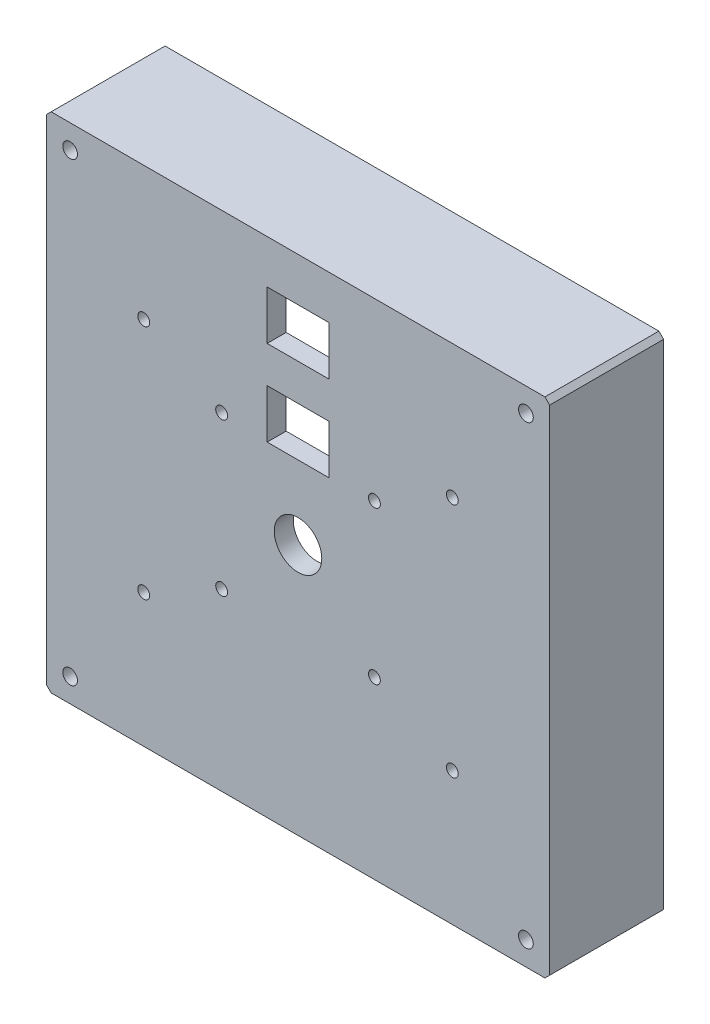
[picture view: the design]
ISO-10303-21;
HEADER;
FILE_DESCRIPTION(('STEP AP214'),'2;1');
FILE_NAME('part.step','',(''),(''),'','','');
FILE_SCHEMA(('AUTOMOTIVE_DESIGN { 1 0 10303 214 1 1 1 1 }'));
ENDSEC;
DATA;
#1=APPLICATION_CONTEXT('core data for automotive mechanical design processes');
#2=APPLICATION_PROTOCOL_DEFINITION('international standard','automotive_design',2000,#1);
#3=PRODUCT_CONTEXT('',#1,'mechanical');
#4=PRODUCT('Part','Part','',(#3));
#5=PRODUCT_RELATED_PRODUCT_CATEGORY('part','',(#4));
#6=PRODUCT_DEFINITION_FORMATION('','',#4);
#7=PRODUCT_DEFINITION_CONTEXT('part definition',#1,'design');
#8=PRODUCT_DEFINITION('design','',#6,#7);
#9=PRODUCT_DEFINITION_SHAPE('','',#8);
#10=(LENGTH_UNIT() NAMED_UNIT(*) SI_UNIT(.MILLI.,.METRE.));
#11=(NAMED_UNIT(*) PLANE_ANGLE_UNIT() SI_UNIT($,.RADIAN.));
#12=(NAMED_UNIT(*) SI_UNIT($,.STERADIAN.) SOLID_ANGLE_UNIT());
#13=UNCERTAINTY_MEASURE_WITH_UNIT(LENGTH_MEASURE(1.E-05),#10,'distance_accuracy_value','');
#14=(GEOMETRIC_REPRESENTATION_CONTEXT(3) GLOBAL_UNCERTAINTY_ASSIGNED_CONTEXT((#13)) GLOBAL_UNIT_ASSIGNED_CONTEXT((#10,
#11,#12)) REPRESENTATION_CONTEXT('',''));
#15=CARTESIAN_POINT('',(0.,0.,0.));
#16=DIRECTION('',(0.,0.,1.));
#17=DIRECTION('',(1.,0.,0.));
#18=AXIS2_PLACEMENT_3D('',#15,#16,#17);
#19=CARTESIAN_POINT('',(-53.,53.,-4.));
#20=DIRECTION('',(-1.,0.,0.));
#21=DIRECTION('',(0.,-1.,0.));
#22=AXIS2_PLACEMENT_3D('',#19,#20,#21);
#23=PLANE('',#22);
#24=DIRECTION('',(0.,-1.,0.));
#25=VECTOR('',#24,1.);
#26=CARTESIAN_POINT('',(-53.,53.,0.));
#27=LINE('',#26,#25);
#28=CARTESIAN_POINT('',(-53.,52.,0.));
#29=VERTEX_POINT('',#28);
#30=CARTESIAN_POINT('',(-53.,-52.,0.));
#31=VERTEX_POINT('',#30);
#32=EDGE_CURVE('E1000',#29,#31,#27,.T.);
#33=ORIENTED_EDGE('',*,*,#32,.F.);
#34=DIRECTION('',(0.,0.,-1.));
#35=VECTOR('',#34,1.);
#36=CARTESIAN_POINT('',(-53.,52.,-4.));
#37=LINE('',#36,#35);
#38=CARTESIAN_POINT('',(-53.,52.,-24.));
#39=VERTEX_POINT('',#38);
#40=EDGE_CURVE('E474',#29,#39,#37,.T.);
#41=ORIENTED_EDGE('',*,*,#40,.T.);
#42=DIRECTION('',(0.,1.,0.));
#43=VECTOR('',#42,1.);
#44=CARTESIAN_POINT('',(-53.,53.,-24.));
#45=LINE('',#44,#43);
#46=CARTESIAN_POINT('',(-53.,-52.,-24.));
#47=VERTEX_POINT('',#46);
#48=EDGE_CURVE('E994',#47,#39,#45,.T.);
#49=ORIENTED_EDGE('',*,*,#48,.F.);
#50=DIRECTION('',(0.,0.,1.));
#51=VECTOR('',#50,1.);
#52=CARTESIAN_POINT('',(-53.,-52.,-4.));
#53=LINE('',#52,#51);
#54=EDGE_CURVE('E471',#47,#31,#53,.T.);
#55=ORIENTED_EDGE('',*,*,#54,.T.);
#56=EDGE_LOOP('',(#33,#41,#49,#55));
#57=FACE_BOUND('',#56,.T.);
#58=ADVANCED_FACE('F33',(#57),#23,.T.);
#59=CARTESIAN_POINT('',(-53.,53.,-4.));
#60=DIRECTION('',(0.,1.,0.));
#61=DIRECTION('',(-1.,0.,0.));
#62=AXIS2_PLACEMENT_3D('',#59,#60,#61);
#63=PLANE('',#62);
#64=DIRECTION('',(-1.,0.,0.));
#65=VECTOR('',#64,1.);
#66=CARTESIAN_POINT('',(-53.,53.,0.));
#67=LINE('',#66,#65);
#68=CARTESIAN_POINT('',(52.,53.,0.));
#69=VERTEX_POINT('',#68);
#70=CARTESIAN_POINT('',(-52.,53.,0.));
#71=VERTEX_POINT('',#70);
#72=EDGE_CURVE('E1009',#69,#71,#67,.T.);
#73=ORIENTED_EDGE('',*,*,#72,.F.);
#74=DIRECTION('',(0.,0.,-1.));
#75=VECTOR('',#74,1.);
#76=CARTESIAN_POINT('',(52.,53.,-4.));
#77=LINE('',#76,#75);
#78=CARTESIAN_POINT('',(52.,53.,-24.));
#79=VERTEX_POINT('',#78);
#80=EDGE_CURVE('E461',#69,#79,#77,.T.);
#81=ORIENTED_EDGE('',*,*,#80,.T.);
#82=DIRECTION('',(1.,0.,0.));
#83=VECTOR('',#82,1.);
#84=CARTESIAN_POINT('',(53.,53.,-24.));
#85=LINE('',#84,#83);
#86=CARTESIAN_POINT('',(-52.,53.,-24.));
#87=VERTEX_POINT('',#86);
#88=EDGE_CURVE('E997',#87,#79,#85,.T.);
#89=ORIENTED_EDGE('',*,*,#88,.F.);
#90=DIRECTION('',(0.,0.,1.));
#91=VECTOR('',#90,1.);
#92=CARTESIAN_POINT('',(-52.,53.,-4.));
#93=LINE('',#92,#91);
#94=EDGE_CURVE('E458',#87,#71,#93,.T.);
#95=ORIENTED_EDGE('',*,*,#94,.T.);
#96=EDGE_LOOP('',(#73,#81,#89,#95));
#97=FACE_BOUND('',#96,.T.);
#98=ADVANCED_FACE('F1122',(#97),#63,.T.);
#99=CARTESIAN_POINT('',(53.,53.,-4.));
#100=DIRECTION('',(1.,0.,0.));
#101=DIRECTION('',(0.,1.,0.));
#102=AXIS2_PLACEMENT_3D('',#99,#100,#101);
#103=PLANE('',#102);
#104=DIRECTION('',(0.,-1.,0.));
#105=VECTOR('',#104,1.);
#106=CARTESIAN_POINT('',(53.,53.,-24.));
#107=LINE('',#106,#105);
#108=CARTESIAN_POINT('',(53.,52.,-24.));
#109=VERTEX_POINT('',#108);
#110=CARTESIAN_POINT('',(53.,-52.,-24.));
#111=VERTEX_POINT('',#110);
#112=EDGE_CURVE('E988',#109,#111,#107,.T.);
#113=ORIENTED_EDGE('',*,*,#112,.F.);
#114=DIRECTION('',(0.,0.,1.));
#115=VECTOR('',#114,1.);
#116=CARTESIAN_POINT('',(53.,52.,-4.));
#117=LINE('',#116,#115);
#118=CARTESIAN_POINT('',(53.,52.,0.));
#119=VERTEX_POINT('',#118);
#120=EDGE_CURVE('E443',#109,#119,#117,.T.);
#121=ORIENTED_EDGE('',*,*,#120,.T.);
#122=DIRECTION('',(0.,1.,0.));
#123=VECTOR('',#122,1.);
#124=CARTESIAN_POINT('',(53.,53.,0.));
#125=LINE('',#124,#123);
#126=CARTESIAN_POINT('',(53.,-52.,0.));
#127=VERTEX_POINT('',#126);
#128=EDGE_CURVE('E1006',#127,#119,#125,.T.);
#129=ORIENTED_EDGE('',*,*,#128,.F.);
#130=DIRECTION('',(0.,0.,-1.));
#131=VECTOR('',#130,1.);
#132=CARTESIAN_POINT('',(53.,-52.,-4.));
#133=LINE('',#132,#131);
#134=EDGE_CURVE('E441',#127,#111,#133,.T.);
#135=ORIENTED_EDGE('',*,*,#134,.T.);
#136=EDGE_LOOP('',(#113,#121,#129,#135));
#137=FACE_BOUND('',#136,.T.);
#138=ADVANCED_FACE('F1096',(#137),#103,.T.);
#139=CARTESIAN_POINT('',(-53.,-53.,-4.));
#140=DIRECTION('',(0.,-1.,0.));
#141=DIRECTION('',(1.,0.,0.));
#142=AXIS2_PLACEMENT_3D('',#139,#140,#141);
#143=PLANE('',#142);
#144=DIRECTION('',(0.,0.,1.));
#145=VECTOR('',#144,1.);
#146=CARTESIAN_POINT('',(-7.49999999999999,-53.,-6.83));
#147=LINE('',#146,#145);
#148=CARTESIAN_POINT('',(-7.5,-53.,-15.83));
#149=VERTEX_POINT('',#148);
#150=CARTESIAN_POINT('',(-7.49999999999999,-53.,-5.83));
#151=VERTEX_POINT('',#150);
#152=EDGE_CURVE('E484',#149,#151,#147,.T.);
#153=ORIENTED_EDGE('',*,*,#152,.T.);
#154=DIRECTION('',(1.,0.,0.));
#155=VECTOR('',#154,1.);
#156=CARTESIAN_POINT('',(6.5,-53.,-5.83));
#157=LINE('',#156,#155);
#158=CARTESIAN_POINT('',(7.5,-53.,-5.83));
#159=VERTEX_POINT('',#158);
#160=EDGE_CURVE('E490',#151,#159,#157,.T.);
#161=ORIENTED_EDGE('',*,*,#160,.T.);
#162=DIRECTION('',(0.,0.,-1.));
#163=VECTOR('',#162,1.);
#164=CARTESIAN_POINT('',(7.5,-53.,-14.83));
#165=LINE('',#164,#163);
#166=CARTESIAN_POINT('',(7.5,-53.,-15.83));
#167=VERTEX_POINT('',#166);
#168=EDGE_CURVE('E488',#159,#167,#165,.T.);
#169=ORIENTED_EDGE('',*,*,#168,.T.);
#170=DIRECTION('',(-1.,0.,0.));
#171=VECTOR('',#170,1.);
#172=CARTESIAN_POINT('',(-6.49999999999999,-53.,-15.83));
#173=LINE('',#172,#171);
#174=EDGE_CURVE('E486',#167,#149,#173,.T.);
#175=ORIENTED_EDGE('',*,*,#174,.T.);
#176=EDGE_LOOP('',(#153,#161,#169,#175));
#177=FACE_BOUND('',#176,.T.);
#178=DIRECTION('',(1.,0.,0.));
#179=VECTOR('',#178,1.);
#180=CARTESIAN_POINT('',(-53.,-53.,0.));
#181=LINE('',#180,#179);
#182=CARTESIAN_POINT('',(-52.,-53.,0.));
#183=VERTEX_POINT('',#182);
#184=CARTESIAN_POINT('',(52.,-53.,0.));
#185=VERTEX_POINT('',#184);
#186=EDGE_CURVE('E1003',#183,#185,#181,.T.);
#187=ORIENTED_EDGE('',*,*,#186,.F.);
#188=DIRECTION('',(0.,0.,-1.));
#189=VECTOR('',#188,1.);
#190=CARTESIAN_POINT('',(-52.,-53.,-4.));
#191=LINE('',#190,#189);
#192=CARTESIAN_POINT('',(-52.,-53.,-24.));
#193=VERTEX_POINT('',#192);
#194=EDGE_CURVE('E479',#183,#193,#191,.T.);
#195=ORIENTED_EDGE('',*,*,#194,.T.);
#196=DIRECTION('',(-1.,0.,0.));
#197=VECTOR('',#196,1.);
#198=CARTESIAN_POINT('',(53.,-53.,-24.));
#199=LINE('',#198,#197);
#200=CARTESIAN_POINT('',(52.,-53.,-24.));
#201=VERTEX_POINT('',#200);
#202=EDGE_CURVE('E991',#201,#193,#199,.T.);
#203=ORIENTED_EDGE('',*,*,#202,.F.);
#204=DIRECTION('',(0.,0.,1.));
#205=VECTOR('',#204,1.);
#206=CARTESIAN_POINT('',(52.,-53.,-4.));
#207=LINE('',#206,#205);
#208=EDGE_CURVE('E476',#201,#185,#207,.T.);
#209=ORIENTED_EDGE('',*,*,#208,.T.);
#210=EDGE_LOOP('',(#187,#195,#203,#209));
#211=FACE_BOUND('',#210,.T.);
#212=ADVANCED_FACE('F1092',(#177,#211),#143,.T.);
#213=CARTESIAN_POINT('',(0.,0.,0.));
#214=DIRECTION('',(0.,0.,1.));
#215=DIRECTION('',(1.,0.,0.));
#216=AXIS2_PLACEMENT_3D('',#213,#214,#215);
#217=PLANE('',#216);
#218=DIRECTION('',(0.,-1.,0.));
#219=VECTOR('',#218,1.);
#220=CARTESIAN_POINT('',(-6.5,43.8,0.));
#221=LINE('',#220,#219);
#222=CARTESIAN_POINT('',(-6.5,43.8,0.));
#223=VERTEX_POINT('',#222);
#224=CARTESIAN_POINT('',(-6.5,33.5,0.));
#225=VERTEX_POINT('',#224);
#226=EDGE_CURVE('E848',#223,#225,#221,.T.);
#227=ORIENTED_EDGE('',*,*,#226,.F.);
#228=DIRECTION('',(-1.,0.,0.));
#229=VECTOR('',#228,1.);
#230=CARTESIAN_POINT('',(-6.5,43.8,0.));
#231=LINE('',#230,#229);
#232=CARTESIAN_POINT('',(6.5,43.8,0.));
#233=VERTEX_POINT('',#232);
#234=EDGE_CURVE('E857',#233,#223,#231,.T.);
#235=ORIENTED_EDGE('',*,*,#234,.F.);
#236=DIRECTION('',(0.,1.,0.));
#237=VECTOR('',#236,1.);
#238=CARTESIAN_POINT('',(6.5,43.8,0.));
#239=LINE('',#238,#237);
#240=CARTESIAN_POINT('',(6.5,33.5,0.));
#241=VERTEX_POINT('',#240);
#242=EDGE_CURVE('E854',#241,#233,#239,.T.);
#243=ORIENTED_EDGE('',*,*,#242,.F.);
#244=DIRECTION('',(1.,0.,0.));
#245=VECTOR('',#244,1.);
#246=CARTESIAN_POINT('',(-6.5,33.5,0.));
#247=LINE('',#246,#245);
#248=EDGE_CURVE('E850',#225,#241,#247,.T.);
#249=ORIENTED_EDGE('',*,*,#248,.F.);
#250=EDGE_LOOP('',(#227,#235,#243,#249));
#251=FACE_BOUND('',#250,.T.);
#252=CARTESIAN_POINT('',(0.,0.,0.));
#253=DIRECTION('',(0.,0.,1.));
#254=DIRECTION('',(1.,0.,0.));
#255=AXIS2_PLACEMENT_3D('',#252,#253,#254);
#256=CIRCLE('',#255,5.);
#257=CARTESIAN_POINT('',(5.,0.,0.));
#258=VERTEX_POINT('',#257);
#259=EDGE_CURVE('E845',#258,#258,#256,.T.);
#260=ORIENTED_EDGE('',*,*,#259,.F.);
#261=EDGE_LOOP('',(#260));
#262=FACE_BOUND('',#261,.T.);
#263=CARTESIAN_POINT('',(-16.086679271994,16.086679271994,0.));
#264=DIRECTION('',(0.,0.,1.));
#265=DIRECTION('',(1.,0.,0.));
#266=AXIS2_PLACEMENT_3D('',#263,#264,#265);
#267=CIRCLE('',#266,1.25);
#268=CARTESIAN_POINT('',(-14.836679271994,16.086679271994,0.));
#269=VERTEX_POINT('',#268);
#270=EDGE_CURVE('E870',#269,#269,#267,.T.);
#271=ORIENTED_EDGE('',*,*,#270,.F.);
#272=EDGE_LOOP('',(#271));
#273=FACE_BOUND('',#272,.T.);
#274=DIRECTION('',(0.,-1.,0.));
#275=VECTOR('',#274,1.);
#276=CARTESIAN_POINT('',(-6.49999999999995,25.8,0.));
#277=LINE('',#276,#275);
#278=CARTESIAN_POINT('',(-6.49999999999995,25.8,0.));
#279=VERTEX_POINT('',#278);
#280=CARTESIAN_POINT('',(-6.49999999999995,15.5,0.));
#281=VERTEX_POINT('',#280);
#282=EDGE_CURVE('E888',#279,#281,#277,.T.);
#283=ORIENTED_EDGE('',*,*,#282,.F.);
#284=DIRECTION('',(-1.,0.,0.));
#285=VECTOR('',#284,1.);
#286=CARTESIAN_POINT('',(-6.49999999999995,25.8,0.));
#287=LINE('',#286,#285);
#288=CARTESIAN_POINT('',(6.49999999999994,25.8,0.));
#289=VERTEX_POINT('',#288);
#290=EDGE_CURVE('E897',#289,#279,#287,.T.);
#291=ORIENTED_EDGE('',*,*,#290,.F.);
#292=DIRECTION('',(0.,1.,0.));
#293=VECTOR('',#292,1.);
#294=CARTESIAN_POINT('',(6.49999999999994,25.8,0.));
#295=LINE('',#294,#293);
#296=CARTESIAN_POINT('',(6.49999999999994,15.5,0.));
#297=VERTEX_POINT('',#296);
#298=EDGE_CURVE('E894',#297,#289,#295,.T.);
#299=ORIENTED_EDGE('',*,*,#298,.F.);
#300=DIRECTION('',(1.,0.,0.));
#301=VECTOR('',#300,1.);
#302=CARTESIAN_POINT('',(-6.49999999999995,15.5,0.));
#303=LINE('',#302,#301);
#304=EDGE_CURVE('E890',#281,#297,#303,.T.);
#305=ORIENTED_EDGE('',*,*,#304,.F.);
#306=EDGE_LOOP('',(#283,#291,#299,#305));
#307=FACE_BOUND('',#306,.T.);
#308=CARTESIAN_POINT('',(32.5,24.9,0.));
#309=DIRECTION('',(0.,0.,1.));
#310=DIRECTION('',(1.,0.,0.));
#311=AXIS2_PLACEMENT_3D('',#308,#309,#310);
#312=CIRCLE('',#311,1.25);
#313=CARTESIAN_POINT('',(33.75,24.9,0.));
#314=VERTEX_POINT('',#313);
#315=EDGE_CURVE('E891',#314,#314,#312,.T.);
#316=ORIENTED_EDGE('',*,*,#315,.F.);
#317=EDGE_LOOP('',(#316));
#318=FACE_BOUND('',#317,.T.);
#319=CARTESIAN_POINT('',(-32.5,24.9,0.));
#320=DIRECTION('',(0.,0.,1.));
#321=DIRECTION('',(1.,0.,0.));
#322=AXIS2_PLACEMENT_3D('',#319,#320,#321);
#323=CIRCLE('',#322,1.25);
#324=CARTESIAN_POINT('',(-31.25,24.9,0.));
#325=VERTEX_POINT('',#324);
#326=EDGE_CURVE('E910',#325,#325,#323,.T.);
#327=ORIENTED_EDGE('',*,*,#326,.F.);
#328=EDGE_LOOP('',(#327));
#329=FACE_BOUND('',#328,.T.);
#330=CARTESIAN_POINT('',(-32.5,-24.9,0.));
#331=DIRECTION('',(0.,0.,1.));
#332=DIRECTION('',(1.,0.,0.));
#333=AXIS2_PLACEMENT_3D('',#330,#331,#332);
#334=CIRCLE('',#333,1.25);
#335=CARTESIAN_POINT('',(-31.25,-24.9,0.));
#336=VERTEX_POINT('',#335);
#337=EDGE_CURVE('E885',#336,#336,#334,.T.);
#338=ORIENTED_EDGE('',*,*,#337,.F.);
#339=EDGE_LOOP('',(#338));
#340=FACE_BOUND('',#339,.T.);
#341=CARTESIAN_POINT('',(16.086679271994,16.086679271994,0.));
#342=DIRECTION('',(0.,0.,1.));
#343=DIRECTION('',(1.,0.,0.));
#344=AXIS2_PLACEMENT_3D('',#341,#342,#343);
#345=CIRCLE('',#344,1.25);
#346=CARTESIAN_POINT('',(17.336679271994,16.086679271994,0.));
#347=VERTEX_POINT('',#346);
#348=EDGE_CURVE('E873',#347,#347,#345,.T.);
#349=ORIENTED_EDGE('',*,*,#348,.F.);
#350=EDGE_LOOP('',(#349));
#351=FACE_BOUND('',#350,.T.);
#352=CARTESIAN_POINT('',(-16.086679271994,-16.086679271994,0.));
#353=DIRECTION('',(0.,0.,1.));
#354=DIRECTION('',(1.,0.,0.));
#355=AXIS2_PLACEMENT_3D('',#352,#353,#354);
#356=CIRCLE('',#355,1.25);
#357=CARTESIAN_POINT('',(-14.836679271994,-16.086679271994,0.));
#358=VERTEX_POINT('',#357);
#359=EDGE_CURVE('E876',#358,#358,#356,.T.);
#360=ORIENTED_EDGE('',*,*,#359,.F.);
#361=EDGE_LOOP('',(#360));
#362=FACE_BOUND('',#361,.T.);
#363=CARTESIAN_POINT('',(16.086679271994,-16.086679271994,0.));
#364=DIRECTION('',(0.,0.,1.));
#365=DIRECTION('',(1.,0.,0.));
#366=AXIS2_PLACEMENT_3D('',#363,#364,#365);
#367=CIRCLE('',#366,1.25);
#368=CARTESIAN_POINT('',(17.336679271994,-16.086679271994,0.));
#369=VERTEX_POINT('',#368);
#370=EDGE_CURVE('E879',#369,#369,#367,.T.);
#371=ORIENTED_EDGE('',*,*,#370,.F.);
#372=EDGE_LOOP('',(#371));
#373=FACE_BOUND('',#372,.T.);
#374=CARTESIAN_POINT('',(32.5,-24.9,0.));
#375=DIRECTION('',(0.,0.,1.));
#376=DIRECTION('',(1.,0.,0.));
#377=AXIS2_PLACEMENT_3D('',#374,#375,#376);
#378=CIRCLE('',#377,1.25);
#379=CARTESIAN_POINT('',(33.75,-24.9,0.));
#380=VERTEX_POINT('',#379);
#381=EDGE_CURVE('E882',#380,#380,#378,.T.);
#382=ORIENTED_EDGE('',*,*,#381,.F.);
#383=EDGE_LOOP('',(#382));
#384=FACE_BOUND('',#383,.T.);
#385=CARTESIAN_POINT('',(48.,48.,0.));
#386=DIRECTION('',(0.,0.,1.));
#387=DIRECTION('',(1.,0.,0.));
#388=AXIS2_PLACEMENT_3D('',#385,#386,#387);
#389=CIRCLE('',#388,1.55);
#390=CARTESIAN_POINT('',(49.55,48.,0.));
#391=VERTEX_POINT('',#390);
#392=EDGE_CURVE('E920',#391,#391,#389,.T.);
#393=ORIENTED_EDGE('',*,*,#392,.F.);
#394=EDGE_LOOP('',(#393));
#395=FACE_BOUND('',#394,.T.);
#396=CARTESIAN_POINT('',(-48.,-48.,0.));
#397=DIRECTION('',(0.,0.,1.));
#398=DIRECTION('',(1.,0.,0.));
#399=AXIS2_PLACEMENT_3D('',#396,#397,#398);
#400=CIRCLE('',#399,1.55);
#401=CARTESIAN_POINT('',(-46.45,-48.,0.));
#402=VERTEX_POINT('',#401);
#403=EDGE_CURVE('E918',#402,#402,#400,.T.);
#404=ORIENTED_EDGE('',*,*,#403,.F.);
#405=EDGE_LOOP('',(#404));
#406=FACE_BOUND('',#405,.T.);
#407=CARTESIAN_POINT('',(48.,-48.,0.));
#408=DIRECTION('',(0.,0.,1.));
#409=DIRECTION('',(1.,0.,0.));
#410=AXIS2_PLACEMENT_3D('',#407,#408,#409);
#411=CIRCLE('',#410,1.55);
#412=CARTESIAN_POINT('',(49.55,-48.,0.));
#413=VERTEX_POINT('',#412);
#414=EDGE_CURVE('E915',#413,#413,#411,.T.);
#415=ORIENTED_EDGE('',*,*,#414,.F.);
#416=EDGE_LOOP('',(#415));
#417=FACE_BOUND('',#416,.T.);
#418=CARTESIAN_POINT('',(-48.,48.,0.));
#419=DIRECTION('',(0.,0.,1.));
#420=DIRECTION('',(1.,0.,0.));
#421=AXIS2_PLACEMENT_3D('',#418,#419,#420);
#422=CIRCLE('',#421,1.55);
#423=CARTESIAN_POINT('',(-46.45,48.,0.));
#424=VERTEX_POINT('',#423);
#425=EDGE_CURVE('E923',#424,#424,#422,.T.);
#426=ORIENTED_EDGE('',*,*,#425,.F.);
#427=EDGE_LOOP('',(#426));
#428=FACE_BOUND('',#427,.T.);
#429=ORIENTED_EDGE('',*,*,#128,.T.);
#430=DIRECTION('',(0.707106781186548,-0.707106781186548,0.));
#431=VECTOR('',#430,1.);
#432=CARTESIAN_POINT('',(52.5,52.5,0.));
#433=LINE('',#432,#431);
#434=EDGE_CURVE('E456',#119,#69,#433,.F.);
#435=ORIENTED_EDGE('',*,*,#434,.T.);
#436=ORIENTED_EDGE('',*,*,#72,.T.);
#437=DIRECTION('',(0.707106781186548,0.707106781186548,0.));
#438=VECTOR('',#437,1.);
#439=CARTESIAN_POINT('',(-52.5,52.5,0.));
#440=LINE('',#439,#438);
#441=EDGE_CURVE('E454',#71,#29,#440,.F.);
#442=ORIENTED_EDGE('',*,*,#441,.T.);
#443=ORIENTED_EDGE('',*,*,#32,.T.);
#444=DIRECTION('',(-0.707106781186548,0.707106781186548,0.));
#445=VECTOR('',#444,1.);
#446=CARTESIAN_POINT('',(-52.5,-52.5,0.));
#447=LINE('',#446,#445);
#448=EDGE_CURVE('E452',#31,#183,#447,.F.);
#449=ORIENTED_EDGE('',*,*,#448,.T.);
#450=ORIENTED_EDGE('',*,*,#186,.T.);
#451=DIRECTION('',(-0.70710678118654,-0.707106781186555,0.));
#452=VECTOR('',#451,1.);
#453=CARTESIAN_POINT('',(52.5000000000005,-52.4999999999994,0.));
#454=LINE('',#453,#452);
#455=EDGE_CURVE('E450',#185,#127,#454,.F.);
#456=ORIENTED_EDGE('',*,*,#455,.T.);
#457=EDGE_LOOP('',(#429,#435,#436,#442,#443,#449,#450,#456));
#458=FACE_BOUND('',#457,.T.);
#459=ADVANCED_FACE('F1095',(#251,#262,#273,#307,#318,#329,#340,#351,#362,#373,#384,#395,#406,
#417,#428,#458),#217,.T.);
#460=CARTESIAN_POINT('',(0.,0.,-24.));
#461=DIRECTION('',(0.,0.,-1.));
#462=DIRECTION('',(-1.,0.,0.));
#463=AXIS2_PLACEMENT_3D('',#460,#461,#462);
#464=PLANE('',#463);
#465=CARTESIAN_POINT('',(48.,48.,-24.));
#466=DIRECTION('',(0.,0.,-1.));
#467=DIRECTION('',(-1.,0.,0.));
#468=AXIS2_PLACEMENT_3D('',#465,#466,#467);
#469=CIRCLE('',#468,1.55);
#470=CARTESIAN_POINT('',(46.45,48.,-24.));
#471=VERTEX_POINT('',#470);
#472=EDGE_CURVE('E952',#471,#471,#469,.T.);
#473=ORIENTED_EDGE('',*,*,#472,.F.);
#474=EDGE_LOOP('',(#473));
#475=FACE_BOUND('',#474,.T.);
#476=CARTESIAN_POINT('',(-48.,-48.,-24.));
#477=DIRECTION('',(0.,0.,-1.));
#478=DIRECTION('',(-1.,0.,0.));
#479=AXIS2_PLACEMENT_3D('',#476,#477,#478);
#480=CIRCLE('',#479,1.55);
#481=CARTESIAN_POINT('',(-49.55,-48.,-24.));
#482=VERTEX_POINT('',#481);
#483=EDGE_CURVE('E1018',#482,#482,#480,.T.);
#484=ORIENTED_EDGE('',*,*,#483,.F.);
#485=EDGE_LOOP('',(#484));
#486=FACE_BOUND('',#485,.T.);
#487=CARTESIAN_POINT('',(48.,-48.,-24.));
#488=DIRECTION('',(0.,0.,-1.));
#489=DIRECTION('',(-1.,0.,0.));
#490=AXIS2_PLACEMENT_3D('',#487,#488,#489);
#491=CIRCLE('',#490,1.55);
#492=CARTESIAN_POINT('',(46.45,-48.,-24.));
#493=VERTEX_POINT('',#492);
#494=EDGE_CURVE('E1015',#493,#493,#491,.T.);
#495=ORIENTED_EDGE('',*,*,#494,.F.);
#496=EDGE_LOOP('',(#495));
#497=FACE_BOUND('',#496,.T.);
#498=CARTESIAN_POINT('',(-48.,48.,-24.));
#499=DIRECTION('',(0.,0.,-1.));
#500=DIRECTION('',(-1.,0.,0.));
#501=AXIS2_PLACEMENT_3D('',#498,#499,#500);
#502=CIRCLE('',#501,1.55);
#503=CARTESIAN_POINT('',(-49.55,48.,-24.));
#504=VERTEX_POINT('',#503);
#505=EDGE_CURVE('E928',#504,#504,#502,.T.);
#506=ORIENTED_EDGE('',*,*,#505,.F.);
#507=EDGE_LOOP('',(#506));
#508=FACE_BOUND('',#507,.T.);
#509=ORIENTED_EDGE('',*,*,#88,.T.);
#510=DIRECTION('',(-0.707106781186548,0.707106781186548,0.));
#511=VECTOR('',#510,1.);
#512=CARTESIAN_POINT('',(52.5,52.5,-24.));
#513=LINE('',#512,#511);
#514=EDGE_CURVE('E469',#79,#109,#513,.F.);
#515=ORIENTED_EDGE('',*,*,#514,.T.);
#516=ORIENTED_EDGE('',*,*,#112,.T.);
#517=DIRECTION('',(0.70710678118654,0.707106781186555,0.));
#518=VECTOR('',#517,1.);
#519=CARTESIAN_POINT('',(52.5000000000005,-52.4999999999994,-24.));
#520=LINE('',#519,#518);
#521=EDGE_CURVE('E463',#111,#201,#520,.F.);
#522=ORIENTED_EDGE('',*,*,#521,.T.);
#523=ORIENTED_EDGE('',*,*,#202,.T.);
#524=DIRECTION('',(0.707106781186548,-0.707106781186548,0.));
#525=VECTOR('',#524,1.);
#526=CARTESIAN_POINT('',(-52.5,-52.5,-24.));
#527=LINE('',#526,#525);
#528=EDGE_CURVE('E465',#193,#47,#527,.F.);
#529=ORIENTED_EDGE('',*,*,#528,.T.);
#530=ORIENTED_EDGE('',*,*,#48,.T.);
#531=DIRECTION('',(-0.707106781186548,-0.707106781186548,0.));
#532=VECTOR('',#531,1.);
#533=CARTESIAN_POINT('',(-52.5,52.5,-24.));
#534=LINE('',#533,#532);
#535=EDGE_CURVE('E467',#39,#87,#534,.F.);
#536=ORIENTED_EDGE('',*,*,#535,.T.);
#537=EDGE_LOOP('',(#509,#515,#516,#522,#523,#529,#530,#536));
#538=FACE_BOUND('',#537,.T.);
#539=DIRECTION('',(-1.,0.,0.));
#540=VECTOR('',#539,1.);
#541=CARTESIAN_POINT('',(41.,-48.,-24.));
#542=LINE('',#541,#540);
#543=CARTESIAN_POINT('',(41.,-48.,-24.));
#544=VERTEX_POINT('',#543);
#545=CARTESIAN_POINT('',(-41.,-48.,-24.));
#546=VERTEX_POINT('',#545);
#547=EDGE_CURVE('E931',#544,#546,#542,.T.);
#548=ORIENTED_EDGE('',*,*,#547,.F.);
#549=DIRECTION('',(-0.707106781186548,-0.707106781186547,0.));
#550=VECTOR('',#549,1.);
#551=CARTESIAN_POINT('',(48.,-41.,-24.));
#552=LINE('',#551,#550);
#553=CARTESIAN_POINT('',(48.,-41.,-24.));
#554=VERTEX_POINT('',#553);
#555=EDGE_CURVE('E929',#554,#544,#552,.T.);
#556=ORIENTED_EDGE('',*,*,#555,.F.);
#557=DIRECTION('',(0.,-1.,0.));
#558=VECTOR('',#557,1.);
#559=CARTESIAN_POINT('',(48.,41.,-24.));
#560=LINE('',#559,#558);
#561=CARTESIAN_POINT('',(48.,41.,-24.));
#562=VERTEX_POINT('',#561);
#563=EDGE_CURVE('E945',#562,#554,#560,.T.);
#564=ORIENTED_EDGE('',*,*,#563,.F.);
#565=DIRECTION('',(0.707106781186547,-0.707106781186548,0.));
#566=VECTOR('',#565,1.);
#567=CARTESIAN_POINT('',(41.,48.,-24.));
#568=LINE('',#567,#566);
#569=CARTESIAN_POINT('',(41.,48.,-24.));
#570=VERTEX_POINT('',#569);
#571=EDGE_CURVE('E942',#570,#562,#568,.T.);
#572=ORIENTED_EDGE('',*,*,#571,.F.);
#573=DIRECTION('',(1.,0.,0.));
#574=VECTOR('',#573,1.);
#575=CARTESIAN_POINT('',(-41.,48.,-24.));
#576=LINE('',#575,#574);
#577=CARTESIAN_POINT('',(-41.,48.,-24.));
#578=VERTEX_POINT('',#577);
#579=EDGE_CURVE('E940',#578,#570,#576,.T.);
#580=ORIENTED_EDGE('',*,*,#579,.F.);
#581=DIRECTION('',(0.707106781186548,0.707106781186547,0.));
#582=VECTOR('',#581,1.);
#583=CARTESIAN_POINT('',(-48.,41.,-24.));
#584=LINE('',#583,#582);
#585=CARTESIAN_POINT('',(-48.,41.,-24.));
#586=VERTEX_POINT('',#585);
#587=EDGE_CURVE('E938',#586,#578,#584,.T.);
#588=ORIENTED_EDGE('',*,*,#587,.F.);
#589=DIRECTION('',(0.,1.,0.));
#590=VECTOR('',#589,1.);
#591=CARTESIAN_POINT('',(-48.,-41.,-24.));
#592=LINE('',#591,#590);
#593=CARTESIAN_POINT('',(-48.,-41.,-24.));
#594=VERTEX_POINT('',#593);
#595=EDGE_CURVE('E936',#594,#586,#592,.T.);
#596=ORIENTED_EDGE('',*,*,#595,.F.);
#597=DIRECTION('',(-0.707106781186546,0.707106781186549,0.));
#598=VECTOR('',#597,1.);
#599=CARTESIAN_POINT('',(-41.,-48.,-24.));
#600=LINE('',#599,#598);
#601=EDGE_CURVE('E934',#546,#594,#600,.T.);
#602=ORIENTED_EDGE('',*,*,#601,.F.);
#603=EDGE_LOOP('',(#548,#556,#564,#572,#580,#588,#596,#602));
#604=FACE_BOUND('',#603,.T.);
#605=ADVANCED_FACE('F1109',(#475,#486,#497,#508,#538,#604),#464,.T.);
#606=CARTESIAN_POINT('',(48.,-41.,-24.));
#607=DIRECTION('',(-0.707106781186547,0.707106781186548,0.));
#608=DIRECTION('',(-0.707106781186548,-0.707106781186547,0.));
#609=AXIS2_PLACEMENT_3D('',#606,#607,#608);
#610=PLANE('',#609);
#611=DIRECTION('',(-0.707106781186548,-0.707106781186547,0.));
#612=VECTOR('',#611,1.);
#613=CARTESIAN_POINT('',(48.,-41.,-4.));
#614=LINE('',#613,#612);
#615=CARTESIAN_POINT('',(48.,-41.,-4.));
#616=VERTEX_POINT('',#615);
#617=CARTESIAN_POINT('',(41.,-48.,-4.));
#618=VERTEX_POINT('',#617);
#619=EDGE_CURVE('E948',#616,#618,#614,.T.);
#620=ORIENTED_EDGE('',*,*,#619,.F.);
#621=DIRECTION('',(0.,0.,1.));
#622=VECTOR('',#621,1.);
#623=CARTESIAN_POINT('',(48.,-41.,-24.));
#624=LINE('',#623,#622);
#625=EDGE_CURVE('E947',#554,#616,#624,.T.);
#626=ORIENTED_EDGE('',*,*,#625,.F.);
#627=ORIENTED_EDGE('',*,*,#555,.T.);
#628=DIRECTION('',(0.,0.,1.));
#629=VECTOR('',#628,1.);
#630=CARTESIAN_POINT('',(41.,-48.,-24.));
#631=LINE('',#630,#629);
#632=EDGE_CURVE('E985',#544,#618,#631,.T.);
#633=ORIENTED_EDGE('',*,*,#632,.T.);
#634=EDGE_LOOP('',(#620,#626,#627,#633));
#635=FACE_BOUND('',#634,.T.);
#636=ADVANCED_FACE('F1140',(#635),#610,.T.);
#637=CARTESIAN_POINT('',(41.,-48.,-24.));
#638=DIRECTION('',(0.,1.,0.));
#639=DIRECTION('',(0.,0.,1.));
#640=AXIS2_PLACEMENT_3D('',#637,#638,#639);
#641=PLANE('',#640);
#642=DIRECTION('',(0.,0.,1.));
#643=VECTOR('',#642,1.);
#644=CARTESIAN_POINT('',(-6.49999999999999,-48.,-24.));
#645=LINE('',#644,#643);
#646=CARTESIAN_POINT('',(-6.49999999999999,-48.,-14.83));
#647=VERTEX_POINT('',#646);
#648=CARTESIAN_POINT('',(-6.49999999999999,-48.,-6.83));
#649=VERTEX_POINT('',#648);
#650=EDGE_CURVE('E433',#647,#649,#645,.T.);
#651=ORIENTED_EDGE('',*,*,#650,.F.);
#652=DIRECTION('',(-1.,0.,0.));
#653=VECTOR('',#652,1.);
#654=CARTESIAN_POINT('',(41.,-48.,-14.83));
#655=LINE('',#654,#653);
#656=CARTESIAN_POINT('',(6.50000000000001,-48.,-14.83));
#657=VERTEX_POINT('',#656);
#658=EDGE_CURVE('E421',#657,#647,#655,.T.);
#659=ORIENTED_EDGE('',*,*,#658,.F.);
#660=DIRECTION('',(0.,0.,-1.));
#661=VECTOR('',#660,1.);
#662=CARTESIAN_POINT('',(6.50000000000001,-48.,-24.));
#663=LINE('',#662,#661);
#664=CARTESIAN_POINT('',(6.5,-48.,-6.83));
#665=VERTEX_POINT('',#664);
#666=EDGE_CURVE('E429',#665,#657,#663,.T.);
#667=ORIENTED_EDGE('',*,*,#666,.F.);
#668=DIRECTION('',(1.,0.,0.));
#669=VECTOR('',#668,1.);
#670=CARTESIAN_POINT('',(41.,-48.,-6.82999999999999));
#671=LINE('',#670,#669);
#672=EDGE_CURVE('E440',#649,#665,#671,.T.);
#673=ORIENTED_EDGE('',*,*,#672,.F.);
#674=EDGE_LOOP('',(#651,#659,#667,#673));
#675=FACE_BOUND('',#674,.T.);
#676=DIRECTION('',(-1.,0.,0.));
#677=VECTOR('',#676,1.);
#678=CARTESIAN_POINT('',(41.,-48.,-4.));
#679=LINE('',#678,#677);
#680=CARTESIAN_POINT('',(-41.,-48.,-4.));
#681=VERTEX_POINT('',#680);
#682=EDGE_CURVE('E951',#618,#681,#679,.T.);
#683=ORIENTED_EDGE('',*,*,#682,.F.);
#684=ORIENTED_EDGE('',*,*,#632,.F.);
#685=ORIENTED_EDGE('',*,*,#547,.T.);
#686=DIRECTION('',(0.,0.,1.));
#687=VECTOR('',#686,1.);
#688=CARTESIAN_POINT('',(-41.,-48.,-24.));
#689=LINE('',#688,#687);
#690=EDGE_CURVE('E983',#546,#681,#689,.T.);
#691=ORIENTED_EDGE('',*,*,#690,.T.);
#692=EDGE_LOOP('',(#683,#684,#685,#691));
#693=FACE_BOUND('',#692,.T.);
#694=ADVANCED_FACE('F438',(#675,#693),#641,.T.);
#695=CARTESIAN_POINT('',(-41.,-48.,-24.));
#696=DIRECTION('',(0.707106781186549,0.707106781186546,0.));
#697=DIRECTION('',(-0.707106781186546,0.707106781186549,0.));
#698=AXIS2_PLACEMENT_3D('',#695,#696,#697);
#699=PLANE('',#698);
#700=DIRECTION('',(-0.707106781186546,0.707106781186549,0.));
#701=VECTOR('',#700,1.);
#702=CARTESIAN_POINT('',(-41.,-48.,-4.));
#703=LINE('',#702,#701);
#704=CARTESIAN_POINT('',(-48.,-41.,-4.));
#705=VERTEX_POINT('',#704);
#706=EDGE_CURVE('E955',#681,#705,#703,.T.);
#707=ORIENTED_EDGE('',*,*,#706,.F.);
#708=ORIENTED_EDGE('',*,*,#690,.F.);
#709=ORIENTED_EDGE('',*,*,#601,.T.);
#710=DIRECTION('',(0.,0.,1.));
#711=VECTOR('',#710,1.);
#712=CARTESIAN_POINT('',(-48.,-41.,-24.));
#713=LINE('',#712,#711);
#714=EDGE_CURVE('E981',#594,#705,#713,.T.);
#715=ORIENTED_EDGE('',*,*,#714,.T.);
#716=EDGE_LOOP('',(#707,#708,#709,#715));
#717=FACE_BOUND('',#716,.T.);
#718=ADVANCED_FACE('F1779',(#717),#699,.T.);
#719=CARTESIAN_POINT('',(-48.,-41.,-24.));
#720=DIRECTION('',(1.,0.,0.));
#721=DIRECTION('',(0.,0.,-1.));
#722=AXIS2_PLACEMENT_3D('',#719,#720,#721);
#723=PLANE('',#722);
#724=CARTESIAN_POINT('',(-48.,-23.,-12.));
#725=DIRECTION('',(1.,0.,0.));
#726=DIRECTION('',(0.,0.,-1.));
#727=AXIS2_PLACEMENT_3D('',#724,#725,#726);
#728=CIRCLE('',#727,1.6);
#729=CARTESIAN_POINT('',(-48.,-21.4,-12.));
#730=VERTEX_POINT('',#729);
#731=EDGE_CURVE('E499',#730,#730,#728,.F.);
#732=ORIENTED_EDGE('',*,*,#731,.T.);
#733=EDGE_LOOP('',(#732));
#734=FACE_BOUND('',#733,.T.);
#735=CARTESIAN_POINT('',(-48.,23.,-12.));
#736=DIRECTION('',(1.,0.,0.));
#737=DIRECTION('',(0.,0.,-1.));
#738=AXIS2_PLACEMENT_3D('',#735,#736,#737);
#739=CIRCLE('',#738,1.6);
#740=CARTESIAN_POINT('',(-48.,24.6,-12.));
#741=VERTEX_POINT('',#740);
#742=EDGE_CURVE('E507',#741,#741,#739,.F.);
#743=ORIENTED_EDGE('',*,*,#742,.T.);
#744=EDGE_LOOP('',(#743));
#745=FACE_BOUND('',#744,.T.);
#746=DIRECTION('',(0.,1.,0.));
#747=VECTOR('',#746,1.);
#748=CARTESIAN_POINT('',(-48.,-41.,-4.));
#749=LINE('',#748,#747);
#750=CARTESIAN_POINT('',(-48.,41.,-4.));
#751=VERTEX_POINT('',#750);
#752=EDGE_CURVE('E958',#705,#751,#749,.T.);
#753=ORIENTED_EDGE('',*,*,#752,.F.);
#754=ORIENTED_EDGE('',*,*,#714,.F.);
#755=ORIENTED_EDGE('',*,*,#595,.T.);
#756=DIRECTION('',(0.,0.,1.));
#757=VECTOR('',#756,1.);
#758=CARTESIAN_POINT('',(-48.,41.,-24.));
#759=LINE('',#758,#757);
#760=EDGE_CURVE('E979',#586,#751,#759,.T.);
#761=ORIENTED_EDGE('',*,*,#760,.T.);
#762=EDGE_LOOP('',(#753,#754,#755,#761));
#763=FACE_BOUND('',#762,.T.);
#764=ADVANCED_FACE('F1771',(#734,#745,#763),#723,.T.);
#765=CARTESIAN_POINT('',(-48.,41.,-24.));
#766=DIRECTION('',(0.707106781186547,-0.707106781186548,0.));
#767=DIRECTION('',(0.707106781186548,0.707106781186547,0.));
#768=AXIS2_PLACEMENT_3D('',#765,#766,#767);
#769=PLANE('',#768);
#770=DIRECTION('',(0.707106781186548,0.707106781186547,0.));
#771=VECTOR('',#770,1.);
#772=CARTESIAN_POINT('',(-48.,41.,-4.));
#773=LINE('',#772,#771);
#774=CARTESIAN_POINT('',(-41.,48.,-4.));
#775=VERTEX_POINT('',#774);
#776=EDGE_CURVE('E961',#751,#775,#773,.T.);
#777=ORIENTED_EDGE('',*,*,#776,.F.);
#778=ORIENTED_EDGE('',*,*,#760,.F.);
#779=ORIENTED_EDGE('',*,*,#587,.T.);
#780=DIRECTION('',(0.,0.,1.));
#781=VECTOR('',#780,1.);
#782=CARTESIAN_POINT('',(-41.,48.,-24.));
#783=LINE('',#782,#781);
#784=EDGE_CURVE('E977',#578,#775,#783,.T.);
#785=ORIENTED_EDGE('',*,*,#784,.T.);
#786=EDGE_LOOP('',(#777,#778,#779,#785));
#787=FACE_BOUND('',#786,.T.);
#788=ADVANCED_FACE('F1763',(#787),#769,.T.);
#789=CARTESIAN_POINT('',(-41.,48.,-24.));
#790=DIRECTION('',(0.,-1.,0.));
#791=DIRECTION('',(1.,0.,0.));
#792=AXIS2_PLACEMENT_3D('',#789,#790,#791);
#793=PLANE('',#792);
#794=DIRECTION('',(1.,0.,0.));
#795=VECTOR('',#794,1.);
#796=CARTESIAN_POINT('',(-41.,48.,-4.));
#797=LINE('',#796,#795);
#798=CARTESIAN_POINT('',(41.,48.,-4.));
#799=VERTEX_POINT('',#798);
#800=EDGE_CURVE('E964',#775,#799,#797,.T.);
#801=ORIENTED_EDGE('',*,*,#800,.F.);
#802=ORIENTED_EDGE('',*,*,#784,.F.);
#803=ORIENTED_EDGE('',*,*,#579,.T.);
#804=DIRECTION('',(0.,0.,1.));
#805=VECTOR('',#804,1.);
#806=CARTESIAN_POINT('',(41.,48.,-24.));
#807=LINE('',#806,#805);
#808=EDGE_CURVE('E975',#570,#799,#807,.T.);
#809=ORIENTED_EDGE('',*,*,#808,.T.);
#810=EDGE_LOOP('',(#801,#802,#803,#809));
#811=FACE_BOUND('',#810,.T.);
#812=ADVANCED_FACE('F1755',(#811),#793,.T.);
#813=CARTESIAN_POINT('',(41.,48.,-24.));
#814=DIRECTION('',(-0.707106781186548,-0.707106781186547,0.));
#815=DIRECTION('',(0.707106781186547,-0.707106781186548,0.));
#816=AXIS2_PLACEMENT_3D('',#813,#814,#815);
#817=PLANE('',#816);
#818=DIRECTION('',(0.707106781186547,-0.707106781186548,0.));
#819=VECTOR('',#818,1.);
#820=CARTESIAN_POINT('',(41.,48.,-4.));
#821=LINE('',#820,#819);
#822=CARTESIAN_POINT('',(48.,41.,-4.));
#823=VERTEX_POINT('',#822);
#824=EDGE_CURVE('E967',#799,#823,#821,.T.);
#825=ORIENTED_EDGE('',*,*,#824,.F.);
#826=ORIENTED_EDGE('',*,*,#808,.F.);
#827=ORIENTED_EDGE('',*,*,#571,.T.);
#828=DIRECTION('',(0.,0.,1.));
#829=VECTOR('',#828,1.);
#830=CARTESIAN_POINT('',(48.,41.,-24.));
#831=LINE('',#830,#829);
#832=EDGE_CURVE('E973',#562,#823,#831,.T.);
#833=ORIENTED_EDGE('',*,*,#832,.T.);
#834=EDGE_LOOP('',(#825,#826,#827,#833));
#835=FACE_BOUND('',#834,.T.);
#836=ADVANCED_FACE('F1746',(#835),#817,.T.);
#837=CARTESIAN_POINT('',(48.,41.,-24.));
#838=DIRECTION('',(-1.,0.,0.));
#839=DIRECTION('',(0.,-1.,0.));
#840=AXIS2_PLACEMENT_3D('',#837,#838,#839);
#841=PLANE('',#840);
#842=CARTESIAN_POINT('',(48.,-23.,-12.));
#843=DIRECTION('',(-1.,0.,0.));
#844=DIRECTION('',(0.,-1.,0.));
#845=AXIS2_PLACEMENT_3D('',#842,#843,#844);
#846=CIRCLE('',#845,1.6);
#847=CARTESIAN_POINT('',(48.,-21.4,-12.));
#848=VERTEX_POINT('',#847);
#849=EDGE_CURVE('E37',#848,#848,#846,.F.);
#850=ORIENTED_EDGE('',*,*,#849,.T.);
#851=EDGE_LOOP('',(#850));
#852=FACE_BOUND('',#851,.T.);
#853=CARTESIAN_POINT('',(48.,23.,-12.));
#854=DIRECTION('',(-1.,0.,0.));
#855=DIRECTION('',(0.,-1.,0.));
#856=AXIS2_PLACEMENT_3D('',#853,#854,#855);
#857=CIRCLE('',#856,1.6);
#858=CARTESIAN_POINT('',(48.,24.6,-12.));
#859=VERTEX_POINT('',#858);
#860=EDGE_CURVE('E505',#859,#859,#857,.F.);
#861=ORIENTED_EDGE('',*,*,#860,.T.);
#862=EDGE_LOOP('',(#861));
#863=FACE_BOUND('',#862,.T.);
#864=DIRECTION('',(0.,-1.,0.));
#865=VECTOR('',#864,1.);
#866=CARTESIAN_POINT('',(48.,41.,-4.));
#867=LINE('',#866,#865);
#868=EDGE_CURVE('E932',#823,#616,#867,.T.);
#869=ORIENTED_EDGE('',*,*,#868,.F.);
#870=ORIENTED_EDGE('',*,*,#832,.F.);
#871=ORIENTED_EDGE('',*,*,#563,.T.);
#872=ORIENTED_EDGE('',*,*,#625,.T.);
#873=EDGE_LOOP('',(#869,#870,#871,#872));
#874=FACE_BOUND('',#873,.T.);
#875=ADVANCED_FACE('F1739',(#852,#863,#874),#841,.T.);
#876=CARTESIAN_POINT('',(0.,0.,-4.));
#877=DIRECTION('',(0.,0.,1.));
#878=DIRECTION('',(1.,0.,0.));
#879=AXIS2_PLACEMENT_3D('',#876,#877,#878);
#880=PLANE('',#879);
#881=CARTESIAN_POINT('',(-34.5,-41.,-4.));
#882=DIRECTION('',(0.,0.,1.));
#883=DIRECTION('',(-1.,0.,0.));
#884=AXIS2_PLACEMENT_3D('',#881,#882,#883);
#885=CIRCLE('',#884,4.5);
#886=CARTESIAN_POINT('',(-39.,-41.,-4.));
#887=VERTEX_POINT('',#886);
#888=EDGE_CURVE('E587',#887,#887,#885,.T.);
#889=ORIENTED_EDGE('',*,*,#888,.T.);
#890=EDGE_LOOP('',(#889));
#891=FACE_BOUND('',#890,.T.);
#892=CARTESIAN_POINT('',(34.4999999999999,-41.,-4.));
#893=DIRECTION('',(0.,0.,1.));
#894=DIRECTION('',(1.,0.,0.));
#895=AXIS2_PLACEMENT_3D('',#892,#893,#894);
#896=CIRCLE('',#895,4.5);
#897=CARTESIAN_POINT('',(38.9999999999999,-41.,-4.));
#898=VERTEX_POINT('',#897);
#899=EDGE_CURVE('E665',#898,#898,#896,.T.);
#900=ORIENTED_EDGE('',*,*,#899,.T.);
#901=EDGE_LOOP('',(#900));
#902=FACE_BOUND('',#901,.T.);
#903=CARTESIAN_POINT('',(34.5,41.,-4.));
#904=DIRECTION('',(0.,0.,1.));
#905=DIRECTION('',(-1.,0.,0.));
#906=AXIS2_PLACEMENT_3D('',#903,#904,#905);
#907=CIRCLE('',#906,4.5);
#908=CARTESIAN_POINT('',(29.9999999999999,41.,-4.));
#909=VERTEX_POINT('',#908);
#910=EDGE_CURVE('E743',#909,#909,#907,.T.);
#911=ORIENTED_EDGE('',*,*,#910,.T.);
#912=EDGE_LOOP('',(#911));
#913=FACE_BOUND('',#912,.T.);
#914=CARTESIAN_POINT('',(-34.5,41.,-4.));
#915=DIRECTION('',(0.,0.,1.));
#916=DIRECTION('',(1.,0.,0.));
#917=AXIS2_PLACEMENT_3D('',#914,#915,#916);
#918=CIRCLE('',#917,4.5);
#919=CARTESIAN_POINT('',(-30.,41.,-4.));
#920=VERTEX_POINT('',#919);
#921=EDGE_CURVE('E821',#920,#920,#918,.T.);
#922=ORIENTED_EDGE('',*,*,#921,.T.);
#923=EDGE_LOOP('',(#922));
#924=FACE_BOUND('',#923,.T.);
#925=DIRECTION('',(-1.,0.,0.));
#926=VECTOR('',#925,1.);
#927=CARTESIAN_POINT('',(0.,43.8,-4.));
#928=LINE('',#927,#926);
#929=CARTESIAN_POINT('',(6.5,43.8,-4.));
#930=VERTEX_POINT('',#929);
#931=CARTESIAN_POINT('',(-6.5,43.8,-4.));
#932=VERTEX_POINT('',#931);
#933=EDGE_CURVE('E1065',#930,#932,#928,.T.);
#934=ORIENTED_EDGE('',*,*,#933,.T.);
#935=DIRECTION('',(0.,-1.,0.));
#936=VECTOR('',#935,1.);
#937=CARTESIAN_POINT('',(-6.5,0.,-4.));
#938=LINE('',#937,#936);
#939=CARTESIAN_POINT('',(-6.5,33.5,-4.));
#940=VERTEX_POINT('',#939);
#941=EDGE_CURVE('E430',#932,#940,#938,.T.);
#942=ORIENTED_EDGE('',*,*,#941,.T.);
#943=DIRECTION('',(1.,0.,0.));
#944=VECTOR('',#943,1.);
#945=CARTESIAN_POINT('',(0.,33.5,-4.));
#946=LINE('',#945,#944);
#947=CARTESIAN_POINT('',(6.5,33.5,-4.));
#948=VERTEX_POINT('',#947);
#949=EDGE_CURVE('E1055',#940,#948,#946,.T.);
#950=ORIENTED_EDGE('',*,*,#949,.T.);
#951=DIRECTION('',(0.,1.,0.));
#952=VECTOR('',#951,1.);
#953=CARTESIAN_POINT('',(6.50000000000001,0.,-4.));
#954=LINE('',#953,#952);
#955=EDGE_CURVE('E1062',#948,#930,#954,.T.);
#956=ORIENTED_EDGE('',*,*,#955,.T.);
#957=EDGE_LOOP('',(#934,#942,#950,#956));
#958=FACE_BOUND('',#957,.T.);
#959=CARTESIAN_POINT('',(0.,0.,-4.));
#960=DIRECTION('',(0.,0.,1.));
#961=DIRECTION('',(1.,0.,0.));
#962=AXIS2_PLACEMENT_3D('',#959,#960,#961);
#963=CIRCLE('',#962,5.);
#964=CARTESIAN_POINT('',(5.,0.,-4.));
#965=VERTEX_POINT('',#964);
#966=EDGE_CURVE('E919',#965,#965,#963,.T.);
#967=ORIENTED_EDGE('',*,*,#966,.T.);
#968=EDGE_LOOP('',(#967));
#969=FACE_BOUND('',#968,.T.);
#970=CARTESIAN_POINT('',(-16.086679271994,16.086679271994,-4.));
#971=DIRECTION('',(0.,0.,1.));
#972=DIRECTION('',(1.,0.,0.));
#973=AXIS2_PLACEMENT_3D('',#970,#971,#972);
#974=CIRCLE('',#973,1.25);
#975=CARTESIAN_POINT('',(-14.836679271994,16.086679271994,-4.));
#976=VERTEX_POINT('',#975);
#977=EDGE_CURVE('E1043',#976,#976,#974,.T.);
#978=ORIENTED_EDGE('',*,*,#977,.T.);
#979=EDGE_LOOP('',(#978));
#980=FACE_BOUND('',#979,.T.);
#981=DIRECTION('',(-1.,0.,0.));
#982=VECTOR('',#981,1.);
#983=CARTESIAN_POINT('',(0.,25.8,-4.));
#984=LINE('',#983,#982);
#985=CARTESIAN_POINT('',(6.49999999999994,25.8,-4.));
#986=VERTEX_POINT('',#985);
#987=CARTESIAN_POINT('',(-6.49999999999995,25.8,-4.));
#988=VERTEX_POINT('',#987);
#989=EDGE_CURVE('E1049',#986,#988,#984,.T.);
#990=ORIENTED_EDGE('',*,*,#989,.T.);
#991=DIRECTION('',(0.,-1.,0.));
#992=VECTOR('',#991,1.);
#993=CARTESIAN_POINT('',(-6.49999999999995,0.,-4.));
#994=LINE('',#993,#992);
#995=CARTESIAN_POINT('',(-6.49999999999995,15.5,-4.));
#996=VERTEX_POINT('',#995);
#997=EDGE_CURVE('E1052',#988,#996,#994,.T.);
#998=ORIENTED_EDGE('',*,*,#997,.T.);
#999=DIRECTION('',(1.,0.,0.));
#1000=VECTOR('',#999,1.);
#1001=CARTESIAN_POINT('',(0.,15.5,-4.));
#1002=LINE('',#1001,#1000);
#1003=CARTESIAN_POINT('',(6.49999999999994,15.5,-4.));
#1004=VERTEX_POINT('',#1003);
#1005=EDGE_CURVE('E1012',#996,#1004,#1002,.T.);
#1006=ORIENTED_EDGE('',*,*,#1005,.T.);
#1007=DIRECTION('',(0.,1.,0.));
#1008=VECTOR('',#1007,1.);
#1009=CARTESIAN_POINT('',(6.49999999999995,0.,-4.));
#1010=LINE('',#1009,#1008);
#1011=EDGE_CURVE('E1046',#1004,#986,#1010,.T.);
#1012=ORIENTED_EDGE('',*,*,#1011,.T.);
#1013=EDGE_LOOP('',(#990,#998,#1006,#1012));
#1014=FACE_BOUND('',#1013,.T.);
#1015=CARTESIAN_POINT('',(32.5,24.9,-4.));
#1016=DIRECTION('',(0.,0.,1.));
#1017=DIRECTION('',(1.,0.,0.));
#1018=AXIS2_PLACEMENT_3D('',#1015,#1016,#1017);
#1019=CIRCLE('',#1018,1.25);
#1020=CARTESIAN_POINT('',(33.75,24.9,-4.));
#1021=VERTEX_POINT('',#1020);
#1022=EDGE_CURVE('E1040',#1021,#1021,#1019,.T.);
#1023=ORIENTED_EDGE('',*,*,#1022,.T.);
#1024=EDGE_LOOP('',(#1023));
#1025=FACE_BOUND('',#1024,.T.);
#1026=CARTESIAN_POINT('',(-32.5,24.9,-4.));
#1027=DIRECTION('',(0.,0.,1.));
#1028=DIRECTION('',(1.,0.,0.));
#1029=AXIS2_PLACEMENT_3D('',#1026,#1027,#1028);
#1030=CIRCLE('',#1029,1.25);
#1031=CARTESIAN_POINT('',(-31.25,24.9,-4.));
#1032=VERTEX_POINT('',#1031);
#1033=EDGE_CURVE('E1037',#1032,#1032,#1030,.T.);
#1034=ORIENTED_EDGE('',*,*,#1033,.T.);
#1035=EDGE_LOOP('',(#1034));
#1036=FACE_BOUND('',#1035,.T.);
#1037=CARTESIAN_POINT('',(-32.5,-24.9,-4.));
#1038=DIRECTION('',(0.,0.,1.));
#1039=DIRECTION('',(1.,0.,0.));
#1040=AXIS2_PLACEMENT_3D('',#1037,#1038,#1039);
#1041=CIRCLE('',#1040,1.25);
#1042=CARTESIAN_POINT('',(-31.25,-24.9,-4.));
#1043=VERTEX_POINT('',#1042);
#1044=EDGE_CURVE('E1034',#1043,#1043,#1041,.T.);
#1045=ORIENTED_EDGE('',*,*,#1044,.T.);
#1046=EDGE_LOOP('',(#1045));
#1047=FACE_BOUND('',#1046,.T.);
#1048=CARTESIAN_POINT('',(16.086679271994,16.086679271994,-4.));
#1049=DIRECTION('',(0.,0.,1.));
#1050=DIRECTION('',(1.,0.,0.));
#1051=AXIS2_PLACEMENT_3D('',#1048,#1049,#1050);
#1052=CIRCLE('',#1051,1.25);
#1053=CARTESIAN_POINT('',(17.336679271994,16.086679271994,-4.));
#1054=VERTEX_POINT('',#1053);
#1055=EDGE_CURVE('E1031',#1054,#1054,#1052,.T.);
#1056=ORIENTED_EDGE('',*,*,#1055,.T.);
#1057=EDGE_LOOP('',(#1056));
#1058=FACE_BOUND('',#1057,.T.);
#1059=CARTESIAN_POINT('',(-16.086679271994,-16.086679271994,-4.));
#1060=DIRECTION('',(0.,0.,1.));
#1061=DIRECTION('',(1.,0.,0.));
#1062=AXIS2_PLACEMENT_3D('',#1059,#1060,#1061);
#1063=CIRCLE('',#1062,1.25);
#1064=CARTESIAN_POINT('',(-14.836679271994,-16.086679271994,-4.));
#1065=VERTEX_POINT('',#1064);
#1066=EDGE_CURVE('E1028',#1065,#1065,#1063,.T.);
#1067=ORIENTED_EDGE('',*,*,#1066,.T.);
#1068=EDGE_LOOP('',(#1067));
#1069=FACE_BOUND('',#1068,.T.);
#1070=CARTESIAN_POINT('',(16.086679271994,-16.086679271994,-4.));
#1071=DIRECTION('',(0.,0.,1.));
#1072=DIRECTION('',(1.,0.,0.));
#1073=AXIS2_PLACEMENT_3D('',#1070,#1071,#1072);
#1074=CIRCLE('',#1073,1.25);
#1075=CARTESIAN_POINT('',(17.336679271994,-16.086679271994,-4.));
#1076=VERTEX_POINT('',#1075);
#1077=EDGE_CURVE('E1025',#1076,#1076,#1074,.T.);
#1078=ORIENTED_EDGE('',*,*,#1077,.T.);
#1079=EDGE_LOOP('',(#1078));
#1080=FACE_BOUND('',#1079,.T.);
#1081=CARTESIAN_POINT('',(32.5,-24.9,-4.));
#1082=DIRECTION('',(0.,0.,1.));
#1083=DIRECTION('',(1.,0.,0.));
#1084=AXIS2_PLACEMENT_3D('',#1081,#1082,#1083);
#1085=CIRCLE('',#1084,1.25);
#1086=CARTESIAN_POINT('',(33.75,-24.9,-4.));
#1087=VERTEX_POINT('',#1086);
#1088=EDGE_CURVE('E863',#1087,#1087,#1085,.T.);
#1089=ORIENTED_EDGE('',*,*,#1088,.T.);
#1090=EDGE_LOOP('',(#1089));
#1091=FACE_BOUND('',#1090,.T.);
#1092=ORIENTED_EDGE('',*,*,#868,.T.);
#1093=ORIENTED_EDGE('',*,*,#619,.T.);
#1094=ORIENTED_EDGE('',*,*,#682,.T.);
#1095=ORIENTED_EDGE('',*,*,#706,.T.);
#1096=ORIENTED_EDGE('',*,*,#752,.T.);
#1097=ORIENTED_EDGE('',*,*,#776,.T.);
#1098=ORIENTED_EDGE('',*,*,#800,.T.);
#1099=ORIENTED_EDGE('',*,*,#824,.T.);
#1100=EDGE_LOOP('',(#1092,#1093,#1094,#1095,#1096,#1097,#1098,#1099));
#1101=FACE_BOUND('',#1100,.T.);
#1102=ADVANCED_FACE('F1224',(#891,#902,#913,#924,#958,#969,#980,#1014,#1025,#1036,#1047,#1058,
#1069,#1080,#1091,#1101),#880,.F.);
#1103=CARTESIAN_POINT('',(-48.,48.,-50.));
#1104=DIRECTION('',(0.,0.,1.));
#1105=DIRECTION('',(1.,0.,0.));
#1106=AXIS2_PLACEMENT_3D('',#1103,#1104,#1105);
#1107=CYLINDRICAL_SURFACE('',#1106,1.55);
#1108=ORIENTED_EDGE('',*,*,#505,.T.);
#1109=EDGE_LOOP('',(#1108));
#1110=FACE_BOUND('',#1109,.T.);
#1111=ORIENTED_EDGE('',*,*,#425,.T.);
#1112=EDGE_LOOP('',(#1111));
#1113=FACE_BOUND('',#1112,.T.);
#1114=ADVANCED_FACE('F1724',(#1110,#1113),#1107,.F.);
#1115=CARTESIAN_POINT('',(48.,-48.,-50.));
#1116=DIRECTION('',(0.,0.,1.));
#1117=DIRECTION('',(1.,0.,0.));
#1118=AXIS2_PLACEMENT_3D('',#1115,#1116,#1117);
#1119=CYLINDRICAL_SURFACE('',#1118,1.55);
#1120=ORIENTED_EDGE('',*,*,#494,.T.);
#1121=EDGE_LOOP('',(#1120));
#1122=FACE_BOUND('',#1121,.T.);
#1123=ORIENTED_EDGE('',*,*,#414,.T.);
#1124=EDGE_LOOP('',(#1123));
#1125=FACE_BOUND('',#1124,.T.);
#1126=ADVANCED_FACE('F1716',(#1122,#1125),#1119,.F.);
#1127=CARTESIAN_POINT('',(-48.,-48.,-50.));
#1128=DIRECTION('',(0.,0.,1.));
#1129=DIRECTION('',(1.,0.,0.));
#1130=AXIS2_PLACEMENT_3D('',#1127,#1128,#1129);
#1131=CYLINDRICAL_SURFACE('',#1130,1.55);
#1132=ORIENTED_EDGE('',*,*,#483,.T.);
#1133=EDGE_LOOP('',(#1132));
#1134=FACE_BOUND('',#1133,.T.);
#1135=ORIENTED_EDGE('',*,*,#403,.T.);
#1136=EDGE_LOOP('',(#1135));
#1137=FACE_BOUND('',#1136,.T.);
#1138=ADVANCED_FACE('F1708',(#1134,#1137),#1131,.F.);
#1139=CARTESIAN_POINT('',(48.,48.,-50.));
#1140=DIRECTION('',(0.,0.,1.));
#1141=DIRECTION('',(1.,0.,0.));
#1142=AXIS2_PLACEMENT_3D('',#1139,#1140,#1141);
#1143=CYLINDRICAL_SURFACE('',#1142,1.55);
#1144=ORIENTED_EDGE('',*,*,#472,.T.);
#1145=EDGE_LOOP('',(#1144));
#1146=FACE_BOUND('',#1145,.T.);
#1147=ORIENTED_EDGE('',*,*,#392,.T.);
#1148=EDGE_LOOP('',(#1147));
#1149=FACE_BOUND('',#1148,.T.);
#1150=ADVANCED_FACE('F1700',(#1146,#1149),#1143,.F.);
#1151=CARTESIAN_POINT('',(32.5,-24.9,-10.));
#1152=DIRECTION('',(0.,0.,1.));
#1153=DIRECTION('',(1.,0.,0.));
#1154=AXIS2_PLACEMENT_3D('',#1151,#1152,#1153);
#1155=CYLINDRICAL_SURFACE('',#1154,1.25);
#1156=ORIENTED_EDGE('',*,*,#381,.T.);
#1157=EDGE_LOOP('',(#1156));
#1158=FACE_BOUND('',#1157,.T.);
#1159=ORIENTED_EDGE('',*,*,#1088,.F.);
#1160=EDGE_LOOP('',(#1159));
#1161=FACE_BOUND('',#1160,.T.);
#1162=ADVANCED_FACE('F1692',(#1158,#1161),#1155,.F.);
#1163=CARTESIAN_POINT('',(16.086679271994,-16.086679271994,-10.));
#1164=DIRECTION('',(0.,0.,1.));
#1165=DIRECTION('',(1.,0.,0.));
#1166=AXIS2_PLACEMENT_3D('',#1163,#1164,#1165);
#1167=CYLINDRICAL_SURFACE('',#1166,1.25);
#1168=ORIENTED_EDGE('',*,*,#370,.T.);
#1169=EDGE_LOOP('',(#1168));
#1170=FACE_BOUND('',#1169,.T.);
#1171=ORIENTED_EDGE('',*,*,#1077,.F.);
#1172=EDGE_LOOP('',(#1171));
#1173=FACE_BOUND('',#1172,.T.);
#1174=ADVANCED_FACE('F1684',(#1170,#1173),#1167,.F.);
#1175=CARTESIAN_POINT('',(-16.086679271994,-16.086679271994,-10.));
#1176=DIRECTION('',(0.,0.,1.));
#1177=DIRECTION('',(1.,0.,0.));
#1178=AXIS2_PLACEMENT_3D('',#1175,#1176,#1177);
#1179=CYLINDRICAL_SURFACE('',#1178,1.25);
#1180=ORIENTED_EDGE('',*,*,#359,.T.);
#1181=EDGE_LOOP('',(#1180));
#1182=FACE_BOUND('',#1181,.T.);
#1183=ORIENTED_EDGE('',*,*,#1066,.F.);
#1184=EDGE_LOOP('',(#1183));
#1185=FACE_BOUND('',#1184,.T.);
#1186=ADVANCED_FACE('F1676',(#1182,#1185),#1179,.F.);
#1187=CARTESIAN_POINT('',(16.086679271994,16.086679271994,-10.));
#1188=DIRECTION('',(0.,0.,1.));
#1189=DIRECTION('',(1.,0.,0.));
#1190=AXIS2_PLACEMENT_3D('',#1187,#1188,#1189);
#1191=CYLINDRICAL_SURFACE('',#1190,1.25);
#1192=ORIENTED_EDGE('',*,*,#348,.T.);
#1193=EDGE_LOOP('',(#1192));
#1194=FACE_BOUND('',#1193,.T.);
#1195=ORIENTED_EDGE('',*,*,#1055,.F.);
#1196=EDGE_LOOP('',(#1195));
#1197=FACE_BOUND('',#1196,.T.);
#1198=ADVANCED_FACE('F1668',(#1194,#1197),#1191,.F.);
#1199=CARTESIAN_POINT('',(-32.5,-24.9,-10.));
#1200=DIRECTION('',(0.,0.,1.));
#1201=DIRECTION('',(1.,0.,0.));
#1202=AXIS2_PLACEMENT_3D('',#1199,#1200,#1201);
#1203=CYLINDRICAL_SURFACE('',#1202,1.25);
#1204=ORIENTED_EDGE('',*,*,#337,.T.);
#1205=EDGE_LOOP('',(#1204));
#1206=FACE_BOUND('',#1205,.T.);
#1207=ORIENTED_EDGE('',*,*,#1044,.F.);
#1208=EDGE_LOOP('',(#1207));
#1209=FACE_BOUND('',#1208,.T.);
#1210=ADVANCED_FACE('F1660',(#1206,#1209),#1203,.F.);
#1211=CARTESIAN_POINT('',(-32.5,24.9,-10.));
#1212=DIRECTION('',(0.,0.,1.));
#1213=DIRECTION('',(1.,0.,0.));
#1214=AXIS2_PLACEMENT_3D('',#1211,#1212,#1213);
#1215=CYLINDRICAL_SURFACE('',#1214,1.25);
#1216=ORIENTED_EDGE('',*,*,#326,.T.);
#1217=EDGE_LOOP('',(#1216));
#1218=FACE_BOUND('',#1217,.T.);
#1219=ORIENTED_EDGE('',*,*,#1033,.F.);
#1220=EDGE_LOOP('',(#1219));
#1221=FACE_BOUND('',#1220,.T.);
#1222=ADVANCED_FACE('F1652',(#1218,#1221),#1215,.F.);
#1223=CARTESIAN_POINT('',(32.5,24.9,-10.));
#1224=DIRECTION('',(0.,0.,1.));
#1225=DIRECTION('',(1.,0.,0.));
#1226=AXIS2_PLACEMENT_3D('',#1223,#1224,#1225);
#1227=CYLINDRICAL_SURFACE('',#1226,1.25);
#1228=ORIENTED_EDGE('',*,*,#315,.T.);
#1229=EDGE_LOOP('',(#1228));
#1230=FACE_BOUND('',#1229,.T.);
#1231=ORIENTED_EDGE('',*,*,#1022,.F.);
#1232=EDGE_LOOP('',(#1231));
#1233=FACE_BOUND('',#1232,.T.);
#1234=ADVANCED_FACE('F1644',(#1230,#1233),#1227,.F.);
#1235=CARTESIAN_POINT('',(-6.49999999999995,25.8,-10.));
#1236=DIRECTION('',(-1.,0.,0.));
#1237=DIRECTION('',(0.,-1.,0.));
#1238=AXIS2_PLACEMENT_3D('',#1235,#1236,#1237);
#1239=PLANE('',#1238);
#1240=DIRECTION('',(0.,0.,1.));
#1241=VECTOR('',#1240,1.);
#1242=CARTESIAN_POINT('',(-6.49999999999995,25.8,-10.));
#1243=LINE('',#1242,#1241);
#1244=EDGE_CURVE('E851',#988,#279,#1243,.T.);
#1245=ORIENTED_EDGE('',*,*,#1244,.T.);
#1246=ORIENTED_EDGE('',*,*,#282,.T.);
#1247=DIRECTION('',(0.,0.,1.));
#1248=VECTOR('',#1247,1.);
#1249=CARTESIAN_POINT('',(-6.49999999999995,15.5,-10.));
#1250=LINE('',#1249,#1248);
#1251=EDGE_CURVE('E900',#996,#281,#1250,.T.);
#1252=ORIENTED_EDGE('',*,*,#1251,.F.);
#1253=ORIENTED_EDGE('',*,*,#997,.F.);
#1254=EDGE_LOOP('',(#1245,#1246,#1252,#1253));
#1255=FACE_BOUND('',#1254,.T.);
#1256=ADVANCED_FACE('F1636',(#1255),#1239,.F.);
#1257=CARTESIAN_POINT('',(-6.49999999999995,25.8,-10.));
#1258=DIRECTION('',(0.,1.,0.));
#1259=DIRECTION('',(0.,0.,1.));
#1260=AXIS2_PLACEMENT_3D('',#1257,#1258,#1259);
#1261=PLANE('',#1260);
#1262=DIRECTION('',(0.,0.,1.));
#1263=VECTOR('',#1262,1.);
#1264=CARTESIAN_POINT('',(6.49999999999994,25.8,-10.));
#1265=LINE('',#1264,#1263);
#1266=EDGE_CURVE('E902',#986,#289,#1265,.T.);
#1267=ORIENTED_EDGE('',*,*,#1266,.T.);
#1268=ORIENTED_EDGE('',*,*,#290,.T.);
#1269=ORIENTED_EDGE('',*,*,#1244,.F.);
#1270=ORIENTED_EDGE('',*,*,#989,.F.);
#1271=EDGE_LOOP('',(#1267,#1268,#1269,#1270));
#1272=FACE_BOUND('',#1271,.T.);
#1273=ADVANCED_FACE('F1628',(#1272),#1261,.F.);
#1274=CARTESIAN_POINT('',(6.49999999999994,25.8,-10.));
#1275=DIRECTION('',(1.,0.,0.));
#1276=DIRECTION('',(0.,1.,0.));
#1277=AXIS2_PLACEMENT_3D('',#1274,#1275,#1276);
#1278=PLANE('',#1277);
#1279=DIRECTION('',(0.,0.,1.));
#1280=VECTOR('',#1279,1.);
#1281=CARTESIAN_POINT('',(6.49999999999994,15.5,-10.));
#1282=LINE('',#1281,#1280);
#1283=EDGE_CURVE('E904',#1004,#297,#1282,.T.);
#1284=ORIENTED_EDGE('',*,*,#1283,.T.);
#1285=ORIENTED_EDGE('',*,*,#298,.T.);
#1286=ORIENTED_EDGE('',*,*,#1266,.F.);
#1287=ORIENTED_EDGE('',*,*,#1011,.F.);
#1288=EDGE_LOOP('',(#1284,#1285,#1286,#1287));
#1289=FACE_BOUND('',#1288,.T.);
#1290=ADVANCED_FACE('F1620',(#1289),#1278,.F.);
#1291=CARTESIAN_POINT('',(-6.49999999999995,15.5,-10.));
#1292=DIRECTION('',(0.,-1.,0.));
#1293=DIRECTION('',(0.,0.,-1.));
#1294=AXIS2_PLACEMENT_3D('',#1291,#1292,#1293);
#1295=PLANE('',#1294);
#1296=ORIENTED_EDGE('',*,*,#1251,.T.);
#1297=ORIENTED_EDGE('',*,*,#304,.T.);
#1298=ORIENTED_EDGE('',*,*,#1283,.F.);
#1299=ORIENTED_EDGE('',*,*,#1005,.F.);
#1300=EDGE_LOOP('',(#1296,#1297,#1298,#1299));
#1301=FACE_BOUND('',#1300,.T.);
#1302=ADVANCED_FACE('F1612',(#1301),#1295,.F.);
#1303=CARTESIAN_POINT('',(-16.086679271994,16.086679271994,-10.));
#1304=DIRECTION('',(0.,0.,1.));
#1305=DIRECTION('',(1.,0.,0.));
#1306=AXIS2_PLACEMENT_3D('',#1303,#1304,#1305);
#1307=CYLINDRICAL_SURFACE('',#1306,1.25);
#1308=ORIENTED_EDGE('',*,*,#270,.T.);
#1309=EDGE_LOOP('',(#1308));
#1310=FACE_BOUND('',#1309,.T.);
#1311=ORIENTED_EDGE('',*,*,#977,.F.);
#1312=EDGE_LOOP('',(#1311));
#1313=FACE_BOUND('',#1312,.T.);
#1314=ADVANCED_FACE('F1604',(#1310,#1313),#1307,.F.);
#1315=CARTESIAN_POINT('',(0.,0.,-10.));
#1316=DIRECTION('',(0.,0.,1.));
#1317=DIRECTION('',(1.,0.,0.));
#1318=AXIS2_PLACEMENT_3D('',#1315,#1316,#1317);
#1319=CYLINDRICAL_SURFACE('',#1318,5.);
#1320=ORIENTED_EDGE('',*,*,#259,.T.);
#1321=EDGE_LOOP('',(#1320));
#1322=FACE_BOUND('',#1321,.T.);
#1323=ORIENTED_EDGE('',*,*,#966,.F.);
#1324=EDGE_LOOP('',(#1323));
#1325=FACE_BOUND('',#1324,.T.);
#1326=ADVANCED_FACE('F1596',(#1322,#1325),#1319,.F.);
#1327=CARTESIAN_POINT('',(-6.5,43.8,-10.));
#1328=DIRECTION('',(-1.,0.,0.));
#1329=DIRECTION('',(0.,-1.,0.));
#1330=AXIS2_PLACEMENT_3D('',#1327,#1328,#1329);
#1331=PLANE('',#1330);
#1332=DIRECTION('',(0.,0.,1.));
#1333=VECTOR('',#1332,1.);
#1334=CARTESIAN_POINT('',(-6.5,43.8,-10.));
#1335=LINE('',#1334,#1333);
#1336=EDGE_CURVE('E861',#932,#223,#1335,.T.);
#1337=ORIENTED_EDGE('',*,*,#1336,.T.);
#1338=ORIENTED_EDGE('',*,*,#226,.T.);
#1339=DIRECTION('',(0.,0.,1.));
#1340=VECTOR('',#1339,1.);
#1341=CARTESIAN_POINT('',(-6.5,33.5,-10.));
#1342=LINE('',#1341,#1340);
#1343=EDGE_CURVE('E860',#940,#225,#1342,.T.);
#1344=ORIENTED_EDGE('',*,*,#1343,.F.);
#1345=ORIENTED_EDGE('',*,*,#941,.F.);
#1346=EDGE_LOOP('',(#1337,#1338,#1344,#1345));
#1347=FACE_BOUND('',#1346,.T.);
#1348=ADVANCED_FACE('F1588',(#1347),#1331,.F.);
#1349=CARTESIAN_POINT('',(-6.5,43.8,-10.));
#1350=DIRECTION('',(0.,1.,0.));
#1351=DIRECTION('',(0.,0.,1.));
#1352=AXIS2_PLACEMENT_3D('',#1349,#1350,#1351);
#1353=PLANE('',#1352);
#1354=DIRECTION('',(0.,0.,1.));
#1355=VECTOR('',#1354,1.);
#1356=CARTESIAN_POINT('',(6.5,43.8,-10.));
#1357=LINE('',#1356,#1355);
#1358=EDGE_CURVE('E864',#930,#233,#1357,.T.);
#1359=ORIENTED_EDGE('',*,*,#1358,.T.);
#1360=ORIENTED_EDGE('',*,*,#234,.T.);
#1361=ORIENTED_EDGE('',*,*,#1336,.F.);
#1362=ORIENTED_EDGE('',*,*,#933,.F.);
#1363=EDGE_LOOP('',(#1359,#1360,#1361,#1362));
#1364=FACE_BOUND('',#1363,.T.);
#1365=ADVANCED_FACE('F1580',(#1364),#1353,.F.);
#1366=CARTESIAN_POINT('',(6.5,43.8,-10.));
#1367=DIRECTION('',(1.,0.,0.));
#1368=DIRECTION('',(0.,1.,0.));
#1369=AXIS2_PLACEMENT_3D('',#1366,#1367,#1368);
#1370=PLANE('',#1369);
#1371=DIRECTION('',(0.,0.,1.));
#1372=VECTOR('',#1371,1.);
#1373=CARTESIAN_POINT('',(6.5,33.5,-10.));
#1374=LINE('',#1373,#1372);
#1375=EDGE_CURVE('E866',#948,#241,#1374,.T.);
#1376=ORIENTED_EDGE('',*,*,#1375,.T.);
#1377=ORIENTED_EDGE('',*,*,#242,.T.);
#1378=ORIENTED_EDGE('',*,*,#1358,.F.);
#1379=ORIENTED_EDGE('',*,*,#955,.F.);
#1380=EDGE_LOOP('',(#1376,#1377,#1378,#1379));
#1381=FACE_BOUND('',#1380,.T.);
#1382=ADVANCED_FACE('F1572',(#1381),#1370,.F.);
#1383=CARTESIAN_POINT('',(-6.5,33.5,-10.));
#1384=DIRECTION('',(0.,-1.,0.));
#1385=DIRECTION('',(0.,0.,-1.));
#1386=AXIS2_PLACEMENT_3D('',#1383,#1384,#1385);
#1387=PLANE('',#1386);
#1388=ORIENTED_EDGE('',*,*,#1343,.T.);
#1389=ORIENTED_EDGE('',*,*,#248,.T.);
#1390=ORIENTED_EDGE('',*,*,#1375,.F.);
#1391=ORIENTED_EDGE('',*,*,#949,.F.);
#1392=EDGE_LOOP('',(#1388,#1389,#1390,#1391));
#1393=FACE_BOUND('',#1392,.T.);
#1394=ADVANCED_FACE('F1563',(#1393),#1387,.F.);
#1395=CARTESIAN_POINT('',(-34.5,41.,-8.));
#1396=DIRECTION('',(0.,0.,1.));
#1397=DIRECTION('',(1.,0.,0.));
#1398=AXIS2_PLACEMENT_3D('',#1395,#1396,#1397);
#1399=CYLINDRICAL_SURFACE('',#1398,4.5);
#1400=CARTESIAN_POINT('',(-34.5,41.,-8.));
#1401=DIRECTION('',(0.,0.,1.));
#1402=DIRECTION('',(1.,0.,0.));
#1403=AXIS2_PLACEMENT_3D('',#1400,#1401,#1402);
#1404=CIRCLE('',#1403,4.5);
#1405=CARTESIAN_POINT('',(-30.,41.,-8.));
#1406=VERTEX_POINT('',#1405);
#1407=EDGE_CURVE('E842',#1406,#1406,#1404,.T.);
#1408=ORIENTED_EDGE('',*,*,#1407,.T.);
#1409=EDGE_LOOP('',(#1408));
#1410=FACE_BOUND('',#1409,.T.);
#1411=ORIENTED_EDGE('',*,*,#921,.F.);
#1412=EDGE_LOOP('',(#1411));
#1413=FACE_BOUND('',#1412,.T.);
#1414=ADVANCED_FACE('F1555',(#1410,#1413),#1399,.T.);
#1415=CARTESIAN_POINT('',(-34.5,41.,-8.));
#1416=DIRECTION('',(0.,0.,1.));
#1417=DIRECTION('',(1.,0.,0.));
#1418=AXIS2_PLACEMENT_3D('',#1415,#1416,#1417);
#1419=PLANE('',#1418);
#1420=DIRECTION('',(0.,-1.,0.));
#1421=VECTOR('',#1420,1.);
#1422=CARTESIAN_POINT('',(-37.4,42.201219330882,-8.));
#1423=LINE('',#1422,#1421);
#1424=CARTESIAN_POINT('',(-37.4,42.201219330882,-8.));
#1425=VERTEX_POINT('',#1424);
#1426=CARTESIAN_POINT('',(-37.4,39.798780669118,-8.));
#1427=VERTEX_POINT('',#1426);
#1428=EDGE_CURVE('E792',#1425,#1427,#1423,.T.);
#1429=ORIENTED_EDGE('',*,*,#1428,.T.);
#1430=DIRECTION('',(0.707106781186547,-0.707106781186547,0.));
#1431=VECTOR('',#1430,1.);
#1432=CARTESIAN_POINT('',(-37.4,39.798780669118,-8.));
#1433=LINE('',#1432,#1431);
#1434=CARTESIAN_POINT('',(-35.701219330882,38.1,-8.));
#1435=VERTEX_POINT('',#1434);
#1436=EDGE_CURVE('E770',#1427,#1435,#1433,.T.);
#1437=ORIENTED_EDGE('',*,*,#1436,.T.);
#1438=DIRECTION('',(1.,0.,0.));
#1439=VECTOR('',#1438,1.);
#1440=CARTESIAN_POINT('',(-35.701219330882,38.1,-8.));
#1441=LINE('',#1440,#1439);
#1442=CARTESIAN_POINT('',(-33.298780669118,38.1,-8.));
#1443=VERTEX_POINT('',#1442);
#1444=EDGE_CURVE('E773',#1435,#1443,#1441,.T.);
#1445=ORIENTED_EDGE('',*,*,#1444,.T.);
#1446=DIRECTION('',(0.707106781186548,0.707106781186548,0.));
#1447=VECTOR('',#1446,1.);
#1448=CARTESIAN_POINT('',(-33.298780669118,38.1,-8.));
#1449=LINE('',#1448,#1447);
#1450=CARTESIAN_POINT('',(-31.6,39.798780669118,-8.));
#1451=VERTEX_POINT('',#1450);
#1452=EDGE_CURVE('E777',#1443,#1451,#1449,.T.);
#1453=ORIENTED_EDGE('',*,*,#1452,.T.);
#1454=DIRECTION('',(0.,1.,0.));
#1455=VECTOR('',#1454,1.);
#1456=CARTESIAN_POINT('',(-31.6,39.798780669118,-8.));
#1457=LINE('',#1456,#1455);
#1458=CARTESIAN_POINT('',(-31.6,42.201219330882,-8.));
#1459=VERTEX_POINT('',#1458);
#1460=EDGE_CURVE('E780',#1451,#1459,#1457,.T.);
#1461=ORIENTED_EDGE('',*,*,#1460,.T.);
#1462=DIRECTION('',(-0.707106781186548,0.707106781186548,0.));
#1463=VECTOR('',#1462,1.);
#1464=CARTESIAN_POINT('',(-31.6,42.201219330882,-8.));
#1465=LINE('',#1464,#1463);
#1466=CARTESIAN_POINT('',(-33.298780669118,43.9,-8.));
#1467=VERTEX_POINT('',#1466);
#1468=EDGE_CURVE('E783',#1459,#1467,#1465,.T.);
#1469=ORIENTED_EDGE('',*,*,#1468,.T.);
#1470=DIRECTION('',(-1.,0.,0.));
#1471=VECTOR('',#1470,1.);
#1472=CARTESIAN_POINT('',(-33.298780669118,43.9,-8.));
#1473=LINE('',#1472,#1471);
#1474=CARTESIAN_POINT('',(-35.701219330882,43.9,-8.));
#1475=VERTEX_POINT('',#1474);
#1476=EDGE_CURVE('E786',#1467,#1475,#1473,.T.);
#1477=ORIENTED_EDGE('',*,*,#1476,.T.);
#1478=DIRECTION('',(-0.707106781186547,-0.707106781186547,0.));
#1479=VECTOR('',#1478,1.);
#1480=CARTESIAN_POINT('',(-35.701219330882,43.9,-8.));
#1481=LINE('',#1480,#1479);
#1482=EDGE_CURVE('E789',#1475,#1425,#1481,.T.);
#1483=ORIENTED_EDGE('',*,*,#1482,.T.);
#1484=EDGE_LOOP('',(#1429,#1437,#1445,#1453,#1461,#1469,#1477,#1483));
#1485=FACE_BOUND('',#1484,.T.);
#1486=ORIENTED_EDGE('',*,*,#1407,.F.);
#1487=EDGE_LOOP('',(#1486));
#1488=FACE_BOUND('',#1487,.T.);
#1489=ADVANCED_FACE('F1547',(#1485,#1488),#1419,.F.);
#1490=CARTESIAN_POINT('',(-37.4,39.798780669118,-8.));
#1491=DIRECTION('',(-0.707106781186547,-0.707106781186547,0.));
#1492=DIRECTION('',(0.707106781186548,-0.707106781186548,0.));
#1493=AXIS2_PLACEMENT_3D('',#1490,#1491,#1492);
#1494=PLANE('',#1493);
#1495=DIRECTION('',(0.707106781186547,-0.707106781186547,0.));
#1496=VECTOR('',#1495,1.);
#1497=CARTESIAN_POINT('',(-37.4,39.798780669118,-4.));
#1498=LINE('',#1497,#1496);
#1499=CARTESIAN_POINT('',(-37.4,39.798780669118,-4.));
#1500=VERTEX_POINT('',#1499);
#1501=CARTESIAN_POINT('',(-35.701219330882,38.1,-4.));
#1502=VERTEX_POINT('',#1501);
#1503=EDGE_CURVE('E767',#1500,#1502,#1498,.T.);
#1504=ORIENTED_EDGE('',*,*,#1503,.T.);
#1505=DIRECTION('',(0.,0.,1.));
#1506=VECTOR('',#1505,1.);
#1507=CARTESIAN_POINT('',(-35.701219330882,38.1,-8.));
#1508=LINE('',#1507,#1506);
#1509=EDGE_CURVE('E795',#1435,#1502,#1508,.T.);
#1510=ORIENTED_EDGE('',*,*,#1509,.F.);
#1511=ORIENTED_EDGE('',*,*,#1436,.F.);
#1512=DIRECTION('',(0.,0.,1.));
#1513=VECTOR('',#1512,1.);
#1514=CARTESIAN_POINT('',(-37.4,39.798780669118,-8.));
#1515=LINE('',#1514,#1513);
#1516=EDGE_CURVE('E818',#1427,#1500,#1515,.T.);
#1517=ORIENTED_EDGE('',*,*,#1516,.T.);
#1518=EDGE_LOOP('',(#1504,#1510,#1511,#1517));
#1519=FACE_BOUND('',#1518,.T.);
#1520=ADVANCED_FACE('F1539',(#1519),#1494,.F.);
#1521=CARTESIAN_POINT('',(-37.4,42.201219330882,-8.));
#1522=DIRECTION('',(-1.,0.,0.));
#1523=DIRECTION('',(0.,0.,1.));
#1524=AXIS2_PLACEMENT_3D('',#1521,#1522,#1523);
#1525=PLANE('',#1524);
#1526=DIRECTION('',(0.,-1.,0.));
#1527=VECTOR('',#1526,1.);
#1528=CARTESIAN_POINT('',(-37.4,42.201219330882,-4.));
#1529=LINE('',#1528,#1527);
#1530=CARTESIAN_POINT('',(-37.4,42.201219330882,-4.));
#1531=VERTEX_POINT('',#1530);
#1532=EDGE_CURVE('E774',#1531,#1500,#1529,.T.);
#1533=ORIENTED_EDGE('',*,*,#1532,.T.);
#1534=ORIENTED_EDGE('',*,*,#1516,.F.);
#1535=ORIENTED_EDGE('',*,*,#1428,.F.);
#1536=DIRECTION('',(0.,0.,1.));
#1537=VECTOR('',#1536,1.);
#1538=CARTESIAN_POINT('',(-37.4,42.201219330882,-8.));
#1539=LINE('',#1538,#1537);
#1540=EDGE_CURVE('E822',#1425,#1531,#1539,.T.);
#1541=ORIENTED_EDGE('',*,*,#1540,.T.);
#1542=EDGE_LOOP('',(#1533,#1534,#1535,#1541));
#1543=FACE_BOUND('',#1542,.T.);
#1544=ADVANCED_FACE('F1531',(#1543),#1525,.F.);
#1545=CARTESIAN_POINT('',(-35.701219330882,43.9,-8.));
#1546=DIRECTION('',(-0.707106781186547,0.707106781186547,0.));
#1547=DIRECTION('',(-0.707106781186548,-0.707106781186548,0.));
#1548=AXIS2_PLACEMENT_3D('',#1545,#1546,#1547);
#1549=PLANE('',#1548);
#1550=DIRECTION('',(-0.707106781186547,-0.707106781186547,0.));
#1551=VECTOR('',#1550,1.);
#1552=CARTESIAN_POINT('',(-35.701219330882,43.9,-4.));
#1553=LINE('',#1552,#1551);
#1554=CARTESIAN_POINT('',(-35.701219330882,43.9,-4.));
#1555=VERTEX_POINT('',#1554);
#1556=EDGE_CURVE('E813',#1555,#1531,#1553,.T.);
#1557=ORIENTED_EDGE('',*,*,#1556,.T.);
#1558=ORIENTED_EDGE('',*,*,#1540,.F.);
#1559=ORIENTED_EDGE('',*,*,#1482,.F.);
#1560=DIRECTION('',(0.,0.,1.));
#1561=VECTOR('',#1560,1.);
#1562=CARTESIAN_POINT('',(-35.701219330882,43.9,-8.));
#1563=LINE('',#1562,#1561);
#1564=EDGE_CURVE('E825',#1475,#1555,#1563,.T.);
#1565=ORIENTED_EDGE('',*,*,#1564,.T.);
#1566=EDGE_LOOP('',(#1557,#1558,#1559,#1565));
#1567=FACE_BOUND('',#1566,.T.);
#1568=ADVANCED_FACE('F1523',(#1567),#1549,.F.);
#1569=CARTESIAN_POINT('',(-33.298780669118,43.9,-8.));
#1570=DIRECTION('',(0.,1.,0.));
#1571=DIRECTION('',(0.,0.,1.));
#1572=AXIS2_PLACEMENT_3D('',#1569,#1570,#1571);
#1573=PLANE('',#1572);
#1574=DIRECTION('',(-1.,0.,0.));
#1575=VECTOR('',#1574,1.);
#1576=CARTESIAN_POINT('',(-33.298780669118,43.9,-4.));
#1577=LINE('',#1576,#1575);
#1578=CARTESIAN_POINT('',(-33.298780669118,43.9,-4.));
#1579=VERTEX_POINT('',#1578);
#1580=EDGE_CURVE('E810',#1579,#1555,#1577,.T.);
#1581=ORIENTED_EDGE('',*,*,#1580,.T.);
#1582=ORIENTED_EDGE('',*,*,#1564,.F.);
#1583=ORIENTED_EDGE('',*,*,#1476,.F.);
#1584=DIRECTION('',(0.,0.,1.));
#1585=VECTOR('',#1584,1.);
#1586=CARTESIAN_POINT('',(-33.298780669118,43.9,-8.));
#1587=LINE('',#1586,#1585);
#1588=EDGE_CURVE('E828',#1467,#1579,#1587,.T.);
#1589=ORIENTED_EDGE('',*,*,#1588,.T.);
#1590=EDGE_LOOP('',(#1581,#1582,#1583,#1589));
#1591=FACE_BOUND('',#1590,.T.);
#1592=ADVANCED_FACE('F1515',(#1591),#1573,.F.);
#1593=CARTESIAN_POINT('',(-31.6,42.201219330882,-8.));
#1594=DIRECTION('',(0.707106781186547,0.707106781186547,0.));
#1595=DIRECTION('',(-0.707106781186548,0.707106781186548,0.));
#1596=AXIS2_PLACEMENT_3D('',#1593,#1594,#1595);
#1597=PLANE('',#1596);
#1598=DIRECTION('',(-0.707106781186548,0.707106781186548,0.));
#1599=VECTOR('',#1598,1.);
#1600=CARTESIAN_POINT('',(-31.6,42.201219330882,-4.));
#1601=LINE('',#1600,#1599);
#1602=CARTESIAN_POINT('',(-31.6,42.201219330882,-4.));
#1603=VERTEX_POINT('',#1602);
#1604=EDGE_CURVE('E807',#1603,#1579,#1601,.T.);
#1605=ORIENTED_EDGE('',*,*,#1604,.T.);
#1606=ORIENTED_EDGE('',*,*,#1588,.F.);
#1607=ORIENTED_EDGE('',*,*,#1468,.F.);
#1608=DIRECTION('',(0.,0.,1.));
#1609=VECTOR('',#1608,1.);
#1610=CARTESIAN_POINT('',(-31.6,42.201219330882,-8.));
#1611=LINE('',#1610,#1609);
#1612=EDGE_CURVE('E831',#1459,#1603,#1611,.T.);
#1613=ORIENTED_EDGE('',*,*,#1612,.T.);
#1614=EDGE_LOOP('',(#1605,#1606,#1607,#1613));
#1615=FACE_BOUND('',#1614,.T.);
#1616=ADVANCED_FACE('F1507',(#1615),#1597,.F.);
#1617=CARTESIAN_POINT('',(-31.6,39.798780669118,-8.));
#1618=DIRECTION('',(1.,0.,0.));
#1619=DIRECTION('',(0.,0.,-1.));
#1620=AXIS2_PLACEMENT_3D('',#1617,#1618,#1619);
#1621=PLANE('',#1620);
#1622=DIRECTION('',(0.,1.,0.));
#1623=VECTOR('',#1622,1.);
#1624=CARTESIAN_POINT('',(-31.6,39.798780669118,-4.));
#1625=LINE('',#1624,#1623);
#1626=CARTESIAN_POINT('',(-31.6,39.798780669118,-4.));
#1627=VERTEX_POINT('',#1626);
#1628=EDGE_CURVE('E804',#1627,#1603,#1625,.T.);
#1629=ORIENTED_EDGE('',*,*,#1628,.T.);
#1630=ORIENTED_EDGE('',*,*,#1612,.F.);
#1631=ORIENTED_EDGE('',*,*,#1460,.F.);
#1632=DIRECTION('',(0.,0.,1.));
#1633=VECTOR('',#1632,1.);
#1634=CARTESIAN_POINT('',(-31.6,39.798780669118,-8.));
#1635=LINE('',#1634,#1633);
#1636=EDGE_CURVE('E834',#1451,#1627,#1635,.T.);
#1637=ORIENTED_EDGE('',*,*,#1636,.T.);
#1638=EDGE_LOOP('',(#1629,#1630,#1631,#1637));
#1639=FACE_BOUND('',#1638,.T.);
#1640=ADVANCED_FACE('F1499',(#1639),#1621,.F.);
#1641=CARTESIAN_POINT('',(-33.298780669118,38.1,-8.));
#1642=DIRECTION('',(0.707106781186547,-0.707106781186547,0.));
#1643=DIRECTION('',(0.707106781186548,0.707106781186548,0.));
#1644=AXIS2_PLACEMENT_3D('',#1641,#1642,#1643);
#1645=PLANE('',#1644);
#1646=DIRECTION('',(0.707106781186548,0.707106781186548,0.));
#1647=VECTOR('',#1646,1.);
#1648=CARTESIAN_POINT('',(-33.298780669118,38.1,-4.));
#1649=LINE('',#1648,#1647);
#1650=CARTESIAN_POINT('',(-33.298780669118,38.1,-4.));
#1651=VERTEX_POINT('',#1650);
#1652=EDGE_CURVE('E801',#1651,#1627,#1649,.T.);
#1653=ORIENTED_EDGE('',*,*,#1652,.T.);
#1654=ORIENTED_EDGE('',*,*,#1636,.F.);
#1655=ORIENTED_EDGE('',*,*,#1452,.F.);
#1656=DIRECTION('',(0.,0.,1.));
#1657=VECTOR('',#1656,1.);
#1658=CARTESIAN_POINT('',(-33.298780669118,38.1,-8.));
#1659=LINE('',#1658,#1657);
#1660=EDGE_CURVE('E837',#1443,#1651,#1659,.T.);
#1661=ORIENTED_EDGE('',*,*,#1660,.T.);
#1662=EDGE_LOOP('',(#1653,#1654,#1655,#1661));
#1663=FACE_BOUND('',#1662,.T.);
#1664=ADVANCED_FACE('F1491',(#1663),#1645,.F.);
#1665=CARTESIAN_POINT('',(-35.701219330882,38.1,-8.));
#1666=DIRECTION('',(0.,-1.,0.));
#1667=DIRECTION('',(0.,0.,-1.));
#1668=AXIS2_PLACEMENT_3D('',#1665,#1666,#1667);
#1669=PLANE('',#1668);
#1670=DIRECTION('',(1.,0.,0.));
#1671=VECTOR('',#1670,1.);
#1672=CARTESIAN_POINT('',(-35.701219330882,38.1,-4.));
#1673=LINE('',#1672,#1671);
#1674=EDGE_CURVE('E798',#1502,#1651,#1673,.T.);
#1675=ORIENTED_EDGE('',*,*,#1674,.T.);
#1676=ORIENTED_EDGE('',*,*,#1660,.F.);
#1677=ORIENTED_EDGE('',*,*,#1444,.F.);
#1678=ORIENTED_EDGE('',*,*,#1509,.T.);
#1679=EDGE_LOOP('',(#1675,#1676,#1677,#1678));
#1680=FACE_BOUND('',#1679,.T.);
#1681=ADVANCED_FACE('F1484',(#1680),#1669,.F.);
#1682=ORIENTED_EDGE('',*,*,#1503,.F.);
#1683=ORIENTED_EDGE('',*,*,#1532,.F.);
#1684=ORIENTED_EDGE('',*,*,#1556,.F.);
#1685=ORIENTED_EDGE('',*,*,#1580,.F.);
#1686=ORIENTED_EDGE('',*,*,#1604,.F.);
#1687=ORIENTED_EDGE('',*,*,#1628,.F.);
#1688=ORIENTED_EDGE('',*,*,#1652,.F.);
#1689=ORIENTED_EDGE('',*,*,#1674,.F.);
#1690=EDGE_LOOP('',(#1682,#1683,#1684,#1685,#1686,#1687,#1688,#1689));
#1691=FACE_BOUND('',#1690,.T.);
#1692=ADVANCED_FACE('F1399',(#1691),#880,.F.);
#1693=CARTESIAN_POINT('',(34.5,41.,-8.));
#1694=DIRECTION('',(0.,0.,1.));
#1695=DIRECTION('',(1.,0.,0.));
#1696=AXIS2_PLACEMENT_3D('',#1693,#1694,#1695);
#1697=CYLINDRICAL_SURFACE('',#1696,4.5);
#1698=CARTESIAN_POINT('',(34.5,41.,-8.));
#1699=DIRECTION('',(0.,0.,1.));
#1700=DIRECTION('',(-1.,0.,0.));
#1701=AXIS2_PLACEMENT_3D('',#1698,#1699,#1700);
#1702=CIRCLE('',#1701,4.5);
#1703=CARTESIAN_POINT('',(29.9999999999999,41.,-8.));
#1704=VERTEX_POINT('',#1703);
#1705=EDGE_CURVE('E764',#1704,#1704,#1702,.T.);
#1706=ORIENTED_EDGE('',*,*,#1705,.T.);
#1707=EDGE_LOOP('',(#1706));
#1708=FACE_BOUND('',#1707,.T.);
#1709=ORIENTED_EDGE('',*,*,#910,.F.);
#1710=EDGE_LOOP('',(#1709));
#1711=FACE_BOUND('',#1710,.T.);
#1712=ADVANCED_FACE('F1469',(#1708,#1711),#1697,.T.);
#1713=CARTESIAN_POINT('',(34.5,41.,-8.));
#1714=DIRECTION('',(0.,0.,-1.));
#1715=DIRECTION('',(-1.,0.,0.));
#1716=AXIS2_PLACEMENT_3D('',#1713,#1714,#1715);
#1717=PLANE('',#1716);
#1718=DIRECTION('',(0.,1.,0.));
#1719=VECTOR('',#1718,1.);
#1720=CARTESIAN_POINT('',(37.3999999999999,42.201219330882,-8.));
#1721=LINE('',#1720,#1719);
#1722=CARTESIAN_POINT('',(37.3999999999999,39.798780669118,-8.));
#1723=VERTEX_POINT('',#1722);
#1724=CARTESIAN_POINT('',(37.3999999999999,42.201219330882,-8.));
#1725=VERTEX_POINT('',#1724);
#1726=EDGE_CURVE('E692',#1723,#1725,#1721,.T.);
#1727=ORIENTED_EDGE('',*,*,#1726,.T.);
#1728=DIRECTION('',(-0.707106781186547,0.707106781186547,0.));
#1729=VECTOR('',#1728,1.);
#1730=CARTESIAN_POINT('',(35.7012193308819,43.9,-8.));
#1731=LINE('',#1730,#1729);
#1732=CARTESIAN_POINT('',(35.7012193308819,43.9,-8.));
#1733=VERTEX_POINT('',#1732);
#1734=EDGE_CURVE('E695',#1725,#1733,#1731,.T.);
#1735=ORIENTED_EDGE('',*,*,#1734,.T.);
#1736=DIRECTION('',(-1.,0.,0.));
#1737=VECTOR('',#1736,1.);
#1738=CARTESIAN_POINT('',(33.298780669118,43.9,-8.));
#1739=LINE('',#1738,#1737);
#1740=CARTESIAN_POINT('',(33.298780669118,43.9,-8.));
#1741=VERTEX_POINT('',#1740);
#1742=EDGE_CURVE('E699',#1733,#1741,#1739,.T.);
#1743=ORIENTED_EDGE('',*,*,#1742,.T.);
#1744=DIRECTION('',(-0.707106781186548,-0.707106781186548,0.));
#1745=VECTOR('',#1744,1.);
#1746=CARTESIAN_POINT('',(31.5999999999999,42.201219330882,-8.));
#1747=LINE('',#1746,#1745);
#1748=CARTESIAN_POINT('',(31.5999999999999,42.201219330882,-8.));
#1749=VERTEX_POINT('',#1748);
#1750=EDGE_CURVE('E702',#1741,#1749,#1747,.T.);
#1751=ORIENTED_EDGE('',*,*,#1750,.T.);
#1752=DIRECTION('',(0.,-1.,0.));
#1753=VECTOR('',#1752,1.);
#1754=CARTESIAN_POINT('',(31.5999999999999,39.798780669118,-8.));
#1755=LINE('',#1754,#1753);
#1756=CARTESIAN_POINT('',(31.5999999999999,39.798780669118,-8.));
#1757=VERTEX_POINT('',#1756);
#1758=EDGE_CURVE('E705',#1749,#1757,#1755,.T.);
#1759=ORIENTED_EDGE('',*,*,#1758,.T.);
#1760=DIRECTION('',(0.707106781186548,-0.707106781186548,0.));
#1761=VECTOR('',#1760,1.);
#1762=CARTESIAN_POINT('',(33.298780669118,38.1,-8.));
#1763=LINE('',#1762,#1761);
#1764=CARTESIAN_POINT('',(33.298780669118,38.1,-8.));
#1765=VERTEX_POINT('',#1764);
#1766=EDGE_CURVE('E708',#1757,#1765,#1763,.T.);
#1767=ORIENTED_EDGE('',*,*,#1766,.T.);
#1768=DIRECTION('',(1.,0.,0.));
#1769=VECTOR('',#1768,1.);
#1770=CARTESIAN_POINT('',(35.7012193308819,38.1,-8.));
#1771=LINE('',#1770,#1769);
#1772=CARTESIAN_POINT('',(35.7012193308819,38.1,-8.));
#1773=VERTEX_POINT('',#1772);
#1774=EDGE_CURVE('E711',#1765,#1773,#1771,.T.);
#1775=ORIENTED_EDGE('',*,*,#1774,.T.);
#1776=DIRECTION('',(0.707106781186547,0.707106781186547,0.));
#1777=VECTOR('',#1776,1.);
#1778=CARTESIAN_POINT('',(37.3999999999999,39.798780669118,-8.));
#1779=LINE('',#1778,#1777);
#1780=EDGE_CURVE('E714',#1773,#1723,#1779,.T.);
#1781=ORIENTED_EDGE('',*,*,#1780,.T.);
#1782=EDGE_LOOP('',(#1727,#1735,#1743,#1751,#1759,#1767,#1775,#1781));
#1783=FACE_BOUND('',#1782,.T.);
#1784=ORIENTED_EDGE('',*,*,#1705,.F.);
#1785=EDGE_LOOP('',(#1784));
#1786=FACE_BOUND('',#1785,.T.);
#1787=ADVANCED_FACE('F1461',(#1783,#1786),#1717,.T.);
#1788=CARTESIAN_POINT('',(37.3999999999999,42.201219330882,-8.));
#1789=DIRECTION('',(1.,0.,0.));
#1790=DIRECTION('',(0.,0.,-1.));
#1791=AXIS2_PLACEMENT_3D('',#1788,#1789,#1790);
#1792=PLANE('',#1791);
#1793=DIRECTION('',(0.,1.,0.));
#1794=VECTOR('',#1793,1.);
#1795=CARTESIAN_POINT('',(37.3999999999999,42.201219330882,-4.));
#1796=LINE('',#1795,#1794);
#1797=CARTESIAN_POINT('',(37.4,39.798780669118,-4.));
#1798=VERTEX_POINT('',#1797);
#1799=CARTESIAN_POINT('',(37.3999999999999,42.201219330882,-4.));
#1800=VERTEX_POINT('',#1799);
#1801=EDGE_CURVE('E689',#1798,#1800,#1796,.T.);
#1802=ORIENTED_EDGE('',*,*,#1801,.T.);
#1803=DIRECTION('',(0.,0.,1.));
#1804=VECTOR('',#1803,1.);
#1805=CARTESIAN_POINT('',(37.3999999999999,42.201219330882,-8.));
#1806=LINE('',#1805,#1804);
#1807=EDGE_CURVE('E717',#1725,#1800,#1806,.T.);
#1808=ORIENTED_EDGE('',*,*,#1807,.F.);
#1809=ORIENTED_EDGE('',*,*,#1726,.F.);
#1810=DIRECTION('',(0.,0.,1.));
#1811=VECTOR('',#1810,1.);
#1812=CARTESIAN_POINT('',(37.3999999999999,39.798780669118,-8.));
#1813=LINE('',#1812,#1811);
#1814=EDGE_CURVE('E740',#1723,#1798,#1813,.T.);
#1815=ORIENTED_EDGE('',*,*,#1814,.T.);
#1816=EDGE_LOOP('',(#1802,#1808,#1809,#1815));
#1817=FACE_BOUND('',#1816,.T.);
#1818=ADVANCED_FACE('F1453',(#1817),#1792,.F.);
#1819=CARTESIAN_POINT('',(37.3999999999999,39.798780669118,-8.));
#1820=DIRECTION('',(0.707106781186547,-0.707106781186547,0.));
#1821=DIRECTION('',(0.707106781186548,0.707106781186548,0.));
#1822=AXIS2_PLACEMENT_3D('',#1819,#1820,#1821);
#1823=PLANE('',#1822);
#1824=DIRECTION('',(0.707106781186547,0.707106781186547,0.));
#1825=VECTOR('',#1824,1.);
#1826=CARTESIAN_POINT('',(37.3999999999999,39.798780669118,-4.));
#1827=LINE('',#1826,#1825);
#1828=CARTESIAN_POINT('',(35.7012193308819,38.1,-4.));
#1829=VERTEX_POINT('',#1828);
#1830=EDGE_CURVE('E696',#1829,#1798,#1827,.T.);
#1831=ORIENTED_EDGE('',*,*,#1830,.T.);
#1832=ORIENTED_EDGE('',*,*,#1814,.F.);
#1833=ORIENTED_EDGE('',*,*,#1780,.F.);
#1834=DIRECTION('',(0.,0.,1.));
#1835=VECTOR('',#1834,1.);
#1836=CARTESIAN_POINT('',(35.7012193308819,38.1,-8.));
#1837=LINE('',#1836,#1835);
#1838=EDGE_CURVE('E744',#1773,#1829,#1837,.T.);
#1839=ORIENTED_EDGE('',*,*,#1838,.T.);
#1840=EDGE_LOOP('',(#1831,#1832,#1833,#1839));
#1841=FACE_BOUND('',#1840,.T.);
#1842=ADVANCED_FACE('F1445',(#1841),#1823,.F.);
#1843=CARTESIAN_POINT('',(35.7012193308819,38.1,-8.));
#1844=DIRECTION('',(0.,-1.,0.));
#1845=DIRECTION('',(0.,0.,-1.));
#1846=AXIS2_PLACEMENT_3D('',#1843,#1844,#1845);
#1847=PLANE('',#1846);
#1848=DIRECTION('',(1.,0.,0.));
#1849=VECTOR('',#1848,1.);
#1850=CARTESIAN_POINT('',(35.7012193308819,38.1,-4.));
#1851=LINE('',#1850,#1849);
#1852=CARTESIAN_POINT('',(33.298780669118,38.1,-4.));
#1853=VERTEX_POINT('',#1852);
#1854=EDGE_CURVE('E735',#1853,#1829,#1851,.T.);
#1855=ORIENTED_EDGE('',*,*,#1854,.T.);
#1856=ORIENTED_EDGE('',*,*,#1838,.F.);
#1857=ORIENTED_EDGE('',*,*,#1774,.F.);
#1858=DIRECTION('',(0.,0.,1.));
#1859=VECTOR('',#1858,1.);
#1860=CARTESIAN_POINT('',(33.298780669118,38.1,-8.));
#1861=LINE('',#1860,#1859);
#1862=EDGE_CURVE('E747',#1765,#1853,#1861,.T.);
#1863=ORIENTED_EDGE('',*,*,#1862,.T.);
#1864=EDGE_LOOP('',(#1855,#1856,#1857,#1863));
#1865=FACE_BOUND('',#1864,.T.);
#1866=ADVANCED_FACE('F1437',(#1865),#1847,.F.);
#1867=CARTESIAN_POINT('',(33.298780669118,38.1,-8.));
#1868=DIRECTION('',(-0.707106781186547,-0.707106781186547,0.));
#1869=DIRECTION('',(0.707106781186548,-0.707106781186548,0.));
#1870=AXIS2_PLACEMENT_3D('',#1867,#1868,#1869);
#1871=PLANE('',#1870);
#1872=DIRECTION('',(0.707106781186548,-0.707106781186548,0.));
#1873=VECTOR('',#1872,1.);
#1874=CARTESIAN_POINT('',(33.298780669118,38.1,-4.));
#1875=LINE('',#1874,#1873);
#1876=CARTESIAN_POINT('',(31.5999999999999,39.798780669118,-4.));
#1877=VERTEX_POINT('',#1876);
#1878=EDGE_CURVE('E732',#1877,#1853,#1875,.T.);
#1879=ORIENTED_EDGE('',*,*,#1878,.T.);
#1880=ORIENTED_EDGE('',*,*,#1862,.F.);
#1881=ORIENTED_EDGE('',*,*,#1766,.F.);
#1882=DIRECTION('',(0.,0.,1.));
#1883=VECTOR('',#1882,1.);
#1884=CARTESIAN_POINT('',(31.5999999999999,39.798780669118,-8.));
#1885=LINE('',#1884,#1883);
#1886=EDGE_CURVE('E750',#1757,#1877,#1885,.T.);
#1887=ORIENTED_EDGE('',*,*,#1886,.T.);
#1888=EDGE_LOOP('',(#1879,#1880,#1881,#1887));
#1889=FACE_BOUND('',#1888,.T.);
#1890=ADVANCED_FACE('F1429',(#1889),#1871,.F.);
#1891=CARTESIAN_POINT('',(31.5999999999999,39.798780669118,-8.));
#1892=DIRECTION('',(-1.,0.,0.));
#1893=DIRECTION('',(0.,0.,1.));
#1894=AXIS2_PLACEMENT_3D('',#1891,#1892,#1893);
#1895=PLANE('',#1894);
#1896=DIRECTION('',(0.,-1.,0.));
#1897=VECTOR('',#1896,1.);
#1898=CARTESIAN_POINT('',(31.5999999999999,39.798780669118,-4.));
#1899=LINE('',#1898,#1897);
#1900=CARTESIAN_POINT('',(31.5999999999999,42.201219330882,-4.));
#1901=VERTEX_POINT('',#1900);
#1902=EDGE_CURVE('E729',#1901,#1877,#1899,.T.);
#1903=ORIENTED_EDGE('',*,*,#1902,.T.);
#1904=ORIENTED_EDGE('',*,*,#1886,.F.);
#1905=ORIENTED_EDGE('',*,*,#1758,.F.);
#1906=DIRECTION('',(0.,0.,1.));
#1907=VECTOR('',#1906,1.);
#1908=CARTESIAN_POINT('',(31.5999999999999,42.201219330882,-8.));
#1909=LINE('',#1908,#1907);
#1910=EDGE_CURVE('E753',#1749,#1901,#1909,.T.);
#1911=ORIENTED_EDGE('',*,*,#1910,.T.);
#1912=EDGE_LOOP('',(#1903,#1904,#1905,#1911));
#1913=FACE_BOUND('',#1912,.T.);
#1914=ADVANCED_FACE('F1421',(#1913),#1895,.F.);
#1915=CARTESIAN_POINT('',(31.5999999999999,42.201219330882,-8.));
#1916=DIRECTION('',(-0.707106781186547,0.707106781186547,0.));
#1917=DIRECTION('',(-0.707106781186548,-0.707106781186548,0.));
#1918=AXIS2_PLACEMENT_3D('',#1915,#1916,#1917);
#1919=PLANE('',#1918);
#1920=DIRECTION('',(-0.707106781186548,-0.707106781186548,0.));
#1921=VECTOR('',#1920,1.);
#1922=CARTESIAN_POINT('',(31.5999999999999,42.201219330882,-4.));
#1923=LINE('',#1922,#1921);
#1924=CARTESIAN_POINT('',(33.298780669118,43.9,-4.));
#1925=VERTEX_POINT('',#1924);
#1926=EDGE_CURVE('E726',#1925,#1901,#1923,.T.);
#1927=ORIENTED_EDGE('',*,*,#1926,.T.);
#1928=ORIENTED_EDGE('',*,*,#1910,.F.);
#1929=ORIENTED_EDGE('',*,*,#1750,.F.);
#1930=DIRECTION('',(0.,0.,1.));
#1931=VECTOR('',#1930,1.);
#1932=CARTESIAN_POINT('',(33.298780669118,43.9,-8.));
#1933=LINE('',#1932,#1931);
#1934=EDGE_CURVE('E756',#1741,#1925,#1933,.T.);
#1935=ORIENTED_EDGE('',*,*,#1934,.T.);
#1936=EDGE_LOOP('',(#1927,#1928,#1929,#1935));
#1937=FACE_BOUND('',#1936,.T.);
#1938=ADVANCED_FACE('F1413',(#1937),#1919,.F.);
#1939=CARTESIAN_POINT('',(33.298780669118,43.9,-8.));
#1940=DIRECTION('',(0.,1.,0.));
#1941=DIRECTION('',(0.,0.,1.));
#1942=AXIS2_PLACEMENT_3D('',#1939,#1940,#1941);
#1943=PLANE('',#1942);
#1944=DIRECTION('',(-1.,0.,0.));
#1945=VECTOR('',#1944,1.);
#1946=CARTESIAN_POINT('',(33.298780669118,43.9,-4.));
#1947=LINE('',#1946,#1945);
#1948=CARTESIAN_POINT('',(35.7012193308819,43.9,-4.));
#1949=VERTEX_POINT('',#1948);
#1950=EDGE_CURVE('E723',#1949,#1925,#1947,.T.);
#1951=ORIENTED_EDGE('',*,*,#1950,.T.);
#1952=ORIENTED_EDGE('',*,*,#1934,.F.);
#1953=ORIENTED_EDGE('',*,*,#1742,.F.);
#1954=DIRECTION('',(0.,0.,1.));
#1955=VECTOR('',#1954,1.);
#1956=CARTESIAN_POINT('',(35.7012193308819,43.9,-8.));
#1957=LINE('',#1956,#1955);
#1958=EDGE_CURVE('E759',#1733,#1949,#1957,.T.);
#1959=ORIENTED_EDGE('',*,*,#1958,.T.);
#1960=EDGE_LOOP('',(#1951,#1952,#1953,#1959));
#1961=FACE_BOUND('',#1960,.T.);
#1962=ADVANCED_FACE('F1405',(#1961),#1943,.F.);
#1963=CARTESIAN_POINT('',(35.7012193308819,43.9,-8.));
#1964=DIRECTION('',(0.707106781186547,0.707106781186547,0.));
#1965=DIRECTION('',(-0.707106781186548,0.707106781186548,0.));
#1966=AXIS2_PLACEMENT_3D('',#1963,#1964,#1965);
#1967=PLANE('',#1966);
#1968=DIRECTION('',(-0.707106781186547,0.707106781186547,0.));
#1969=VECTOR('',#1968,1.);
#1970=CARTESIAN_POINT('',(35.7012193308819,43.9,-4.));
#1971=LINE('',#1970,#1969);
#1972=EDGE_CURVE('E720',#1800,#1949,#1971,.T.);
#1973=ORIENTED_EDGE('',*,*,#1972,.T.);
#1974=ORIENTED_EDGE('',*,*,#1958,.F.);
#1975=ORIENTED_EDGE('',*,*,#1734,.F.);
#1976=ORIENTED_EDGE('',*,*,#1807,.T.);
#1977=EDGE_LOOP('',(#1973,#1974,#1975,#1976));
#1978=FACE_BOUND('',#1977,.T.);
#1979=ADVANCED_FACE('F1397',(#1978),#1967,.F.);
#1980=ORIENTED_EDGE('',*,*,#1801,.F.);
#1981=ORIENTED_EDGE('',*,*,#1830,.F.);
#1982=ORIENTED_EDGE('',*,*,#1854,.F.);
#1983=ORIENTED_EDGE('',*,*,#1878,.F.);
#1984=ORIENTED_EDGE('',*,*,#1902,.F.);
#1985=ORIENTED_EDGE('',*,*,#1926,.F.);
#1986=ORIENTED_EDGE('',*,*,#1950,.F.);
#1987=ORIENTED_EDGE('',*,*,#1972,.F.);
#1988=EDGE_LOOP('',(#1980,#1981,#1982,#1983,#1984,#1985,#1986,#1987));
#1989=FACE_BOUND('',#1988,.T.);
#1990=ADVANCED_FACE('F1312',(#1989),#880,.F.);
#1991=CARTESIAN_POINT('',(34.4999999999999,-41.,-8.));
#1992=DIRECTION('',(0.,0.,1.));
#1993=DIRECTION('',(1.,0.,0.));
#1994=AXIS2_PLACEMENT_3D('',#1991,#1992,#1993);
#1995=CYLINDRICAL_SURFACE('',#1994,4.5);
#1996=CARTESIAN_POINT('',(34.4999999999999,-41.,-8.));
#1997=DIRECTION('',(0.,0.,1.));
#1998=DIRECTION('',(1.,0.,0.));
#1999=AXIS2_PLACEMENT_3D('',#1996,#1997,#1998);
#2000=CIRCLE('',#1999,4.5);
#2001=CARTESIAN_POINT('',(38.9999999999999,-41.,-8.));
#2002=VERTEX_POINT('',#2001);
#2003=EDGE_CURVE('E686',#2002,#2002,#2000,.T.);
#2004=ORIENTED_EDGE('',*,*,#2003,.T.);
#2005=EDGE_LOOP('',(#2004));
#2006=FACE_BOUND('',#2005,.T.);
#2007=ORIENTED_EDGE('',*,*,#899,.F.);
#2008=EDGE_LOOP('',(#2007));
#2009=FACE_BOUND('',#2008,.T.);
#2010=ADVANCED_FACE('F1382',(#2006,#2009),#1995,.T.);
#2011=CARTESIAN_POINT('',(34.4999999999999,-41.,-8.));
#2012=DIRECTION('',(0.,0.,1.));
#2013=DIRECTION('',(1.,0.,0.));
#2014=AXIS2_PLACEMENT_3D('',#2011,#2012,#2013);
#2015=PLANE('',#2014);
#2016=DIRECTION('',(0.,1.,0.));
#2017=VECTOR('',#2016,1.);
#2018=CARTESIAN_POINT('',(37.3999999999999,-42.201219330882,-8.));
#2019=LINE('',#2018,#2017);
#2020=CARTESIAN_POINT('',(37.3999999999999,-42.201219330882,-8.));
#2021=VERTEX_POINT('',#2020);
#2022=CARTESIAN_POINT('',(37.3999999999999,-39.798780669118,-8.));
#2023=VERTEX_POINT('',#2022);
#2024=EDGE_CURVE('E636',#2021,#2023,#2019,.T.);
#2025=ORIENTED_EDGE('',*,*,#2024,.T.);
#2026=DIRECTION('',(-0.707106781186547,0.707106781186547,0.));
#2027=VECTOR('',#2026,1.);
#2028=CARTESIAN_POINT('',(37.3999999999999,-39.798780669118,-8.));
#2029=LINE('',#2028,#2027);
#2030=CARTESIAN_POINT('',(35.7012193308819,-38.1,-8.));
#2031=VERTEX_POINT('',#2030);
#2032=EDGE_CURVE('E614',#2023,#2031,#2029,.T.);
#2033=ORIENTED_EDGE('',*,*,#2032,.T.);
#2034=DIRECTION('',(-1.,0.,0.));
#2035=VECTOR('',#2034,1.);
#2036=CARTESIAN_POINT('',(35.7012193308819,-38.1,-8.));
#2037=LINE('',#2036,#2035);
#2038=CARTESIAN_POINT('',(33.2987806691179,-38.1,-8.));
#2039=VERTEX_POINT('',#2038);
#2040=EDGE_CURVE('E617',#2031,#2039,#2037,.T.);
#2041=ORIENTED_EDGE('',*,*,#2040,.T.);
#2042=DIRECTION('',(-0.707106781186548,-0.707106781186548,0.));
#2043=VECTOR('',#2042,1.);
#2044=CARTESIAN_POINT('',(33.2987806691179,-38.1,-8.));
#2045=LINE('',#2044,#2043);
#2046=CARTESIAN_POINT('',(31.5999999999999,-39.798780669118,-8.));
#2047=VERTEX_POINT('',#2046);
#2048=EDGE_CURVE('E621',#2039,#2047,#2045,.T.);
#2049=ORIENTED_EDGE('',*,*,#2048,.T.);
#2050=DIRECTION('',(0.,-1.,0.));
#2051=VECTOR('',#2050,1.);
#2052=CARTESIAN_POINT('',(31.5999999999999,-39.798780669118,-8.));
#2053=LINE('',#2052,#2051);
#2054=CARTESIAN_POINT('',(31.5999999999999,-42.201219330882,-8.));
#2055=VERTEX_POINT('',#2054);
#2056=EDGE_CURVE('E624',#2047,#2055,#2053,.T.);
#2057=ORIENTED_EDGE('',*,*,#2056,.T.);
#2058=DIRECTION('',(0.707106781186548,-0.707106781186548,0.));
#2059=VECTOR('',#2058,1.);
#2060=CARTESIAN_POINT('',(31.5999999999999,-42.201219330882,-8.));
#2061=LINE('',#2060,#2059);
#2062=CARTESIAN_POINT('',(33.2987806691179,-43.9,-8.));
#2063=VERTEX_POINT('',#2062);
#2064=EDGE_CURVE('E627',#2055,#2063,#2061,.T.);
#2065=ORIENTED_EDGE('',*,*,#2064,.T.);
#2066=DIRECTION('',(1.,0.,0.));
#2067=VECTOR('',#2066,1.);
#2068=CARTESIAN_POINT('',(33.2987806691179,-43.9,-8.));
#2069=LINE('',#2068,#2067);
#2070=CARTESIAN_POINT('',(35.7012193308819,-43.9,-8.));
#2071=VERTEX_POINT('',#2070);
#2072=EDGE_CURVE('E630',#2063,#2071,#2069,.T.);
#2073=ORIENTED_EDGE('',*,*,#2072,.T.);
#2074=DIRECTION('',(0.707106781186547,0.707106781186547,0.));
#2075=VECTOR('',#2074,1.);
#2076=CARTESIAN_POINT('',(35.7012193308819,-43.9,-8.));
#2077=LINE('',#2076,#2075);
#2078=EDGE_CURVE('E633',#2071,#2021,#2077,.T.);
#2079=ORIENTED_EDGE('',*,*,#2078,.T.);
#2080=EDGE_LOOP('',(#2025,#2033,#2041,#2049,#2057,#2065,#2073,#2079));
#2081=FACE_BOUND('',#2080,.T.);
#2082=ORIENTED_EDGE('',*,*,#2003,.F.);
#2083=EDGE_LOOP('',(#2082));
#2084=FACE_BOUND('',#2083,.T.);
#2085=ADVANCED_FACE('F1374',(#2081,#2084),#2015,.F.);
#2086=CARTESIAN_POINT('',(37.3999999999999,-39.798780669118,-8.));
#2087=DIRECTION('',(0.707106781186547,0.707106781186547,0.));
#2088=DIRECTION('',(-0.707106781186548,0.707106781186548,0.));
#2089=AXIS2_PLACEMENT_3D('',#2086,#2087,#2088);
#2090=PLANE('',#2089);
#2091=DIRECTION('',(-0.707106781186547,0.707106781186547,0.));
#2092=VECTOR('',#2091,1.);
#2093=CARTESIAN_POINT('',(37.3999999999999,-39.798780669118,-4.));
#2094=LINE('',#2093,#2092);
#2095=CARTESIAN_POINT('',(37.3999999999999,-39.798780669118,-4.));
#2096=VERTEX_POINT('',#2095);
#2097=CARTESIAN_POINT('',(35.7012193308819,-38.1,-4.));
#2098=VERTEX_POINT('',#2097);
#2099=EDGE_CURVE('E611',#2096,#2098,#2094,.T.);
#2100=ORIENTED_EDGE('',*,*,#2099,.T.);
#2101=DIRECTION('',(0.,0.,1.));
#2102=VECTOR('',#2101,1.);
#2103=CARTESIAN_POINT('',(35.7012193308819,-38.1,-8.));
#2104=LINE('',#2103,#2102);
#2105=EDGE_CURVE('E639',#2031,#2098,#2104,.T.);
#2106=ORIENTED_EDGE('',*,*,#2105,.F.);
#2107=ORIENTED_EDGE('',*,*,#2032,.F.);
#2108=DIRECTION('',(0.,0.,1.));
#2109=VECTOR('',#2108,1.);
#2110=CARTESIAN_POINT('',(37.3999999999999,-39.798780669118,-8.));
#2111=LINE('',#2110,#2109);
#2112=EDGE_CURVE('E662',#2023,#2096,#2111,.T.);
#2113=ORIENTED_EDGE('',*,*,#2112,.T.);
#2114=EDGE_LOOP('',(#2100,#2106,#2107,#2113));
#2115=FACE_BOUND('',#2114,.T.);
#2116=ADVANCED_FACE('F1366',(#2115),#2090,.F.);
#2117=CARTESIAN_POINT('',(37.3999999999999,-42.201219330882,-8.));
#2118=DIRECTION('',(1.,0.,0.));
#2119=DIRECTION('',(0.,0.,-1.));
#2120=AXIS2_PLACEMENT_3D('',#2117,#2118,#2119);
#2121=PLANE('',#2120);
#2122=DIRECTION('',(0.,1.,0.));
#2123=VECTOR('',#2122,1.);
#2124=CARTESIAN_POINT('',(37.3999999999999,-42.201219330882,-4.));
#2125=LINE('',#2124,#2123);
#2126=CARTESIAN_POINT('',(37.3999999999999,-42.201219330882,-4.));
#2127=VERTEX_POINT('',#2126);
#2128=EDGE_CURVE('E618',#2127,#2096,#2125,.T.);
#2129=ORIENTED_EDGE('',*,*,#2128,.T.);
#2130=ORIENTED_EDGE('',*,*,#2112,.F.);
#2131=ORIENTED_EDGE('',*,*,#2024,.F.);
#2132=DIRECTION('',(0.,0.,1.));
#2133=VECTOR('',#2132,1.);
#2134=CARTESIAN_POINT('',(37.3999999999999,-42.201219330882,-8.));
#2135=LINE('',#2134,#2133);
#2136=EDGE_CURVE('E666',#2021,#2127,#2135,.T.);
#2137=ORIENTED_EDGE('',*,*,#2136,.T.);
#2138=EDGE_LOOP('',(#2129,#2130,#2131,#2137));
#2139=FACE_BOUND('',#2138,.T.);
#2140=ADVANCED_FACE('F1358',(#2139),#2121,.F.);
#2141=CARTESIAN_POINT('',(35.7012193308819,-43.9,-8.));
#2142=DIRECTION('',(0.707106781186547,-0.707106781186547,0.));
#2143=DIRECTION('',(0.707106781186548,0.707106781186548,0.));
#2144=AXIS2_PLACEMENT_3D('',#2141,#2142,#2143);
#2145=PLANE('',#2144);
#2146=DIRECTION('',(0.707106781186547,0.707106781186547,0.));
#2147=VECTOR('',#2146,1.);
#2148=CARTESIAN_POINT('',(35.7012193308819,-43.9,-4.));
#2149=LINE('',#2148,#2147);
#2150=CARTESIAN_POINT('',(35.7012193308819,-43.9,-4.));
#2151=VERTEX_POINT('',#2150);
#2152=EDGE_CURVE('E657',#2151,#2127,#2149,.T.);
#2153=ORIENTED_EDGE('',*,*,#2152,.T.);
#2154=ORIENTED_EDGE('',*,*,#2136,.F.);
#2155=ORIENTED_EDGE('',*,*,#2078,.F.);
#2156=DIRECTION('',(0.,0.,1.));
#2157=VECTOR('',#2156,1.);
#2158=CARTESIAN_POINT('',(35.7012193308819,-43.9,-8.));
#2159=LINE('',#2158,#2157);
#2160=EDGE_CURVE('E669',#2071,#2151,#2159,.T.);
#2161=ORIENTED_EDGE('',*,*,#2160,.T.);
#2162=EDGE_LOOP('',(#2153,#2154,#2155,#2161));
#2163=FACE_BOUND('',#2162,.T.);
#2164=ADVANCED_FACE('F1350',(#2163),#2145,.F.);
#2165=CARTESIAN_POINT('',(33.2987806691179,-43.9,-8.));
#2166=DIRECTION('',(0.,-1.,0.));
#2167=DIRECTION('',(0.,0.,-1.));
#2168=AXIS2_PLACEMENT_3D('',#2165,#2166,#2167);
#2169=PLANE('',#2168);
#2170=DIRECTION('',(1.,0.,0.));
#2171=VECTOR('',#2170,1.);
#2172=CARTESIAN_POINT('',(33.2987806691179,-43.9,-4.));
#2173=LINE('',#2172,#2171);
#2174=CARTESIAN_POINT('',(33.2987806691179,-43.9,-4.));
#2175=VERTEX_POINT('',#2174);
#2176=EDGE_CURVE('E654',#2175,#2151,#2173,.T.);
#2177=ORIENTED_EDGE('',*,*,#2176,.T.);
#2178=ORIENTED_EDGE('',*,*,#2160,.F.);
#2179=ORIENTED_EDGE('',*,*,#2072,.F.);
#2180=DIRECTION('',(0.,0.,1.));
#2181=VECTOR('',#2180,1.);
#2182=CARTESIAN_POINT('',(33.2987806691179,-43.9,-8.));
#2183=LINE('',#2182,#2181);
#2184=EDGE_CURVE('E672',#2063,#2175,#2183,.T.);
#2185=ORIENTED_EDGE('',*,*,#2184,.T.);
#2186=EDGE_LOOP('',(#2177,#2178,#2179,#2185));
#2187=FACE_BOUND('',#2186,.T.);
#2188=ADVANCED_FACE('F1342',(#2187),#2169,.F.);
#2189=CARTESIAN_POINT('',(31.5999999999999,-42.201219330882,-8.));
#2190=DIRECTION('',(-0.707106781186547,-0.707106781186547,0.));
#2191=DIRECTION('',(0.707106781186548,-0.707106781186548,0.));
#2192=AXIS2_PLACEMENT_3D('',#2189,#2190,#2191);
#2193=PLANE('',#2192);
#2194=DIRECTION('',(0.707106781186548,-0.707106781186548,0.));
#2195=VECTOR('',#2194,1.);
#2196=CARTESIAN_POINT('',(31.5999999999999,-42.201219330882,-4.));
#2197=LINE('',#2196,#2195);
#2198=CARTESIAN_POINT('',(31.5999999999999,-42.201219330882,-4.));
#2199=VERTEX_POINT('',#2198);
#2200=EDGE_CURVE('E651',#2199,#2175,#2197,.T.);
#2201=ORIENTED_EDGE('',*,*,#2200,.T.);
#2202=ORIENTED_EDGE('',*,*,#2184,.F.);
#2203=ORIENTED_EDGE('',*,*,#2064,.F.);
#2204=DIRECTION('',(0.,0.,1.));
#2205=VECTOR('',#2204,1.);
#2206=CARTESIAN_POINT('',(31.5999999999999,-42.201219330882,-8.));
#2207=LINE('',#2206,#2205);
#2208=EDGE_CURVE('E675',#2055,#2199,#2207,.T.);
#2209=ORIENTED_EDGE('',*,*,#2208,.T.);
#2210=EDGE_LOOP('',(#2201,#2202,#2203,#2209));
#2211=FACE_BOUND('',#2210,.T.);
#2212=ADVANCED_FACE('F1334',(#2211),#2193,.F.);
#2213=CARTESIAN_POINT('',(31.5999999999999,-39.798780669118,-8.));
#2214=DIRECTION('',(-1.,0.,0.));
#2215=DIRECTION('',(0.,0.,1.));
#2216=AXIS2_PLACEMENT_3D('',#2213,#2214,#2215);
#2217=PLANE('',#2216);
#2218=DIRECTION('',(0.,-1.,0.));
#2219=VECTOR('',#2218,1.);
#2220=CARTESIAN_POINT('',(31.5999999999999,-39.798780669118,-4.));
#2221=LINE('',#2220,#2219);
#2222=CARTESIAN_POINT('',(31.5999999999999,-39.798780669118,-4.));
#2223=VERTEX_POINT('',#2222);
#2224=EDGE_CURVE('E648',#2223,#2199,#2221,.T.);
#2225=ORIENTED_EDGE('',*,*,#2224,.T.);
#2226=ORIENTED_EDGE('',*,*,#2208,.F.);
#2227=ORIENTED_EDGE('',*,*,#2056,.F.);
#2228=DIRECTION('',(0.,0.,1.));
#2229=VECTOR('',#2228,1.);
#2230=CARTESIAN_POINT('',(31.5999999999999,-39.798780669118,-8.));
#2231=LINE('',#2230,#2229);
#2232=EDGE_CURVE('E678',#2047,#2223,#2231,.T.);
#2233=ORIENTED_EDGE('',*,*,#2232,.T.);
#2234=EDGE_LOOP('',(#2225,#2226,#2227,#2233));
#2235=FACE_BOUND('',#2234,.T.);
#2236=ADVANCED_FACE('F1326',(#2235),#2217,.F.);
#2237=CARTESIAN_POINT('',(33.2987806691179,-38.1,-8.));
#2238=DIRECTION('',(-0.707106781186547,0.707106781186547,0.));
#2239=DIRECTION('',(-0.707106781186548,-0.707106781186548,0.));
#2240=AXIS2_PLACEMENT_3D('',#2237,#2238,#2239);
#2241=PLANE('',#2240);
#2242=DIRECTION('',(-0.707106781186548,-0.707106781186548,0.));
#2243=VECTOR('',#2242,1.);
#2244=CARTESIAN_POINT('',(33.2987806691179,-38.1,-4.));
#2245=LINE('',#2244,#2243);
#2246=CARTESIAN_POINT('',(33.2987806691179,-38.1,-4.));
#2247=VERTEX_POINT('',#2246);
#2248=EDGE_CURVE('E645',#2247,#2223,#2245,.T.);
#2249=ORIENTED_EDGE('',*,*,#2248,.T.);
#2250=ORIENTED_EDGE('',*,*,#2232,.F.);
#2251=ORIENTED_EDGE('',*,*,#2048,.F.);
#2252=DIRECTION('',(0.,0.,1.));
#2253=VECTOR('',#2252,1.);
#2254=CARTESIAN_POINT('',(33.2987806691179,-38.1,-8.));
#2255=LINE('',#2254,#2253);
#2256=EDGE_CURVE('E681',#2039,#2247,#2255,.T.);
#2257=ORIENTED_EDGE('',*,*,#2256,.T.);
#2258=EDGE_LOOP('',(#2249,#2250,#2251,#2257));
#2259=FACE_BOUND('',#2258,.T.);
#2260=ADVANCED_FACE('F1318',(#2259),#2241,.F.);
#2261=CARTESIAN_POINT('',(35.7012193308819,-38.1,-8.));
#2262=DIRECTION('',(0.,1.,0.));
#2263=DIRECTION('',(0.,0.,1.));
#2264=AXIS2_PLACEMENT_3D('',#2261,#2262,#2263);
#2265=PLANE('',#2264);
#2266=DIRECTION('',(-1.,0.,0.));
#2267=VECTOR('',#2266,1.);
#2268=CARTESIAN_POINT('',(35.7012193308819,-38.1,-4.));
#2269=LINE('',#2268,#2267);
#2270=EDGE_CURVE('E642',#2098,#2247,#2269,.T.);
#2271=ORIENTED_EDGE('',*,*,#2270,.T.);
#2272=ORIENTED_EDGE('',*,*,#2256,.F.);
#2273=ORIENTED_EDGE('',*,*,#2040,.F.);
#2274=ORIENTED_EDGE('',*,*,#2105,.T.);
#2275=EDGE_LOOP('',(#2271,#2272,#2273,#2274));
#2276=FACE_BOUND('',#2275,.T.);
#2277=ADVANCED_FACE('F1310',(#2276),#2265,.F.);
#2278=ORIENTED_EDGE('',*,*,#2099,.F.);
#2279=ORIENTED_EDGE('',*,*,#2128,.F.);
#2280=ORIENTED_EDGE('',*,*,#2152,.F.);
#2281=ORIENTED_EDGE('',*,*,#2176,.F.);
#2282=ORIENTED_EDGE('',*,*,#2200,.F.);
#2283=ORIENTED_EDGE('',*,*,#2224,.F.);
#2284=ORIENTED_EDGE('',*,*,#2248,.F.);
#2285=ORIENTED_EDGE('',*,*,#2270,.F.);
#2286=EDGE_LOOP('',(#2278,#2279,#2280,#2281,#2282,#2283,#2284,#2285));
#2287=FACE_BOUND('',#2286,.T.);
#2288=ADVANCED_FACE('F1223',(#2287),#880,.F.);
#2289=CARTESIAN_POINT('',(-34.5,-41.,-8.));
#2290=DIRECTION('',(0.,0.,1.));
#2291=DIRECTION('',(1.,0.,0.));
#2292=AXIS2_PLACEMENT_3D('',#2289,#2290,#2291);
#2293=CYLINDRICAL_SURFACE('',#2292,4.5);
#2294=CARTESIAN_POINT('',(-34.5,-41.,-8.));
#2295=DIRECTION('',(0.,0.,1.));
#2296=DIRECTION('',(-1.,0.,0.));
#2297=AXIS2_PLACEMENT_3D('',#2294,#2295,#2296);
#2298=CIRCLE('',#2297,4.5);
#2299=CARTESIAN_POINT('',(-39.,-41.,-8.));
#2300=VERTEX_POINT('',#2299);
#2301=EDGE_CURVE('E608',#2300,#2300,#2298,.T.);
#2302=ORIENTED_EDGE('',*,*,#2301,.T.);
#2303=EDGE_LOOP('',(#2302));
#2304=FACE_BOUND('',#2303,.T.);
#2305=ORIENTED_EDGE('',*,*,#888,.F.);
#2306=EDGE_LOOP('',(#2305));
#2307=FACE_BOUND('',#2306,.T.);
#2308=ADVANCED_FACE('F1295',(#2304,#2307),#2293,.T.);
#2309=CARTESIAN_POINT('',(-34.5,-41.,-8.));
#2310=DIRECTION('',(0.,0.,-1.));
#2311=DIRECTION('',(-1.,0.,0.));
#2312=AXIS2_PLACEMENT_3D('',#2309,#2310,#2311);
#2313=PLANE('',#2312);
#2314=DIRECTION('',(0.,-1.,0.));
#2315=VECTOR('',#2314,1.);
#2316=CARTESIAN_POINT('',(-37.4,-42.201219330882,-8.));
#2317=LINE('',#2316,#2315);
#2318=CARTESIAN_POINT('',(-37.4,-39.798780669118,-8.));
#2319=VERTEX_POINT('',#2318);
#2320=CARTESIAN_POINT('',(-37.4,-42.201219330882,-8.));
#2321=VERTEX_POINT('',#2320);
#2322=EDGE_CURVE('E536',#2319,#2321,#2317,.T.);
#2323=ORIENTED_EDGE('',*,*,#2322,.T.);
#2324=DIRECTION('',(0.707106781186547,-0.707106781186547,0.));
#2325=VECTOR('',#2324,1.);
#2326=CARTESIAN_POINT('',(-35.701219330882,-43.9,-8.));
#2327=LINE('',#2326,#2325);
#2328=CARTESIAN_POINT('',(-35.701219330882,-43.9,-8.));
#2329=VERTEX_POINT('',#2328);
#2330=EDGE_CURVE('E539',#2321,#2329,#2327,.T.);
#2331=ORIENTED_EDGE('',*,*,#2330,.T.);
#2332=DIRECTION('',(1.,0.,0.));
#2333=VECTOR('',#2332,1.);
#2334=CARTESIAN_POINT('',(-33.298780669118,-43.9,-8.));
#2335=LINE('',#2334,#2333);
#2336=CARTESIAN_POINT('',(-33.298780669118,-43.9,-8.));
#2337=VERTEX_POINT('',#2336);
#2338=EDGE_CURVE('E543',#2329,#2337,#2335,.T.);
#2339=ORIENTED_EDGE('',*,*,#2338,.T.);
#2340=DIRECTION('',(0.707106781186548,0.707106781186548,0.));
#2341=VECTOR('',#2340,1.);
#2342=CARTESIAN_POINT('',(-31.6,-42.201219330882,-8.));
#2343=LINE('',#2342,#2341);
#2344=CARTESIAN_POINT('',(-31.6,-42.201219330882,-8.));
#2345=VERTEX_POINT('',#2344);
#2346=EDGE_CURVE('E546',#2337,#2345,#2343,.T.);
#2347=ORIENTED_EDGE('',*,*,#2346,.T.);
#2348=DIRECTION('',(0.,1.,0.));
#2349=VECTOR('',#2348,1.);
#2350=CARTESIAN_POINT('',(-31.6,-39.798780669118,-8.));
#2351=LINE('',#2350,#2349);
#2352=CARTESIAN_POINT('',(-31.6,-39.798780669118,-8.));
#2353=VERTEX_POINT('',#2352);
#2354=EDGE_CURVE('E549',#2345,#2353,#2351,.T.);
#2355=ORIENTED_EDGE('',*,*,#2354,.T.);
#2356=DIRECTION('',(-0.707106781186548,0.707106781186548,0.));
#2357=VECTOR('',#2356,1.);
#2358=CARTESIAN_POINT('',(-33.298780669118,-38.1,-8.));
#2359=LINE('',#2358,#2357);
#2360=CARTESIAN_POINT('',(-33.298780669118,-38.1,-8.));
#2361=VERTEX_POINT('',#2360);
#2362=EDGE_CURVE('E552',#2353,#2361,#2359,.T.);
#2363=ORIENTED_EDGE('',*,*,#2362,.T.);
#2364=DIRECTION('',(-1.,0.,0.));
#2365=VECTOR('',#2364,1.);
#2366=CARTESIAN_POINT('',(-35.701219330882,-38.1,-8.));
#2367=LINE('',#2366,#2365);
#2368=CARTESIAN_POINT('',(-35.701219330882,-38.1,-8.));
#2369=VERTEX_POINT('',#2368);
#2370=EDGE_CURVE('E555',#2361,#2369,#2367,.T.);
#2371=ORIENTED_EDGE('',*,*,#2370,.T.);
#2372=DIRECTION('',(-0.707106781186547,-0.707106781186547,0.));
#2373=VECTOR('',#2372,1.);
#2374=CARTESIAN_POINT('',(-37.4,-39.798780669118,-8.));
#2375=LINE('',#2374,#2373);
#2376=EDGE_CURVE('E558',#2369,#2319,#2375,.T.);
#2377=ORIENTED_EDGE('',*,*,#2376,.T.);
#2378=EDGE_LOOP('',(#2323,#2331,#2339,#2347,#2355,#2363,#2371,#2377));
#2379=FACE_BOUND('',#2378,.T.);
#2380=ORIENTED_EDGE('',*,*,#2301,.F.);
#2381=EDGE_LOOP('',(#2380));
#2382=FACE_BOUND('',#2381,.T.);
#2383=ADVANCED_FACE('F1287',(#2379,#2382),#2313,.T.);
#2384=CARTESIAN_POINT('',(-37.4,-42.201219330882,-8.));
#2385=DIRECTION('',(-1.,0.,0.));
#2386=DIRECTION('',(0.,0.,1.));
#2387=AXIS2_PLACEMENT_3D('',#2384,#2385,#2386);
#2388=PLANE('',#2387);
#2389=DIRECTION('',(0.,-1.,0.));
#2390=VECTOR('',#2389,1.);
#2391=CARTESIAN_POINT('',(-37.4,-42.201219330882,-4.));
#2392=LINE('',#2391,#2390);
#2393=CARTESIAN_POINT('',(-37.4,-39.798780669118,-4.));
#2394=VERTEX_POINT('',#2393);
#2395=CARTESIAN_POINT('',(-37.4,-42.201219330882,-4.));
#2396=VERTEX_POINT('',#2395);
#2397=EDGE_CURVE('E531',#2394,#2396,#2392,.T.);
#2398=ORIENTED_EDGE('',*,*,#2397,.T.);
#2399=DIRECTION('',(0.,0.,1.));
#2400=VECTOR('',#2399,1.);
#2401=CARTESIAN_POINT('',(-37.4,-42.201219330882,-8.));
#2402=LINE('',#2401,#2400);
#2403=EDGE_CURVE('E561',#2321,#2396,#2402,.T.);
#2404=ORIENTED_EDGE('',*,*,#2403,.F.);
#2405=ORIENTED_EDGE('',*,*,#2322,.F.);
#2406=DIRECTION('',(0.,0.,1.));
#2407=VECTOR('',#2406,1.);
#2408=CARTESIAN_POINT('',(-37.4,-39.798780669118,-8.));
#2409=LINE('',#2408,#2407);
#2410=EDGE_CURVE('E584',#2319,#2394,#2409,.T.);
#2411=ORIENTED_EDGE('',*,*,#2410,.T.);
#2412=EDGE_LOOP('',(#2398,#2404,#2405,#2411));
#2413=FACE_BOUND('',#2412,.T.);
#2414=ADVANCED_FACE('F1279',(#2413),#2388,.F.);
#2415=CARTESIAN_POINT('',(-37.4,-39.798780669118,-8.));
#2416=DIRECTION('',(-0.707106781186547,0.707106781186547,0.));
#2417=DIRECTION('',(-0.707106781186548,-0.707106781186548,0.));
#2418=AXIS2_PLACEMENT_3D('',#2415,#2416,#2417);
#2419=PLANE('',#2418);
#2420=DIRECTION('',(-0.707106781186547,-0.707106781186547,0.));
#2421=VECTOR('',#2420,1.);
#2422=CARTESIAN_POINT('',(-37.4,-39.798780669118,-4.));
#2423=LINE('',#2422,#2421);
#2424=CARTESIAN_POINT('',(-35.701219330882,-38.1,-4.));
#2425=VERTEX_POINT('',#2424);
#2426=EDGE_CURVE('E540',#2425,#2394,#2423,.T.);
#2427=ORIENTED_EDGE('',*,*,#2426,.T.);
#2428=ORIENTED_EDGE('',*,*,#2410,.F.);
#2429=ORIENTED_EDGE('',*,*,#2376,.F.);
#2430=DIRECTION('',(0.,0.,1.));
#2431=VECTOR('',#2430,1.);
#2432=CARTESIAN_POINT('',(-35.701219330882,-38.1,-8.));
#2433=LINE('',#2432,#2431);
#2434=EDGE_CURVE('E588',#2369,#2425,#2433,.T.);
#2435=ORIENTED_EDGE('',*,*,#2434,.T.);
#2436=EDGE_LOOP('',(#2427,#2428,#2429,#2435));
#2437=FACE_BOUND('',#2436,.T.);
#2438=ADVANCED_FACE('F1271',(#2437),#2419,.F.);
#2439=CARTESIAN_POINT('',(-35.701219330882,-38.1,-8.));
#2440=DIRECTION('',(0.,1.,0.));
#2441=DIRECTION('',(0.,0.,1.));
#2442=AXIS2_PLACEMENT_3D('',#2439,#2440,#2441);
#2443=PLANE('',#2442);
#2444=DIRECTION('',(-1.,0.,0.));
#2445=VECTOR('',#2444,1.);
#2446=CARTESIAN_POINT('',(-35.701219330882,-38.1,-4.));
#2447=LINE('',#2446,#2445);
#2448=CARTESIAN_POINT('',(-33.298780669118,-38.1,-4.));
#2449=VERTEX_POINT('',#2448);
#2450=EDGE_CURVE('E579',#2449,#2425,#2447,.T.);
#2451=ORIENTED_EDGE('',*,*,#2450,.T.);
#2452=ORIENTED_EDGE('',*,*,#2434,.F.);
#2453=ORIENTED_EDGE('',*,*,#2370,.F.);
#2454=DIRECTION('',(0.,0.,1.));
#2455=VECTOR('',#2454,1.);
#2456=CARTESIAN_POINT('',(-33.298780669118,-38.1,-8.));
#2457=LINE('',#2456,#2455);
#2458=EDGE_CURVE('E591',#2361,#2449,#2457,.T.);
#2459=ORIENTED_EDGE('',*,*,#2458,.T.);
#2460=EDGE_LOOP('',(#2451,#2452,#2453,#2459));
#2461=FACE_BOUND('',#2460,.T.);
#2462=ADVANCED_FACE('F1263',(#2461),#2443,.F.);
#2463=CARTESIAN_POINT('',(-33.298780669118,-38.1,-8.));
#2464=DIRECTION('',(0.707106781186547,0.707106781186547,0.));
#2465=DIRECTION('',(-0.707106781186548,0.707106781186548,0.));
#2466=AXIS2_PLACEMENT_3D('',#2463,#2464,#2465);
#2467=PLANE('',#2466);
#2468=DIRECTION('',(-0.707106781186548,0.707106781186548,0.));
#2469=VECTOR('',#2468,1.);
#2470=CARTESIAN_POINT('',(-33.298780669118,-38.1,-4.));
#2471=LINE('',#2470,#2469);
#2472=CARTESIAN_POINT('',(-31.6,-39.798780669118,-4.));
#2473=VERTEX_POINT('',#2472);
#2474=EDGE_CURVE('E576',#2473,#2449,#2471,.T.);
#2475=ORIENTED_EDGE('',*,*,#2474,.T.);
#2476=ORIENTED_EDGE('',*,*,#2458,.F.);
#2477=ORIENTED_EDGE('',*,*,#2362,.F.);
#2478=DIRECTION('',(0.,0.,1.));
#2479=VECTOR('',#2478,1.);
#2480=CARTESIAN_POINT('',(-31.6,-39.798780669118,-8.));
#2481=LINE('',#2480,#2479);
#2482=EDGE_CURVE('E594',#2353,#2473,#2481,.T.);
#2483=ORIENTED_EDGE('',*,*,#2482,.T.);
#2484=EDGE_LOOP('',(#2475,#2476,#2477,#2483));
#2485=FACE_BOUND('',#2484,.T.);
#2486=ADVANCED_FACE('F1255',(#2485),#2467,.F.);
#2487=CARTESIAN_POINT('',(-31.6,-39.798780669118,-8.));
#2488=DIRECTION('',(1.,0.,0.));
#2489=DIRECTION('',(0.,0.,-1.));
#2490=AXIS2_PLACEMENT_3D('',#2487,#2488,#2489);
#2491=PLANE('',#2490);
#2492=DIRECTION('',(0.,1.,0.));
#2493=VECTOR('',#2492,1.);
#2494=CARTESIAN_POINT('',(-31.6,-39.798780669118,-4.));
#2495=LINE('',#2494,#2493);
#2496=CARTESIAN_POINT('',(-31.6,-42.201219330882,-4.));
#2497=VERTEX_POINT('',#2496);
#2498=EDGE_CURVE('E573',#2497,#2473,#2495,.T.);
#2499=ORIENTED_EDGE('',*,*,#2498,.T.);
#2500=ORIENTED_EDGE('',*,*,#2482,.F.);
#2501=ORIENTED_EDGE('',*,*,#2354,.F.);
#2502=DIRECTION('',(0.,0.,1.));
#2503=VECTOR('',#2502,1.);
#2504=CARTESIAN_POINT('',(-31.6,-42.201219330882,-8.));
#2505=LINE('',#2504,#2503);
#2506=EDGE_CURVE('E597',#2345,#2497,#2505,.T.);
#2507=ORIENTED_EDGE('',*,*,#2506,.T.);
#2508=EDGE_LOOP('',(#2499,#2500,#2501,#2507));
#2509=FACE_BOUND('',#2508,.T.);
#2510=ADVANCED_FACE('F1247',(#2509),#2491,.F.);
#2511=CARTESIAN_POINT('',(-31.6,-42.201219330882,-8.));
#2512=DIRECTION('',(0.707106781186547,-0.707106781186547,0.));
#2513=DIRECTION('',(0.707106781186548,0.707106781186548,0.));
#2514=AXIS2_PLACEMENT_3D('',#2511,#2512,#2513);
#2515=PLANE('',#2514);
#2516=DIRECTION('',(0.707106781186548,0.707106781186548,0.));
#2517=VECTOR('',#2516,1.);
#2518=CARTESIAN_POINT('',(-31.6,-42.201219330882,-4.));
#2519=LINE('',#2518,#2517);
#2520=CARTESIAN_POINT('',(-33.298780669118,-43.9,-4.));
#2521=VERTEX_POINT('',#2520);
#2522=EDGE_CURVE('E570',#2521,#2497,#2519,.T.);
#2523=ORIENTED_EDGE('',*,*,#2522,.T.);
#2524=ORIENTED_EDGE('',*,*,#2506,.F.);
#2525=ORIENTED_EDGE('',*,*,#2346,.F.);
#2526=DIRECTION('',(0.,0.,1.));
#2527=VECTOR('',#2526,1.);
#2528=CARTESIAN_POINT('',(-33.298780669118,-43.9,-8.));
#2529=LINE('',#2528,#2527);
#2530=EDGE_CURVE('E600',#2337,#2521,#2529,.T.);
#2531=ORIENTED_EDGE('',*,*,#2530,.T.);
#2532=EDGE_LOOP('',(#2523,#2524,#2525,#2531));
#2533=FACE_BOUND('',#2532,.T.);
#2534=ADVANCED_FACE('F1239',(#2533),#2515,.F.);
#2535=CARTESIAN_POINT('',(-33.298780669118,-43.9,-8.));
#2536=DIRECTION('',(0.,-1.,0.));
#2537=DIRECTION('',(0.,0.,-1.));
#2538=AXIS2_PLACEMENT_3D('',#2535,#2536,#2537);
#2539=PLANE('',#2538);
#2540=DIRECTION('',(1.,0.,0.));
#2541=VECTOR('',#2540,1.);
#2542=CARTESIAN_POINT('',(-33.298780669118,-43.9,-4.));
#2543=LINE('',#2542,#2541);
#2544=CARTESIAN_POINT('',(-35.701219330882,-43.9,-4.));
#2545=VERTEX_POINT('',#2544);
#2546=EDGE_CURVE('E567',#2545,#2521,#2543,.T.);
#2547=ORIENTED_EDGE('',*,*,#2546,.T.);
#2548=ORIENTED_EDGE('',*,*,#2530,.F.);
#2549=ORIENTED_EDGE('',*,*,#2338,.F.);
#2550=DIRECTION('',(0.,0.,1.));
#2551=VECTOR('',#2550,1.);
#2552=CARTESIAN_POINT('',(-35.701219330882,-43.9,-8.));
#2553=LINE('',#2552,#2551);
#2554=EDGE_CURVE('E603',#2329,#2545,#2553,.T.);
#2555=ORIENTED_EDGE('',*,*,#2554,.T.);
#2556=EDGE_LOOP('',(#2547,#2548,#2549,#2555));
#2557=FACE_BOUND('',#2556,.T.);
#2558=ADVANCED_FACE('F1231',(#2557),#2539,.F.);
#2559=CARTESIAN_POINT('',(-35.701219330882,-43.9,-8.));
#2560=DIRECTION('',(-0.707106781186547,-0.707106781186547,0.));
#2561=DIRECTION('',(0.707106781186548,-0.707106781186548,0.));
#2562=AXIS2_PLACEMENT_3D('',#2559,#2560,#2561);
#2563=PLANE('',#2562);
#2564=DIRECTION('',(0.707106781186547,-0.707106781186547,0.));
#2565=VECTOR('',#2564,1.);
#2566=CARTESIAN_POINT('',(-35.701219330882,-43.9,-4.));
#2567=LINE('',#2566,#2565);
#2568=EDGE_CURVE('E564',#2396,#2545,#2567,.T.);
#2569=ORIENTED_EDGE('',*,*,#2568,.T.);
#2570=ORIENTED_EDGE('',*,*,#2554,.F.);
#2571=ORIENTED_EDGE('',*,*,#2330,.F.);
#2572=ORIENTED_EDGE('',*,*,#2403,.T.);
#2573=EDGE_LOOP('',(#2569,#2570,#2571,#2572));
#2574=FACE_BOUND('',#2573,.T.);
#2575=ADVANCED_FACE('F1221',(#2574),#2563,.F.);
#2576=ORIENTED_EDGE('',*,*,#2397,.F.);
#2577=ORIENTED_EDGE('',*,*,#2426,.F.);
#2578=ORIENTED_EDGE('',*,*,#2450,.F.);
#2579=ORIENTED_EDGE('',*,*,#2474,.F.);
#2580=ORIENTED_EDGE('',*,*,#2498,.F.);
#2581=ORIENTED_EDGE('',*,*,#2522,.F.);
#2582=ORIENTED_EDGE('',*,*,#2546,.F.);
#2583=ORIENTED_EDGE('',*,*,#2568,.F.);
#2584=EDGE_LOOP('',(#2576,#2577,#2578,#2579,#2580,#2581,#2582,#2583));
#2585=FACE_BOUND('',#2584,.T.);
#2586=ADVANCED_FACE('F1214',(#2585),#880,.F.);
#2587=CARTESIAN_POINT('',(-6.49999999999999,-43.,-6.83));
#2588=DIRECTION('',(-1.,0.,0.));
#2589=DIRECTION('',(0.,-1.,0.));
#2590=AXIS2_PLACEMENT_3D('',#2587,#2588,#2589);
#2591=PLANE('',#2590);
#2592=DIRECTION('',(0.,-1.,0.));
#2593=VECTOR('',#2592,1.);
#2594=CARTESIAN_POINT('',(-6.49999999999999,-43.,-6.83));
#2595=LINE('',#2594,#2593);
#2596=CARTESIAN_POINT('',(-6.49999999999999,-52.,-6.83));
#2597=VERTEX_POINT('',#2596);
#2598=EDGE_CURVE('E529',#649,#2597,#2595,.T.);
#2599=ORIENTED_EDGE('',*,*,#2598,.T.);
#2600=DIRECTION('',(0.,0.,-1.));
#2601=VECTOR('',#2600,1.);
#2602=CARTESIAN_POINT('',(-6.49999999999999,-52.,-14.83));
#2603=LINE('',#2602,#2601);
#2604=CARTESIAN_POINT('',(-6.49999999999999,-52.,-14.83));
#2605=VERTEX_POINT('',#2604);
#2606=EDGE_CURVE('E11',#2597,#2605,#2603,.T.);
#2607=ORIENTED_EDGE('',*,*,#2606,.T.);
#2608=DIRECTION('',(0.,-1.,0.));
#2609=VECTOR('',#2608,1.);
#2610=CARTESIAN_POINT('',(-6.5,-43.,-14.83));
#2611=LINE('',#2610,#2609);
#2612=EDGE_CURVE('E423',#647,#2605,#2611,.T.);
#2613=ORIENTED_EDGE('',*,*,#2612,.F.);
#2614=ORIENTED_EDGE('',*,*,#650,.T.);
#2615=EDGE_LOOP('',(#2599,#2607,#2613,#2614));
#2616=FACE_BOUND('',#2615,.T.);
#2617=ADVANCED_FACE('F432',(#2616),#2591,.F.);
#2618=CARTESIAN_POINT('',(-6.49999999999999,-43.,-6.83));
#2619=DIRECTION('',(0.,0.,1.));
#2620=DIRECTION('',(1.,0.,0.));
#2621=AXIS2_PLACEMENT_3D('',#2618,#2619,#2620);
#2622=PLANE('',#2621);
#2623=DIRECTION('',(0.,-1.,0.));
#2624=VECTOR('',#2623,1.);
#2625=CARTESIAN_POINT('',(6.5,-43.,-6.83));
#2626=LINE('',#2625,#2624);
#2627=CARTESIAN_POINT('',(6.5,-52.,-6.83));
#2628=VERTEX_POINT('',#2627);
#2629=EDGE_CURVE('E532',#665,#2628,#2626,.T.);
#2630=ORIENTED_EDGE('',*,*,#2629,.T.);
#2631=DIRECTION('',(-1.,0.,0.));
#2632=VECTOR('',#2631,1.);
#2633=CARTESIAN_POINT('',(-6.49999999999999,-52.,-6.83));
#2634=LINE('',#2633,#2632);
#2635=EDGE_CURVE('E481',#2628,#2597,#2634,.T.);
#2636=ORIENTED_EDGE('',*,*,#2635,.T.);
#2637=ORIENTED_EDGE('',*,*,#2598,.F.);
#2638=ORIENTED_EDGE('',*,*,#672,.T.);
#2639=EDGE_LOOP('',(#2630,#2636,#2637,#2638));
#2640=FACE_BOUND('',#2639,.T.);
#2641=ADVANCED_FACE('F1076',(#2640),#2622,.F.);
#2642=CARTESIAN_POINT('',(6.5,-43.,-6.83));
#2643=DIRECTION('',(1.,0.,0.));
#2644=DIRECTION('',(0.,0.,-1.));
#2645=AXIS2_PLACEMENT_3D('',#2642,#2643,#2644);
#2646=PLANE('',#2645);
#2647=DIRECTION('',(0.,-1.,0.));
#2648=VECTOR('',#2647,1.);
#2649=CARTESIAN_POINT('',(6.5,-43.,-14.83));
#2650=LINE('',#2649,#2648);
#2651=CARTESIAN_POINT('',(6.50000000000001,-52.,-14.83));
#2652=VERTEX_POINT('',#2651);
#2653=EDGE_CURVE('E424',#657,#2652,#2650,.T.);
#2654=ORIENTED_EDGE('',*,*,#2653,.T.);
#2655=DIRECTION('',(0.,0.,1.));
#2656=VECTOR('',#2655,1.);
#2657=CARTESIAN_POINT('',(6.5,-52.,-6.83));
#2658=LINE('',#2657,#2656);
#2659=EDGE_CURVE('E493',#2652,#2628,#2658,.T.);
#2660=ORIENTED_EDGE('',*,*,#2659,.T.);
#2661=ORIENTED_EDGE('',*,*,#2629,.F.);
#2662=ORIENTED_EDGE('',*,*,#666,.T.);
#2663=EDGE_LOOP('',(#2654,#2660,#2661,#2662));
#2664=FACE_BOUND('',#2663,.T.);
#2665=ADVANCED_FACE('F1071',(#2664),#2646,.F.);
#2666=CARTESIAN_POINT('',(-6.5,-43.,-14.83));
#2667=DIRECTION('',(0.,0.,-1.));
#2668=DIRECTION('',(-1.,0.,0.));
#2669=AXIS2_PLACEMENT_3D('',#2666,#2667,#2668);
#2670=PLANE('',#2669);
#2671=ORIENTED_EDGE('',*,*,#2612,.T.);
#2672=DIRECTION('',(1.,0.,0.));
#2673=VECTOR('',#2672,1.);
#2674=CARTESIAN_POINT('',(6.50000000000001,-52.,-14.83));
#2675=LINE('',#2674,#2673);
#2676=EDGE_CURVE('E42',#2605,#2652,#2675,.T.);
#2677=ORIENTED_EDGE('',*,*,#2676,.T.);
#2678=ORIENTED_EDGE('',*,*,#2653,.F.);
#2679=ORIENTED_EDGE('',*,*,#658,.T.);
#2680=EDGE_LOOP('',(#2671,#2677,#2678,#2679));
#2681=FACE_BOUND('',#2680,.T.);
#2682=ADVANCED_FACE('F422',(#2681),#2670,.F.);
#2683=CARTESIAN_POINT('',(53.,52.,-4.));
#2684=DIRECTION('',(-0.707106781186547,-0.707106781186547,0.));
#2685=DIRECTION('',(0.,0.,1.));
#2686=AXIS2_PLACEMENT_3D('',#2683,#2684,#2685);
#2687=PLANE('',#2686);
#2688=ORIENTED_EDGE('',*,*,#514,.F.);
#2689=ORIENTED_EDGE('',*,*,#80,.F.);
#2690=ORIENTED_EDGE('',*,*,#434,.F.);
#2691=ORIENTED_EDGE('',*,*,#120,.F.);
#2692=EDGE_LOOP('',(#2688,#2689,#2690,#2691));
#2693=FACE_BOUND('',#2692,.T.);
#2694=ADVANCED_FACE('F1125',(#2693),#2687,.F.);
#2695=CARTESIAN_POINT('',(-52.,53.,-4.));
#2696=DIRECTION('',(0.707106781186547,-0.707106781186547,0.));
#2697=DIRECTION('',(0.,0.,1.));
#2698=AXIS2_PLACEMENT_3D('',#2695,#2696,#2697);
#2699=PLANE('',#2698);
#2700=ORIENTED_EDGE('',*,*,#535,.F.);
#2701=ORIENTED_EDGE('',*,*,#40,.F.);
#2702=ORIENTED_EDGE('',*,*,#441,.F.);
#2703=ORIENTED_EDGE('',*,*,#94,.F.);
#2704=EDGE_LOOP('',(#2700,#2701,#2702,#2703));
#2705=FACE_BOUND('',#2704,.T.);
#2706=ADVANCED_FACE('F1116',(#2705),#2699,.F.);
#2707=CARTESIAN_POINT('',(-53.,-52.,-4.));
#2708=DIRECTION('',(0.707106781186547,0.707106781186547,0.));
#2709=DIRECTION('',(0.,0.,1.));
#2710=AXIS2_PLACEMENT_3D('',#2707,#2708,#2709);
#2711=PLANE('',#2710);
#2712=ORIENTED_EDGE('',*,*,#528,.F.);
#2713=ORIENTED_EDGE('',*,*,#194,.F.);
#2714=ORIENTED_EDGE('',*,*,#448,.F.);
#2715=ORIENTED_EDGE('',*,*,#54,.F.);
#2716=EDGE_LOOP('',(#2712,#2713,#2714,#2715));
#2717=FACE_BOUND('',#2716,.T.);
#2718=ADVANCED_FACE('F1105',(#2717),#2711,.F.);
#2719=CARTESIAN_POINT('',(52.,-53.,-4.));
#2720=DIRECTION('',(-0.707106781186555,0.70710678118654,0.));
#2721=DIRECTION('',(0.,0.,1.));
#2722=AXIS2_PLACEMENT_3D('',#2719,#2720,#2721);
#2723=PLANE('',#2722);
#2724=ORIENTED_EDGE('',*,*,#521,.F.);
#2725=ORIENTED_EDGE('',*,*,#134,.F.);
#2726=ORIENTED_EDGE('',*,*,#455,.F.);
#2727=ORIENTED_EDGE('',*,*,#208,.F.);
#2728=EDGE_LOOP('',(#2724,#2725,#2726,#2727));
#2729=FACE_BOUND('',#2728,.T.);
#2730=ADVANCED_FACE('F1133',(#2729),#2723,.F.);
#2731=CARTESIAN_POINT('',(-6.49999999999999,-52.,-14.83));
#2732=DIRECTION('',(0.,-0.707106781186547,0.707106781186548));
#2733=DIRECTION('',(-1.,0.,0.));
#2734=AXIS2_PLACEMENT_3D('',#2731,#2732,#2733);
#2735=PLANE('',#2734);
#2736=DIRECTION('',(0.577350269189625,0.577350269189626,0.577350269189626));
#2737=VECTOR('',#2736,1.);
#2738=CARTESIAN_POINT('',(-6.49999999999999,-52.,-14.83));
#2739=LINE('',#2738,#2737);
#2740=EDGE_CURVE('E501',#149,#2605,#2739,.T.);
#2741=ORIENTED_EDGE('',*,*,#2740,.F.);
#2742=ORIENTED_EDGE('',*,*,#174,.F.);
#2743=DIRECTION('',(-0.577350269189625,0.577350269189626,0.577350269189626));
#2744=VECTOR('',#2743,1.);
#2745=CARTESIAN_POINT('',(3.83333333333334,-49.3333333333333,-12.1633333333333));
#2746=LINE('',#2745,#2744);
#2747=EDGE_CURVE('E435',#2652,#167,#2746,.F.);
#2748=ORIENTED_EDGE('',*,*,#2747,.F.);
#2749=ORIENTED_EDGE('',*,*,#2676,.F.);
#2750=EDGE_LOOP('',(#2741,#2742,#2748,#2749));
#2751=FACE_BOUND('',#2750,.T.);
#2752=ADVANCED_FACE('F35',(#2751),#2735,.T.);
#2753=CARTESIAN_POINT('',(6.5,-52.,-6.83));
#2754=DIRECTION('',(-0.707106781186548,-0.707106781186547,0.));
#2755=DIRECTION('',(0.,0.,-1.));
#2756=AXIS2_PLACEMENT_3D('',#2753,#2754,#2755);
#2757=PLANE('',#2756);
#2758=ORIENTED_EDGE('',*,*,#2747,.T.);
#2759=ORIENTED_EDGE('',*,*,#168,.F.);
#2760=DIRECTION('',(-0.577350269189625,0.577350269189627,-0.577350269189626));
#2761=VECTOR('',#2760,1.);
#2762=CARTESIAN_POINT('',(2.16666666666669,-47.6666666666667,-11.1633333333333));
#2763=LINE('',#2762,#2761);
#2764=EDGE_CURVE('E498',#2628,#159,#2763,.F.);
#2765=ORIENTED_EDGE('',*,*,#2764,.F.);
#2766=ORIENTED_EDGE('',*,*,#2659,.F.);
#2767=EDGE_LOOP('',(#2758,#2759,#2765,#2766));
#2768=FACE_BOUND('',#2767,.T.);
#2769=ADVANCED_FACE('F1080',(#2768),#2757,.T.);
#2770=CARTESIAN_POINT('',(-6.49999999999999,-52.,-6.83));
#2771=DIRECTION('',(0.707106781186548,-0.707106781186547,0.));
#2772=DIRECTION('',(0.,0.,1.));
#2773=AXIS2_PLACEMENT_3D('',#2770,#2771,#2772);
#2774=PLANE('',#2773);
#2775=ORIENTED_EDGE('',*,*,#2740,.T.);
#2776=ORIENTED_EDGE('',*,*,#2606,.F.);
#2777=DIRECTION('',(-0.577350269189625,-0.577350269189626,0.577350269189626));
#2778=VECTOR('',#2777,1.);
#2779=CARTESIAN_POINT('',(-6.49999999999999,-52.,-6.83));
#2780=LINE('',#2779,#2778);
#2781=EDGE_CURVE('E496',#151,#2597,#2780,.F.);
#2782=ORIENTED_EDGE('',*,*,#2781,.F.);
#2783=ORIENTED_EDGE('',*,*,#152,.F.);
#2784=EDGE_LOOP('',(#2775,#2776,#2782,#2783));
#2785=FACE_BOUND('',#2784,.T.);
#2786=ADVANCED_FACE('F1087',(#2785),#2774,.T.);
#2787=CARTESIAN_POINT('',(-6.49999999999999,-52.,-6.83));
#2788=DIRECTION('',(0.,-0.707106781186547,-0.707106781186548));
#2789=DIRECTION('',(1.,0.,0.));
#2790=AXIS2_PLACEMENT_3D('',#2787,#2788,#2789);
#2791=PLANE('',#2790);
#2792=ORIENTED_EDGE('',*,*,#2764,.T.);
#2793=ORIENTED_EDGE('',*,*,#160,.F.);
#2794=ORIENTED_EDGE('',*,*,#2781,.T.);
#2795=ORIENTED_EDGE('',*,*,#2635,.F.);
#2796=EDGE_LOOP('',(#2792,#2793,#2794,#2795));
#2797=FACE_BOUND('',#2796,.T.);
#2798=ADVANCED_FACE('F1083',(#2797),#2791,.T.);
#2799=CARTESIAN_POINT('',(49.,23.,-12.));
#2800=DIRECTION('',(-1.,0.,0.));
#2801=DIRECTION('',(0.,-1.,0.));
#2802=AXIS2_PLACEMENT_3D('',#2799,#2800,#2801);
#2803=PLANE('',#2802);
#2804=CARTESIAN_POINT('',(49.,23.,-12.));
#2805=DIRECTION('',(-1.,0.,0.));
#2806=DIRECTION('',(0.,-1.,0.));
#2807=AXIS2_PLACEMENT_3D('',#2804,#2805,#2806);
#2808=CIRCLE('',#2807,1.6);
#2809=CARTESIAN_POINT('',(49.,24.6,-12.));
#2810=VERTEX_POINT('',#2809);
#2811=EDGE_CURVE('E522',#2810,#2810,#2808,.T.);
#2812=ORIENTED_EDGE('',*,*,#2811,.T.);
#2813=EDGE_LOOP('',(#2812));
#2814=FACE_BOUND('',#2813,.T.);
#2815=ADVANCED_FACE('F1164',(#2814),#2803,.T.);
#2816=CARTESIAN_POINT('',(-49.,23.,-12.));
#2817=DIRECTION('',(1.,0.,0.));
#2818=DIRECTION('',(0.,1.,0.));
#2819=AXIS2_PLACEMENT_3D('',#2816,#2817,#2818);
#2820=CYLINDRICAL_SURFACE('',#2819,1.6);
#2821=CARTESIAN_POINT('',(48.,24.6,-12.));
#2822=CARTESIAN_POINT('',(48.0104166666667,24.6,-12.));
#2823=CARTESIAN_POINT('',(48.0208333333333,24.6,-12.));
#2824=CARTESIAN_POINT('',(48.0416666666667,24.6,-12.));
#2825=CARTESIAN_POINT('',(48.0520833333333,24.6,-12.));
#2826=CARTESIAN_POINT('',(48.0729166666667,24.6,-12.));
#2827=CARTESIAN_POINT('',(48.0833333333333,24.6,-12.));
#2828=CARTESIAN_POINT('',(48.1041666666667,24.6,-12.));
#2829=CARTESIAN_POINT('',(48.1145833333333,24.6,-12.));
#2830=CARTESIAN_POINT('',(48.1354166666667,24.6,-12.));
#2831=CARTESIAN_POINT('',(48.1458333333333,24.6,-12.));
#2832=CARTESIAN_POINT('',(48.1666666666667,24.6,-12.));
#2833=CARTESIAN_POINT('',(48.1770833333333,24.6,-12.));
#2834=CARTESIAN_POINT('',(48.1979166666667,24.6,-12.));
#2835=CARTESIAN_POINT('',(48.2083333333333,24.6,-12.));
#2836=CARTESIAN_POINT('',(48.2291666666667,24.6,-12.));
#2837=CARTESIAN_POINT('',(48.2395833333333,24.6,-12.));
#2838=CARTESIAN_POINT('',(48.2604166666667,24.6,-12.));
#2839=CARTESIAN_POINT('',(48.2708333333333,24.6,-12.));
#2840=CARTESIAN_POINT('',(48.2916666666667,24.6,-12.));
#2841=CARTESIAN_POINT('',(48.3020833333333,24.6,-12.));
#2842=CARTESIAN_POINT('',(48.3229166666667,24.6,-12.));
#2843=CARTESIAN_POINT('',(48.3333333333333,24.6,-12.));
#2844=CARTESIAN_POINT('',(48.3541666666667,24.6,-12.));
#2845=CARTESIAN_POINT('',(48.3645833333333,24.6,-12.));
#2846=CARTESIAN_POINT('',(48.3854166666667,24.6,-12.));
#2847=CARTESIAN_POINT('',(48.3958333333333,24.6,-12.));
#2848=CARTESIAN_POINT('',(48.4166666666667,24.6,-12.));
#2849=CARTESIAN_POINT('',(48.4270833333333,24.6,-12.));
#2850=CARTESIAN_POINT('',(48.4479166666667,24.6,-12.));
#2851=CARTESIAN_POINT('',(48.4583333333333,24.6,-12.));
#2852=CARTESIAN_POINT('',(48.4791666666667,24.6,-12.));
#2853=CARTESIAN_POINT('',(48.4895833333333,24.6,-12.));
#2854=CARTESIAN_POINT('',(48.5104166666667,24.6,-12.));
#2855=CARTESIAN_POINT('',(48.5208333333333,24.6,-12.));
#2856=CARTESIAN_POINT('',(48.5416666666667,24.6,-12.));
#2857=CARTESIAN_POINT('',(48.5520833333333,24.6,-12.));
#2858=CARTESIAN_POINT('',(48.5729166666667,24.6,-12.));
#2859=CARTESIAN_POINT('',(48.5833333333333,24.6,-12.));
#2860=CARTESIAN_POINT('',(48.6041666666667,24.6,-12.));
#2861=CARTESIAN_POINT('',(48.6145833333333,24.6,-12.));
#2862=CARTESIAN_POINT('',(48.6354166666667,24.6,-12.));
#2863=CARTESIAN_POINT('',(48.6458333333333,24.6,-12.));
#2864=CARTESIAN_POINT('',(48.6666666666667,24.6,-12.));
#2865=CARTESIAN_POINT('',(48.6770833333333,24.6,-12.));
#2866=CARTESIAN_POINT('',(48.6979166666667,24.6,-12.));
#2867=CARTESIAN_POINT('',(48.7083333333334,24.6,-12.));
#2868=CARTESIAN_POINT('',(48.7291666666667,24.6,-12.));
#2869=CARTESIAN_POINT('',(48.7395833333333,24.6,-12.));
#2870=CARTESIAN_POINT('',(48.7604166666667,24.6,-12.));
#2871=CARTESIAN_POINT('',(48.7708333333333,24.6,-12.));
#2872=CARTESIAN_POINT('',(48.7916666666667,24.6,-12.));
#2873=CARTESIAN_POINT('',(48.8020833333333,24.6,-12.));
#2874=CARTESIAN_POINT('',(48.8229166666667,24.6,-12.));
#2875=CARTESIAN_POINT('',(48.8333333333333,24.6,-12.));
#2876=CARTESIAN_POINT('',(48.8541666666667,24.6,-12.));
#2877=CARTESIAN_POINT('',(48.8645833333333,24.6,-12.));
#2878=CARTESIAN_POINT('',(48.8854166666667,24.6,-12.));
#2879=CARTESIAN_POINT('',(48.8958333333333,24.6,-12.));
#2880=CARTESIAN_POINT('',(48.9166666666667,24.6,-12.));
#2881=CARTESIAN_POINT('',(48.9270833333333,24.6,-12.));
#2882=CARTESIAN_POINT('',(48.9479166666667,24.6,-12.));
#2883=CARTESIAN_POINT('',(48.9583333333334,24.6,-12.));
#2884=CARTESIAN_POINT('',(48.9791666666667,24.6,-12.));
#2885=CARTESIAN_POINT('',(48.9895833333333,24.6,-12.));
#2886=CARTESIAN_POINT('',(49.,24.6,-12.));
#2887=B_SPLINE_CURVE_WITH_KNOTS('',3,(#2821,#2822,#2823,#2824,#2825,#2826,#2827,#2828,#2829,
#2830,#2831,#2832,#2833,#2834,#2835,#2836,#2837,#2838,#2839,#2840,#2841,#2842,#2843,#2844,#2845,
#2846,#2847,#2848,#2849,#2850,#2851,#2852,#2853,#2854,#2855,#2856,#2857,#2858,#2859,#2860,#2861,
#2862,#2863,#2864,#2865,#2866,#2867,#2868,#2869,#2870,#2871,#2872,#2873,#2874,#2875,#2876,#2877,
#2878,#2879,#2880,#2881,#2882,#2883,#2884,#2885,#2886),.UNSPECIFIED.,.F.,.F.,(4,2,2,2,2,2,2,2,2,
2,2,2,2,2,2,2,2,2,2,2,2,2,2,2,2,2,2,2,2,2,2,2,4),(0.,0.0312499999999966,0.0624999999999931,
0.0937500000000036,0.125,0.156249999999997,0.187500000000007,0.218750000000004,0.25,
0.281249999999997,0.312499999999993,0.343750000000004,0.375,0.406249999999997,0.437500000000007,
0.468750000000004,0.5,0.531249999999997,0.562499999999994,0.593750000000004,0.625000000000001,
0.656249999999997,0.687500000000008,0.718750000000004,0.750000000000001,0.781249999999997,
0.812499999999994,0.843750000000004,0.875000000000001,0.906249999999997,0.937500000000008,
0.968750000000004,1.),.UNSPECIFIED.);
#2888=EDGE_CURVE('BSEAM2029',#859,#2810,#2887,.T.);
#2889=ORIENTED_EDGE('',*,*,#860,.F.);
#2890=ORIENTED_EDGE('',*,*,#2811,.F.);
#2891=ORIENTED_EDGE('',*,*,#2888,.T.);
#2892=ORIENTED_EDGE('',*,*,#2888,.F.);
#2893=EDGE_LOOP('',(#2889,#2891,#2890,#2892));
#2894=FACE_BOUND('',#2893,.T.);
#2895=ADVANCED_FACE('F2029',(#2894),#2820,.F.);
#2896=CARTESIAN_POINT('',(49.,-23.,-12.));
#2897=DIRECTION('',(-1.,0.,0.));
#2898=DIRECTION('',(0.,-1.,0.));
#2899=AXIS2_PLACEMENT_3D('',#2896,#2897,#2898);
#2900=PLANE('',#2899);
#2901=CARTESIAN_POINT('',(49.,-23.,-12.));
#2902=DIRECTION('',(-1.,0.,0.));
#2903=DIRECTION('',(0.,-1.,0.));
#2904=AXIS2_PLACEMENT_3D('',#2901,#2902,#2903);
#2905=CIRCLE('',#2904,1.6);
#2906=CARTESIAN_POINT('',(49.,-21.4,-12.));
#2907=VERTEX_POINT('',#2906);
#2908=EDGE_CURVE('E514',#2907,#2907,#2905,.T.);
#2909=ORIENTED_EDGE('',*,*,#2908,.T.);
#2910=EDGE_LOOP('',(#2909));
#2911=FACE_BOUND('',#2910,.T.);
#2912=ADVANCED_FACE('F2038',(#2911),#2900,.T.);
#2913=CARTESIAN_POINT('',(-49.,-23.,-12.));
#2914=DIRECTION('',(1.,0.,0.));
#2915=DIRECTION('',(0.,1.,0.));
#2916=AXIS2_PLACEMENT_3D('',#2913,#2914,#2915);
#2917=CYLINDRICAL_SURFACE('',#2916,1.6);
#2918=CARTESIAN_POINT('',(48.,-21.4,-12.));
#2919=CARTESIAN_POINT('',(48.0104166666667,-21.4,-12.));
#2920=CARTESIAN_POINT('',(48.0208333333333,-21.4,-12.));
#2921=CARTESIAN_POINT('',(48.0416666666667,-21.4,-12.));
#2922=CARTESIAN_POINT('',(48.0520833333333,-21.4,-12.));
#2923=CARTESIAN_POINT('',(48.0729166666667,-21.4,-12.));
#2924=CARTESIAN_POINT('',(48.0833333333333,-21.4,-12.));
#2925=CARTESIAN_POINT('',(48.1041666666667,-21.4,-12.));
#2926=CARTESIAN_POINT('',(48.1145833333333,-21.4,-12.));
#2927=CARTESIAN_POINT('',(48.1354166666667,-21.4,-12.));
#2928=CARTESIAN_POINT('',(48.1458333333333,-21.4,-12.));
#2929=CARTESIAN_POINT('',(48.1666666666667,-21.4,-12.));
#2930=CARTESIAN_POINT('',(48.1770833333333,-21.4,-12.));
#2931=CARTESIAN_POINT('',(48.1979166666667,-21.4,-12.));
#2932=CARTESIAN_POINT('',(48.2083333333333,-21.4,-12.));
#2933=CARTESIAN_POINT('',(48.2291666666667,-21.4,-12.));
#2934=CARTESIAN_POINT('',(48.2395833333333,-21.4,-12.));
#2935=CARTESIAN_POINT('',(48.2604166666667,-21.4,-12.));
#2936=CARTESIAN_POINT('',(48.2708333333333,-21.4,-12.));
#2937=CARTESIAN_POINT('',(48.2916666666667,-21.4,-12.));
#2938=CARTESIAN_POINT('',(48.3020833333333,-21.4,-12.));
#2939=CARTESIAN_POINT('',(48.3229166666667,-21.4,-12.));
#2940=CARTESIAN_POINT('',(48.3333333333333,-21.4,-12.));
#2941=CARTESIAN_POINT('',(48.3541666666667,-21.4,-12.));
#2942=CARTESIAN_POINT('',(48.3645833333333,-21.4,-12.));
#2943=CARTESIAN_POINT('',(48.3854166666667,-21.4,-12.));
#2944=CARTESIAN_POINT('',(48.3958333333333,-21.4,-12.));
#2945=CARTESIAN_POINT('',(48.4166666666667,-21.4,-12.));
#2946=CARTESIAN_POINT('',(48.4270833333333,-21.4,-12.));
#2947=CARTESIAN_POINT('',(48.4479166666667,-21.4,-12.));
#2948=CARTESIAN_POINT('',(48.4583333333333,-21.4,-12.));
#2949=CARTESIAN_POINT('',(48.4791666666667,-21.4,-12.));
#2950=CARTESIAN_POINT('',(48.4895833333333,-21.4,-12.));
#2951=CARTESIAN_POINT('',(48.5104166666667,-21.4,-12.));
#2952=CARTESIAN_POINT('',(48.5208333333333,-21.4,-12.));
#2953=CARTESIAN_POINT('',(48.5416666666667,-21.4,-12.));
#2954=CARTESIAN_POINT('',(48.5520833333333,-21.4,-12.));
#2955=CARTESIAN_POINT('',(48.5729166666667,-21.4,-12.));
#2956=CARTESIAN_POINT('',(48.5833333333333,-21.4,-12.));
#2957=CARTESIAN_POINT('',(48.6041666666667,-21.4,-12.));
#2958=CARTESIAN_POINT('',(48.6145833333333,-21.4,-12.));
#2959=CARTESIAN_POINT('',(48.6354166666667,-21.4,-12.));
#2960=CARTESIAN_POINT('',(48.6458333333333,-21.4,-12.));
#2961=CARTESIAN_POINT('',(48.6666666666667,-21.4,-12.));
#2962=CARTESIAN_POINT('',(48.6770833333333,-21.4,-12.));
#2963=CARTESIAN_POINT('',(48.6979166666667,-21.4,-12.));
#2964=CARTESIAN_POINT('',(48.7083333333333,-21.4,-12.));
#2965=CARTESIAN_POINT('',(48.7291666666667,-21.4,-12.));
#2966=CARTESIAN_POINT('',(48.7395833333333,-21.4,-12.));
#2967=CARTESIAN_POINT('',(48.7604166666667,-21.4,-12.));
#2968=CARTESIAN_POINT('',(48.7708333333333,-21.4,-12.));
#2969=CARTESIAN_POINT('',(48.7916666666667,-21.4,-12.));
#2970=CARTESIAN_POINT('',(48.8020833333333,-21.4,-12.));
#2971=CARTESIAN_POINT('',(48.8229166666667,-21.4,-12.));
#2972=CARTESIAN_POINT('',(48.8333333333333,-21.4,-12.));
#2973=CARTESIAN_POINT('',(48.8541666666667,-21.4,-12.));
#2974=CARTESIAN_POINT('',(48.8645833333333,-21.4,-12.));
#2975=CARTESIAN_POINT('',(48.8854166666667,-21.4,-12.));
#2976=CARTESIAN_POINT('',(48.8958333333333,-21.4,-12.));
#2977=CARTESIAN_POINT('',(48.9166666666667,-21.4,-12.));
#2978=CARTESIAN_POINT('',(48.9270833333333,-21.4,-12.));
#2979=CARTESIAN_POINT('',(48.9479166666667,-21.4,-12.));
#2980=CARTESIAN_POINT('',(48.9583333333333,-21.4,-12.));
#2981=CARTESIAN_POINT('',(48.9791666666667,-21.4,-12.));
#2982=CARTESIAN_POINT('',(48.9895833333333,-21.4,-12.));
#2983=CARTESIAN_POINT('',(49.,-21.4,-12.));
#2984=B_SPLINE_CURVE_WITH_KNOTS('',3,(#2918,#2919,#2920,#2921,#2922,#2923,#2924,#2925,#2926,
#2927,#2928,#2929,#2930,#2931,#2932,#2933,#2934,#2935,#2936,#2937,#2938,#2939,#2940,#2941,#2942,
#2943,#2944,#2945,#2946,#2947,#2948,#2949,#2950,#2951,#2952,#2953,#2954,#2955,#2956,#2957,#2958,
#2959,#2960,#2961,#2962,#2963,#2964,#2965,#2966,#2967,#2968,#2969,#2970,#2971,#2972,#2973,#2974,
#2975,#2976,#2977,#2978,#2979,#2980,#2981,#2982,#2983),.UNSPECIFIED.,.F.,.F.,(4,2,2,2,2,2,2,2,2,
2,2,2,2,2,2,2,2,2,2,2,2,2,2,2,2,2,2,2,2,2,2,2,4),(0.,0.0312499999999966,0.0624999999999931,
0.0937500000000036,0.125,0.156249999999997,0.187500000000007,0.218750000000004,0.25,
0.281249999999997,0.312499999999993,0.343750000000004,0.375,0.406249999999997,0.437500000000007,
0.468750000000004,0.5,0.531249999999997,0.562499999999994,0.593750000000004,0.625000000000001,
0.656249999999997,0.687500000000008,0.718750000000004,0.750000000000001,0.781249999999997,
0.812499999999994,0.843750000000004,0.875000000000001,0.906249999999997,0.937500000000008,
0.968750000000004,1.),.UNSPECIFIED.);
#2985=EDGE_CURVE('BSEAM2048',#848,#2907,#2984,.T.);
#2986=ORIENTED_EDGE('',*,*,#849,.F.);
#2987=ORIENTED_EDGE('',*,*,#2908,.F.);
#2988=ORIENTED_EDGE('',*,*,#2985,.T.);
#2989=ORIENTED_EDGE('',*,*,#2985,.F.);
#2990=EDGE_LOOP('',(#2986,#2988,#2987,#2989));
#2991=FACE_BOUND('',#2990,.T.);
#2992=ADVANCED_FACE('F2048',(#2991),#2917,.F.);
#2993=CARTESIAN_POINT('',(-49.,23.,-12.));
#2994=DIRECTION('',(-1.,0.,0.));
#2995=DIRECTION('',(0.,-1.,0.));
#2996=AXIS2_PLACEMENT_3D('',#2993,#2994,#2995);
#2997=CIRCLE('',#2996,1.6);
#2998=CARTESIAN_POINT('',(-49.,24.6,-12.));
#2999=VERTEX_POINT('',#2998);
#3000=EDGE_CURVE('E519',#2999,#2999,#2997,.T.);
#3001=CARTESIAN_POINT('',(-48.,24.6,-12.));
#3002=CARTESIAN_POINT('',(-48.0104166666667,24.6,-12.));
#3003=CARTESIAN_POINT('',(-48.0208333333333,24.6,-12.));
#3004=CARTESIAN_POINT('',(-48.0416666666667,24.6,-12.));
#3005=CARTESIAN_POINT('',(-48.0520833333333,24.6,-12.));
#3006=CARTESIAN_POINT('',(-48.0729166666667,24.6,-12.));
#3007=CARTESIAN_POINT('',(-48.0833333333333,24.6,-12.));
#3008=CARTESIAN_POINT('',(-48.1041666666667,24.6,-12.));
#3009=CARTESIAN_POINT('',(-48.1145833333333,24.6,-12.));
#3010=CARTESIAN_POINT('',(-48.1354166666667,24.6,-12.));
#3011=CARTESIAN_POINT('',(-48.1458333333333,24.6,-12.));
#3012=CARTESIAN_POINT('',(-48.1666666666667,24.6,-12.));
#3013=CARTESIAN_POINT('',(-48.1770833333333,24.6,-12.));
#3014=CARTESIAN_POINT('',(-48.1979166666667,24.6,-12.));
#3015=CARTESIAN_POINT('',(-48.2083333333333,24.6,-12.));
#3016=CARTESIAN_POINT('',(-48.2291666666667,24.6,-12.));
#3017=CARTESIAN_POINT('',(-48.2395833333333,24.6,-12.));
#3018=CARTESIAN_POINT('',(-48.2604166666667,24.6,-12.));
#3019=CARTESIAN_POINT('',(-48.2708333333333,24.6,-12.));
#3020=CARTESIAN_POINT('',(-48.2916666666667,24.6,-12.));
#3021=CARTESIAN_POINT('',(-48.3020833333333,24.6,-12.));
#3022=CARTESIAN_POINT('',(-48.3229166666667,24.6,-12.));
#3023=CARTESIAN_POINT('',(-48.3333333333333,24.6,-12.));
#3024=CARTESIAN_POINT('',(-48.3541666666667,24.6,-12.));
#3025=CARTESIAN_POINT('',(-48.3645833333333,24.6,-12.));
#3026=CARTESIAN_POINT('',(-48.3854166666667,24.6,-12.));
#3027=CARTESIAN_POINT('',(-48.3958333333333,24.6,-12.));
#3028=CARTESIAN_POINT('',(-48.4166666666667,24.6,-12.));
#3029=CARTESIAN_POINT('',(-48.4270833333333,24.6,-12.));
#3030=CARTESIAN_POINT('',(-48.4479166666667,24.6,-12.));
#3031=CARTESIAN_POINT('',(-48.4583333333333,24.6,-12.));
#3032=CARTESIAN_POINT('',(-48.4791666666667,24.6,-12.));
#3033=CARTESIAN_POINT('',(-48.4895833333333,24.6,-12.));
#3034=CARTESIAN_POINT('',(-48.5104166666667,24.6,-12.));
#3035=CARTESIAN_POINT('',(-48.5208333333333,24.6,-12.));
#3036=CARTESIAN_POINT('',(-48.5416666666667,24.6,-12.));
#3037=CARTESIAN_POINT('',(-48.5520833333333,24.6,-12.));
#3038=CARTESIAN_POINT('',(-48.5729166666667,24.6,-12.));
#3039=CARTESIAN_POINT('',(-48.5833333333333,24.6,-12.));
#3040=CARTESIAN_POINT('',(-48.6041666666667,24.6,-12.));
#3041=CARTESIAN_POINT('',(-48.6145833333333,24.6,-12.));
#3042=CARTESIAN_POINT('',(-48.6354166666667,24.6,-12.));
#3043=CARTESIAN_POINT('',(-48.6458333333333,24.6,-12.));
#3044=CARTESIAN_POINT('',(-48.6666666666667,24.6,-12.));
#3045=CARTESIAN_POINT('',(-48.6770833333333,24.6,-12.));
#3046=CARTESIAN_POINT('',(-48.6979166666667,24.6,-12.));
#3047=CARTESIAN_POINT('',(-48.7083333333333,24.6,-12.));
#3048=CARTESIAN_POINT('',(-48.7291666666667,24.6,-12.));
#3049=CARTESIAN_POINT('',(-48.7395833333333,24.6,-12.));
#3050=CARTESIAN_POINT('',(-48.7604166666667,24.6,-12.));
#3051=CARTESIAN_POINT('',(-48.7708333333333,24.6,-12.));
#3052=CARTESIAN_POINT('',(-48.7916666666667,24.6,-12.));
#3053=CARTESIAN_POINT('',(-48.8020833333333,24.6,-12.));
#3054=CARTESIAN_POINT('',(-48.8229166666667,24.6,-12.));
#3055=CARTESIAN_POINT('',(-48.8333333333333,24.6,-12.));
#3056=CARTESIAN_POINT('',(-48.8541666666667,24.6,-12.));
#3057=CARTESIAN_POINT('',(-48.8645833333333,24.6,-12.));
#3058=CARTESIAN_POINT('',(-48.8854166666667,24.6,-12.));
#3059=CARTESIAN_POINT('',(-48.8958333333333,24.6,-12.));
#3060=CARTESIAN_POINT('',(-48.9166666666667,24.6,-12.));
#3061=CARTESIAN_POINT('',(-48.9270833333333,24.6,-12.));
#3062=CARTESIAN_POINT('',(-48.9479166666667,24.6,-12.));
#3063=CARTESIAN_POINT('',(-48.9583333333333,24.6,-12.));
#3064=CARTESIAN_POINT('',(-48.9791666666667,24.6,-12.));
#3065=CARTESIAN_POINT('',(-48.9895833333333,24.6,-12.));
#3066=CARTESIAN_POINT('',(-49.,24.6,-12.));
#3067=B_SPLINE_CURVE_WITH_KNOTS('',3,(#3001,#3002,#3003,#3004,#3005,#3006,#3007,#3008,#3009,
#3010,#3011,#3012,#3013,#3014,#3015,#3016,#3017,#3018,#3019,#3020,#3021,#3022,#3023,#3024,#3025,
#3026,#3027,#3028,#3029,#3030,#3031,#3032,#3033,#3034,#3035,#3036,#3037,#3038,#3039,#3040,#3041,
#3042,#3043,#3044,#3045,#3046,#3047,#3048,#3049,#3050,#3051,#3052,#3053,#3054,#3055,#3056,#3057,
#3058,#3059,#3060,#3061,#3062,#3063,#3064,#3065,#3066),.UNSPECIFIED.,.F.,.F.,(4,2,2,2,2,2,2,2,2,
2,2,2,2,2,2,2,2,2,2,2,2,2,2,2,2,2,2,2,2,2,2,2,4),(0.,0.0312500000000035,0.0625000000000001,
0.0937500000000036,0.125,0.156250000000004,0.1875,0.218750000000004,0.25,0.281249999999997,
0.3125,0.343749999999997,0.375,0.406249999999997,0.4375,0.468749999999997,0.499999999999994,
0.531249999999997,0.562499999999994,0.593749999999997,0.624999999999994,0.656249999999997,
0.687499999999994,0.718749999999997,0.749999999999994,0.78124999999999,0.812499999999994,
0.84374999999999,0.874999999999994,0.90624999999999,0.937499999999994,0.96874999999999,
0.999999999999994),.UNSPECIFIED.);
#3068=EDGE_CURVE('BSEAM2041',#741,#2999,#3067,.T.);
#3069=ORIENTED_EDGE('',*,*,#742,.F.);
#3070=ORIENTED_EDGE('',*,*,#3000,.T.);
#3071=ORIENTED_EDGE('',*,*,#3068,.T.);
#3072=ORIENTED_EDGE('',*,*,#3068,.F.);
#3073=EDGE_LOOP('',(#3069,#3071,#3070,#3072));
#3074=FACE_BOUND('',#3073,.T.);
#3075=ADVANCED_FACE('F2041',(#3074),#2820,.F.);
#3076=CARTESIAN_POINT('',(-49.,23.,-12.));
#3077=DIRECTION('',(-1.,0.,0.));
#3078=DIRECTION('',(0.,-1.,0.));
#3079=AXIS2_PLACEMENT_3D('',#3076,#3077,#3078);
#3080=PLANE('',#3079);
#3081=ORIENTED_EDGE('',*,*,#3000,.F.);
#3082=EDGE_LOOP('',(#3081));
#3083=FACE_BOUND('',#3082,.T.);
#3084=ADVANCED_FACE('F2066',(#3083),#3080,.F.);
#3085=CARTESIAN_POINT('',(-49.,-23.,-12.));
#3086=DIRECTION('',(-1.,0.,0.));
#3087=DIRECTION('',(0.,-1.,0.));
#3088=AXIS2_PLACEMENT_3D('',#3085,#3086,#3087);
#3089=CIRCLE('',#3088,1.6);
#3090=CARTESIAN_POINT('',(-49.,-21.4,-12.));
#3091=VERTEX_POINT('',#3090);
#3092=EDGE_CURVE('E508',#3091,#3091,#3089,.T.);
#3093=CARTESIAN_POINT('',(-48.,-21.4,-12.));
#3094=CARTESIAN_POINT('',(-48.0104166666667,-21.4,-12.));
#3095=CARTESIAN_POINT('',(-48.0208333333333,-21.4,-12.));
#3096=CARTESIAN_POINT('',(-48.0416666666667,-21.4,-12.));
#3097=CARTESIAN_POINT('',(-48.0520833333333,-21.4,-12.));
#3098=CARTESIAN_POINT('',(-48.0729166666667,-21.4,-12.));
#3099=CARTESIAN_POINT('',(-48.0833333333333,-21.4,-12.));
#3100=CARTESIAN_POINT('',(-48.1041666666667,-21.4,-12.));
#3101=CARTESIAN_POINT('',(-48.1145833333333,-21.4,-12.));
#3102=CARTESIAN_POINT('',(-48.1354166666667,-21.4,-12.));
#3103=CARTESIAN_POINT('',(-48.1458333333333,-21.4,-12.));
#3104=CARTESIAN_POINT('',(-48.1666666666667,-21.4,-12.));
#3105=CARTESIAN_POINT('',(-48.1770833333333,-21.4,-12.));
#3106=CARTESIAN_POINT('',(-48.1979166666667,-21.4,-12.));
#3107=CARTESIAN_POINT('',(-48.2083333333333,-21.4,-12.));
#3108=CARTESIAN_POINT('',(-48.2291666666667,-21.4,-12.));
#3109=CARTESIAN_POINT('',(-48.2395833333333,-21.4,-12.));
#3110=CARTESIAN_POINT('',(-48.2604166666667,-21.4,-12.));
#3111=CARTESIAN_POINT('',(-48.2708333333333,-21.4,-12.));
#3112=CARTESIAN_POINT('',(-48.2916666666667,-21.4,-12.));
#3113=CARTESIAN_POINT('',(-48.3020833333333,-21.4,-12.));
#3114=CARTESIAN_POINT('',(-48.3229166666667,-21.4,-12.));
#3115=CARTESIAN_POINT('',(-48.3333333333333,-21.4,-12.));
#3116=CARTESIAN_POINT('',(-48.3541666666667,-21.4,-12.));
#3117=CARTESIAN_POINT('',(-48.3645833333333,-21.4,-12.));
#3118=CARTESIAN_POINT('',(-48.3854166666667,-21.4,-12.));
#3119=CARTESIAN_POINT('',(-48.3958333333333,-21.4,-12.));
#3120=CARTESIAN_POINT('',(-48.4166666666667,-21.4,-12.));
#3121=CARTESIAN_POINT('',(-48.4270833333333,-21.4,-12.));
#3122=CARTESIAN_POINT('',(-48.4479166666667,-21.4,-12.));
#3123=CARTESIAN_POINT('',(-48.4583333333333,-21.4,-12.));
#3124=CARTESIAN_POINT('',(-48.4791666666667,-21.4,-12.));
#3125=CARTESIAN_POINT('',(-48.4895833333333,-21.4,-12.));
#3126=CARTESIAN_POINT('',(-48.5104166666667,-21.4,-12.));
#3127=CARTESIAN_POINT('',(-48.5208333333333,-21.4,-12.));
#3128=CARTESIAN_POINT('',(-48.5416666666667,-21.4,-12.));
#3129=CARTESIAN_POINT('',(-48.5520833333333,-21.4,-12.));
#3130=CARTESIAN_POINT('',(-48.5729166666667,-21.4,-12.));
#3131=CARTESIAN_POINT('',(-48.5833333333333,-21.4,-12.));
#3132=CARTESIAN_POINT('',(-48.6041666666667,-21.4,-12.));
#3133=CARTESIAN_POINT('',(-48.6145833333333,-21.4,-12.));
#3134=CARTESIAN_POINT('',(-48.6354166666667,-21.4,-12.));
#3135=CARTESIAN_POINT('',(-48.6458333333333,-21.4,-12.));
#3136=CARTESIAN_POINT('',(-48.6666666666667,-21.4,-12.));
#3137=CARTESIAN_POINT('',(-48.6770833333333,-21.4,-12.));
#3138=CARTESIAN_POINT('',(-48.6979166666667,-21.4,-12.));
#3139=CARTESIAN_POINT('',(-48.7083333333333,-21.4,-12.));
#3140=CARTESIAN_POINT('',(-48.7291666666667,-21.4,-12.));
#3141=CARTESIAN_POINT('',(-48.7395833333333,-21.4,-12.));
#3142=CARTESIAN_POINT('',(-48.7604166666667,-21.4,-12.));
#3143=CARTESIAN_POINT('',(-48.7708333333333,-21.4,-12.));
#3144=CARTESIAN_POINT('',(-48.7916666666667,-21.4,-12.));
#3145=CARTESIAN_POINT('',(-48.8020833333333,-21.4,-12.));
#3146=CARTESIAN_POINT('',(-48.8229166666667,-21.4,-12.));
#3147=CARTESIAN_POINT('',(-48.8333333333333,-21.4,-12.));
#3148=CARTESIAN_POINT('',(-48.8541666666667,-21.4,-12.));
#3149=CARTESIAN_POINT('',(-48.8645833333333,-21.4,-12.));
#3150=CARTESIAN_POINT('',(-48.8854166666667,-21.4,-12.));
#3151=CARTESIAN_POINT('',(-48.8958333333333,-21.4,-12.));
#3152=CARTESIAN_POINT('',(-48.9166666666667,-21.4,-12.));
#3153=CARTESIAN_POINT('',(-48.9270833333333,-21.4,-12.));
#3154=CARTESIAN_POINT('',(-48.9479166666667,-21.4,-12.));
#3155=CARTESIAN_POINT('',(-48.9583333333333,-21.4,-12.));
#3156=CARTESIAN_POINT('',(-48.9791666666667,-21.4,-12.));
#3157=CARTESIAN_POINT('',(-48.9895833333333,-21.4,-12.));
#3158=CARTESIAN_POINT('',(-49.,-21.4,-12.));
#3159=B_SPLINE_CURVE_WITH_KNOTS('',3,(#3093,#3094,#3095,#3096,#3097,#3098,#3099,#3100,#3101,
#3102,#3103,#3104,#3105,#3106,#3107,#3108,#3109,#3110,#3111,#3112,#3113,#3114,#3115,#3116,#3117,
#3118,#3119,#3120,#3121,#3122,#3123,#3124,#3125,#3126,#3127,#3128,#3129,#3130,#3131,#3132,#3133,
#3134,#3135,#3136,#3137,#3138,#3139,#3140,#3141,#3142,#3143,#3144,#3145,#3146,#3147,#3148,#3149,
#3150,#3151,#3152,#3153,#3154,#3155,#3156,#3157,#3158),.UNSPECIFIED.,.F.,.F.,(4,2,2,2,2,2,2,2,2,
2,2,2,2,2,2,2,2,2,2,2,2,2,2,2,2,2,2,2,2,2,2,2,4),(0.,0.0312500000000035,0.0625000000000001,
0.0937500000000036,0.125,0.156250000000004,0.1875,0.218750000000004,0.25,0.281250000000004,
0.3125,0.343750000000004,0.375,0.406250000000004,0.4375,0.468750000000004,0.5,0.531250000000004,
0.5625,0.593750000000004,0.625000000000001,0.656250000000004,0.687500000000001,
0.718750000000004,0.750000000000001,0.781250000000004,0.812500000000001,0.843750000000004,
0.875000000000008,0.906250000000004,0.937500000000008,0.968750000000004,1.00000000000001),.UNSPECIFIED.);
#3160=EDGE_CURVE('BSEAM2059',#730,#3091,#3159,.T.);
#3161=ORIENTED_EDGE('',*,*,#731,.F.);
#3162=ORIENTED_EDGE('',*,*,#3092,.T.);
#3163=ORIENTED_EDGE('',*,*,#3160,.T.);
#3164=ORIENTED_EDGE('',*,*,#3160,.F.);
#3165=EDGE_LOOP('',(#3161,#3163,#3162,#3164));
#3166=FACE_BOUND('',#3165,.T.);
#3167=ADVANCED_FACE('F2059',(#3166),#2917,.F.);
#3168=CARTESIAN_POINT('',(-49.,-23.,-12.));
#3169=DIRECTION('',(-1.,0.,0.));
#3170=DIRECTION('',(0.,-1.,0.));
#3171=AXIS2_PLACEMENT_3D('',#3168,#3169,#3170);
#3172=PLANE('',#3171);
#3173=ORIENTED_EDGE('',*,*,#3092,.F.);
#3174=EDGE_LOOP('',(#3173));
#3175=FACE_BOUND('',#3174,.T.);
#3176=ADVANCED_FACE('F2082',(#3175),#3172,.F.);
#3177=CLOSED_SHELL('',(#58,#98,#138,#212,#459,#605,#636,#694,#718,#764,#788,#812,#836,#875,
#1102,#1114,#1126,#1138,#1150,#1162,#1174,#1186,#1198,#1210,#1222,#1234,#1256,#1273,#1290,#1302,
#1314,#1326,#1348,#1365,#1382,#1394,#1414,#1489,#1520,#1544,#1568,#1592,#1616,#1640,#1664,#1681,
#1692,#1712,#1787,#1818,#1842,#1866,#1890,#1914,#1938,#1962,#1979,#1990,#2010,#2085,#2116,#2140,
#2164,#2188,#2212,#2236,#2260,#2277,#2288,#2308,#2383,#2414,#2438,#2462,#2486,#2510,#2534,#2558,
#2575,#2586,#2617,#2641,#2665,#2682,#2694,#2706,#2718,#2730,#2752,#2769,#2786,#2798,#2815,#2895,
#2912,#2992,#3075,#3084,#3167,#3176));
#3178=MANIFOLD_SOLID_BREP('B2',#3177);
#3179=ADVANCED_BREP_SHAPE_REPRESENTATION('',(#18,#3178),#14);
#3180=SHAPE_DEFINITION_REPRESENTATION(#9,#3179);
ENDSEC;
END-ISO-10303-21;
